VERSION 5.8 ;
BUSBITCHARS "[]" ;
DIVIDERCHAR "/" ;
UNITS
    DATABASE MICRONS 1000 ;
END UNITS

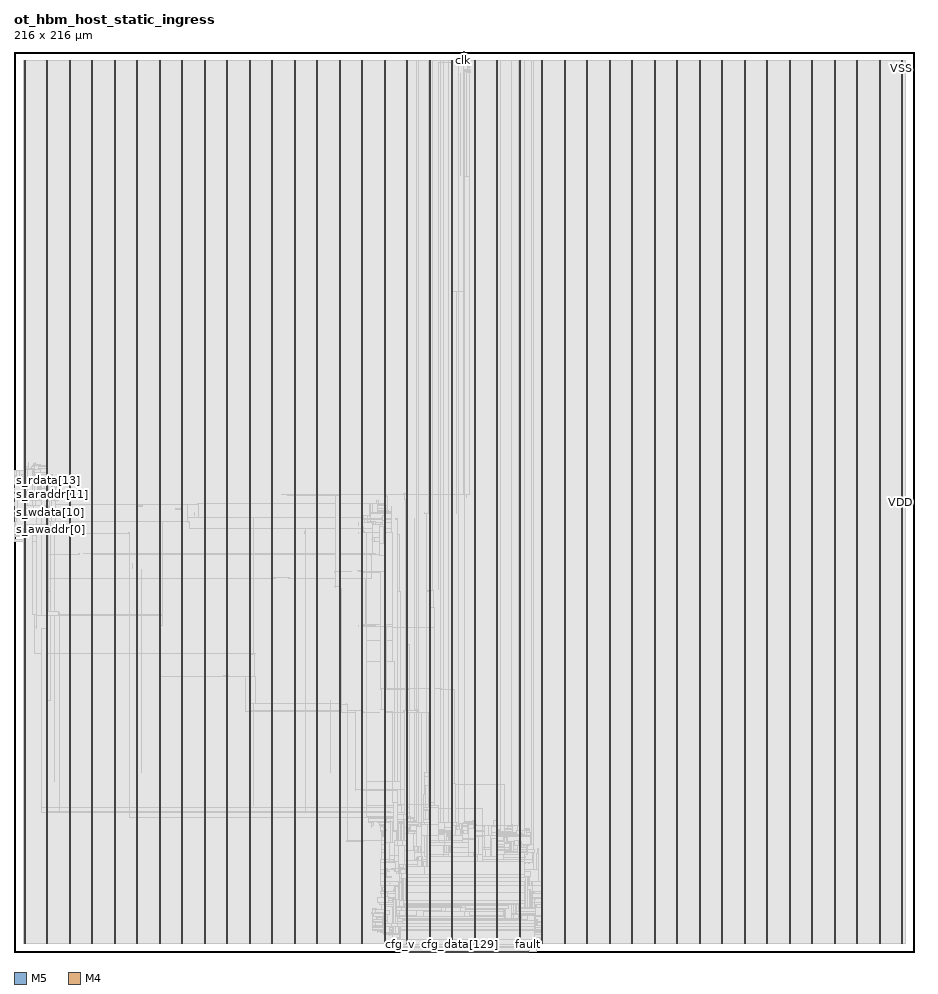
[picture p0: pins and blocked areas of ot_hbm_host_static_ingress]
MACRO ot_hbm_host_static_ingress
  FOREIGN ot_hbm_host_static_ingress 0 0 ;
  CLASS BLOCK ;
  SIZE 216 BY 216 ;
  PIN block_ready
    DIRECTION INPUT ;
    USE SIGNAL ;
    PORT
      LAYER M5 ;
        RECT  108 215.916 108.024 216 ;
    END
  END block_ready
  PIN cfg_addr[0]
    DIRECTION OUTPUT ;
    USE SIGNAL ;
    PORT
      LAYER M5 ;
        RECT  93.504 0 93.528 0.084 ;
    END
  END cfg_addr[0]
  PIN cfg_addr[10]
    DIRECTION OUTPUT ;
    USE SIGNAL ;
    PORT
      LAYER M5 ;
        RECT  94.464 0 94.488 0.084 ;
    END
  END cfg_addr[10]
  PIN cfg_addr[11]
    DIRECTION OUTPUT ;
    USE SIGNAL ;
    PORT
      LAYER M5 ;
        RECT  94.56 0 94.584 0.084 ;
    END
  END cfg_addr[11]
  PIN cfg_addr[1]
    DIRECTION OUTPUT ;
    USE SIGNAL ;
    PORT
      LAYER M5 ;
        RECT  93.6 0 93.624 0.084 ;
    END
  END cfg_addr[1]
  PIN cfg_addr[2]
    DIRECTION OUTPUT ;
    USE SIGNAL ;
    PORT
      LAYER M5 ;
        RECT  93.696 0 93.72 0.084 ;
    END
  END cfg_addr[2]
  PIN cfg_addr[3]
    DIRECTION OUTPUT ;
    USE SIGNAL ;
    PORT
      LAYER M5 ;
        RECT  93.792 0 93.816 0.084 ;
    END
  END cfg_addr[3]
  PIN cfg_addr[4]
    DIRECTION OUTPUT ;
    USE SIGNAL ;
    PORT
      LAYER M5 ;
        RECT  93.888 0 93.912 0.084 ;
    END
  END cfg_addr[4]
  PIN cfg_addr[5]
    DIRECTION OUTPUT ;
    USE SIGNAL ;
    PORT
      LAYER M5 ;
        RECT  93.984 0 94.008 0.084 ;
    END
  END cfg_addr[5]
  PIN cfg_addr[6]
    DIRECTION OUTPUT ;
    USE SIGNAL ;
    PORT
      LAYER M5 ;
        RECT  94.08 0 94.104 0.084 ;
    END
  END cfg_addr[6]
  PIN cfg_addr[7]
    DIRECTION OUTPUT ;
    USE SIGNAL ;
    PORT
      LAYER M5 ;
        RECT  94.176 0 94.2 0.084 ;
    END
  END cfg_addr[7]
  PIN cfg_addr[8]
    DIRECTION OUTPUT ;
    USE SIGNAL ;
    PORT
      LAYER M5 ;
        RECT  94.272 0 94.296 0.084 ;
    END
  END cfg_addr[8]
  PIN cfg_addr[9]
    DIRECTION OUTPUT ;
    USE SIGNAL ;
    PORT
      LAYER M5 ;
        RECT  94.368 0 94.392 0.084 ;
    END
  END cfg_addr[9]
  PIN cfg_data[0]
    DIRECTION OUTPUT ;
    USE SIGNAL ;
    PORT
      LAYER M5 ;
        RECT  94.656 0 94.68 0.084 ;
    END
  END cfg_data[0]
  PIN cfg_data[100]
    DIRECTION OUTPUT ;
    USE SIGNAL ;
    PORT
      LAYER M5 ;
        RECT  104.256 0 104.28 0.084 ;
    END
  END cfg_data[100]
  PIN cfg_data[101]
    DIRECTION OUTPUT ;
    USE SIGNAL ;
    PORT
      LAYER M5 ;
        RECT  104.352 0 104.376 0.084 ;
    END
  END cfg_data[101]
  PIN cfg_data[102]
    DIRECTION OUTPUT ;
    USE SIGNAL ;
    PORT
      LAYER M5 ;
        RECT  104.448 0 104.472 0.084 ;
    END
  END cfg_data[102]
  PIN cfg_data[103]
    DIRECTION OUTPUT ;
    USE SIGNAL ;
    PORT
      LAYER M5 ;
        RECT  104.544 0 104.568 0.084 ;
    END
  END cfg_data[103]
  PIN cfg_data[104]
    DIRECTION OUTPUT ;
    USE SIGNAL ;
    PORT
      LAYER M5 ;
        RECT  104.64 0 104.664 0.084 ;
    END
  END cfg_data[104]
  PIN cfg_data[105]
    DIRECTION OUTPUT ;
    USE SIGNAL ;
    PORT
      LAYER M5 ;
        RECT  104.736 0 104.76 0.084 ;
    END
  END cfg_data[105]
  PIN cfg_data[106]
    DIRECTION OUTPUT ;
    USE SIGNAL ;
    PORT
      LAYER M5 ;
        RECT  104.832 0 104.856 0.084 ;
    END
  END cfg_data[106]
  PIN cfg_data[107]
    DIRECTION OUTPUT ;
    USE SIGNAL ;
    PORT
      LAYER M5 ;
        RECT  104.928 0 104.952 0.084 ;
    END
  END cfg_data[107]
  PIN cfg_data[108]
    DIRECTION OUTPUT ;
    USE SIGNAL ;
    PORT
      LAYER M5 ;
        RECT  105.024 0 105.048 0.084 ;
    END
  END cfg_data[108]
  PIN cfg_data[109]
    DIRECTION OUTPUT ;
    USE SIGNAL ;
    PORT
      LAYER M5 ;
        RECT  105.12 0 105.144 0.084 ;
    END
  END cfg_data[109]
  PIN cfg_data[10]
    DIRECTION OUTPUT ;
    USE SIGNAL ;
    PORT
      LAYER M5 ;
        RECT  95.616 0 95.64 0.084 ;
    END
  END cfg_data[10]
  PIN cfg_data[110]
    DIRECTION OUTPUT ;
    USE SIGNAL ;
    PORT
      LAYER M5 ;
        RECT  105.216 0 105.24 0.084 ;
    END
  END cfg_data[110]
  PIN cfg_data[111]
    DIRECTION OUTPUT ;
    USE SIGNAL ;
    PORT
      LAYER M5 ;
        RECT  105.312 0 105.336 0.084 ;
    END
  END cfg_data[111]
  PIN cfg_data[112]
    DIRECTION OUTPUT ;
    USE SIGNAL ;
    PORT
      LAYER M5 ;
        RECT  105.408 0 105.432 0.084 ;
    END
  END cfg_data[112]
  PIN cfg_data[113]
    DIRECTION OUTPUT ;
    USE SIGNAL ;
    PORT
      LAYER M5 ;
        RECT  105.504 0 105.528 0.084 ;
    END
  END cfg_data[113]
  PIN cfg_data[114]
    DIRECTION OUTPUT ;
    USE SIGNAL ;
    PORT
      LAYER M5 ;
        RECT  105.6 0 105.624 0.084 ;
    END
  END cfg_data[114]
  PIN cfg_data[115]
    DIRECTION OUTPUT ;
    USE SIGNAL ;
    PORT
      LAYER M5 ;
        RECT  105.696 0 105.72 0.084 ;
    END
  END cfg_data[115]
  PIN cfg_data[116]
    DIRECTION OUTPUT ;
    USE SIGNAL ;
    PORT
      LAYER M5 ;
        RECT  105.792 0 105.816 0.084 ;
    END
  END cfg_data[116]
  PIN cfg_data[117]
    DIRECTION OUTPUT ;
    USE SIGNAL ;
    PORT
      LAYER M5 ;
        RECT  105.888 0 105.912 0.084 ;
    END
  END cfg_data[117]
  PIN cfg_data[118]
    DIRECTION OUTPUT ;
    USE SIGNAL ;
    PORT
      LAYER M5 ;
        RECT  105.984 0 106.008 0.084 ;
    END
  END cfg_data[118]
  PIN cfg_data[119]
    DIRECTION OUTPUT ;
    USE SIGNAL ;
    PORT
      LAYER M5 ;
        RECT  106.08 0 106.104 0.084 ;
    END
  END cfg_data[119]
  PIN cfg_data[11]
    DIRECTION OUTPUT ;
    USE SIGNAL ;
    PORT
      LAYER M5 ;
        RECT  95.712 0 95.736 0.084 ;
    END
  END cfg_data[11]
  PIN cfg_data[120]
    DIRECTION OUTPUT ;
    USE SIGNAL ;
    PORT
      LAYER M5 ;
        RECT  106.176 0 106.2 0.084 ;
    END
  END cfg_data[120]
  PIN cfg_data[121]
    DIRECTION OUTPUT ;
    USE SIGNAL ;
    PORT
      LAYER M5 ;
        RECT  106.272 0 106.296 0.084 ;
    END
  END cfg_data[121]
  PIN cfg_data[122]
    DIRECTION OUTPUT ;
    USE SIGNAL ;
    PORT
      LAYER M5 ;
        RECT  106.368 0 106.392 0.084 ;
    END
  END cfg_data[122]
  PIN cfg_data[123]
    DIRECTION OUTPUT ;
    USE SIGNAL ;
    PORT
      LAYER M5 ;
        RECT  106.464 0 106.488 0.084 ;
    END
  END cfg_data[123]
  PIN cfg_data[124]
    DIRECTION OUTPUT ;
    USE SIGNAL ;
    PORT
      LAYER M5 ;
        RECT  106.56 0 106.584 0.084 ;
    END
  END cfg_data[124]
  PIN cfg_data[125]
    DIRECTION OUTPUT ;
    USE SIGNAL ;
    PORT
      LAYER M5 ;
        RECT  106.656 0 106.68 0.084 ;
    END
  END cfg_data[125]
  PIN cfg_data[126]
    DIRECTION OUTPUT ;
    USE SIGNAL ;
    PORT
      LAYER M5 ;
        RECT  106.752 0 106.776 0.084 ;
    END
  END cfg_data[126]
  PIN cfg_data[127]
    DIRECTION OUTPUT ;
    USE SIGNAL ;
    PORT
      LAYER M5 ;
        RECT  106.848 0 106.872 0.084 ;
    END
  END cfg_data[127]
  PIN cfg_data[128]
    DIRECTION OUTPUT ;
    USE SIGNAL ;
    PORT
      LAYER M5 ;
        RECT  106.944 0 106.968 0.084 ;
    END
  END cfg_data[128]
  PIN cfg_data[129]
    DIRECTION OUTPUT ;
    USE SIGNAL ;
    PORT
      LAYER M5 ;
        RECT  107.04 0 107.064 0.084 ;
    END
  END cfg_data[129]
  PIN cfg_data[12]
    DIRECTION OUTPUT ;
    USE SIGNAL ;
    PORT
      LAYER M5 ;
        RECT  95.808 0 95.832 0.084 ;
    END
  END cfg_data[12]
  PIN cfg_data[130]
    DIRECTION OUTPUT ;
    USE SIGNAL ;
    PORT
      LAYER M5 ;
        RECT  107.136 0 107.16 0.084 ;
    END
  END cfg_data[130]
  PIN cfg_data[131]
    DIRECTION OUTPUT ;
    USE SIGNAL ;
    PORT
      LAYER M5 ;
        RECT  107.232 0 107.256 0.084 ;
    END
  END cfg_data[131]
  PIN cfg_data[132]
    DIRECTION OUTPUT ;
    USE SIGNAL ;
    PORT
      LAYER M5 ;
        RECT  107.328 0 107.352 0.084 ;
    END
  END cfg_data[132]
  PIN cfg_data[133]
    DIRECTION OUTPUT ;
    USE SIGNAL ;
    PORT
      LAYER M5 ;
        RECT  107.424 0 107.448 0.084 ;
    END
  END cfg_data[133]
  PIN cfg_data[134]
    DIRECTION OUTPUT ;
    USE SIGNAL ;
    PORT
      LAYER M5 ;
        RECT  107.52 0 107.544 0.084 ;
    END
  END cfg_data[134]
  PIN cfg_data[135]
    DIRECTION OUTPUT ;
    USE SIGNAL ;
    PORT
      LAYER M5 ;
        RECT  107.616 0 107.64 0.084 ;
    END
  END cfg_data[135]
  PIN cfg_data[136]
    DIRECTION OUTPUT ;
    USE SIGNAL ;
    PORT
      LAYER M5 ;
        RECT  107.712 0 107.736 0.084 ;
    END
  END cfg_data[136]
  PIN cfg_data[137]
    DIRECTION OUTPUT ;
    USE SIGNAL ;
    PORT
      LAYER M5 ;
        RECT  107.808 0 107.832 0.084 ;
    END
  END cfg_data[137]
  PIN cfg_data[138]
    DIRECTION OUTPUT ;
    USE SIGNAL ;
    PORT
      LAYER M5 ;
        RECT  107.904 0 107.928 0.084 ;
    END
  END cfg_data[138]
  PIN cfg_data[139]
    DIRECTION OUTPUT ;
    USE SIGNAL ;
    PORT
      LAYER M5 ;
        RECT  108 0 108.024 0.084 ;
    END
  END cfg_data[139]
  PIN cfg_data[13]
    DIRECTION OUTPUT ;
    USE SIGNAL ;
    PORT
      LAYER M5 ;
        RECT  95.904 0 95.928 0.084 ;
    END
  END cfg_data[13]
  PIN cfg_data[140]
    DIRECTION OUTPUT ;
    USE SIGNAL ;
    PORT
      LAYER M5 ;
        RECT  108.096 0 108.12 0.084 ;
    END
  END cfg_data[140]
  PIN cfg_data[141]
    DIRECTION OUTPUT ;
    USE SIGNAL ;
    PORT
      LAYER M5 ;
        RECT  108.192 0 108.216 0.084 ;
    END
  END cfg_data[141]
  PIN cfg_data[142]
    DIRECTION OUTPUT ;
    USE SIGNAL ;
    PORT
      LAYER M5 ;
        RECT  108.288 0 108.312 0.084 ;
    END
  END cfg_data[142]
  PIN cfg_data[143]
    DIRECTION OUTPUT ;
    USE SIGNAL ;
    PORT
      LAYER M5 ;
        RECT  108.384 0 108.408 0.084 ;
    END
  END cfg_data[143]
  PIN cfg_data[144]
    DIRECTION OUTPUT ;
    USE SIGNAL ;
    PORT
      LAYER M5 ;
        RECT  108.48 0 108.504 0.084 ;
    END
  END cfg_data[144]
  PIN cfg_data[145]
    DIRECTION OUTPUT ;
    USE SIGNAL ;
    PORT
      LAYER M5 ;
        RECT  108.576 0 108.6 0.084 ;
    END
  END cfg_data[145]
  PIN cfg_data[146]
    DIRECTION OUTPUT ;
    USE SIGNAL ;
    PORT
      LAYER M5 ;
        RECT  108.672 0 108.696 0.084 ;
    END
  END cfg_data[146]
  PIN cfg_data[147]
    DIRECTION OUTPUT ;
    USE SIGNAL ;
    PORT
      LAYER M5 ;
        RECT  108.768 0 108.792 0.084 ;
    END
  END cfg_data[147]
  PIN cfg_data[148]
    DIRECTION OUTPUT ;
    USE SIGNAL ;
    PORT
      LAYER M5 ;
        RECT  108.864 0 108.888 0.084 ;
    END
  END cfg_data[148]
  PIN cfg_data[149]
    DIRECTION OUTPUT ;
    USE SIGNAL ;
    PORT
      LAYER M5 ;
        RECT  108.96 0 108.984 0.084 ;
    END
  END cfg_data[149]
  PIN cfg_data[14]
    DIRECTION OUTPUT ;
    USE SIGNAL ;
    PORT
      LAYER M5 ;
        RECT  96 0 96.024 0.084 ;
    END
  END cfg_data[14]
  PIN cfg_data[150]
    DIRECTION OUTPUT ;
    USE SIGNAL ;
    PORT
      LAYER M5 ;
        RECT  109.056 0 109.08 0.084 ;
    END
  END cfg_data[150]
  PIN cfg_data[151]
    DIRECTION OUTPUT ;
    USE SIGNAL ;
    PORT
      LAYER M5 ;
        RECT  109.152 0 109.176 0.084 ;
    END
  END cfg_data[151]
  PIN cfg_data[152]
    DIRECTION OUTPUT ;
    USE SIGNAL ;
    PORT
      LAYER M5 ;
        RECT  109.248 0 109.272 0.084 ;
    END
  END cfg_data[152]
  PIN cfg_data[153]
    DIRECTION OUTPUT ;
    USE SIGNAL ;
    PORT
      LAYER M5 ;
        RECT  109.344 0 109.368 0.084 ;
    END
  END cfg_data[153]
  PIN cfg_data[154]
    DIRECTION OUTPUT ;
    USE SIGNAL ;
    PORT
      LAYER M5 ;
        RECT  109.44 0 109.464 0.084 ;
    END
  END cfg_data[154]
  PIN cfg_data[155]
    DIRECTION OUTPUT ;
    USE SIGNAL ;
    PORT
      LAYER M5 ;
        RECT  109.536 0 109.56 0.084 ;
    END
  END cfg_data[155]
  PIN cfg_data[156]
    DIRECTION OUTPUT ;
    USE SIGNAL ;
    PORT
      LAYER M5 ;
        RECT  109.632 0 109.656 0.084 ;
    END
  END cfg_data[156]
  PIN cfg_data[157]
    DIRECTION OUTPUT ;
    USE SIGNAL ;
    PORT
      LAYER M5 ;
        RECT  109.728 0 109.752 0.084 ;
    END
  END cfg_data[157]
  PIN cfg_data[158]
    DIRECTION OUTPUT ;
    USE SIGNAL ;
    PORT
      LAYER M5 ;
        RECT  109.824 0 109.848 0.084 ;
    END
  END cfg_data[158]
  PIN cfg_data[159]
    DIRECTION OUTPUT ;
    USE SIGNAL ;
    PORT
      LAYER M5 ;
        RECT  109.92 0 109.944 0.084 ;
    END
  END cfg_data[159]
  PIN cfg_data[15]
    DIRECTION OUTPUT ;
    USE SIGNAL ;
    PORT
      LAYER M5 ;
        RECT  96.096 0 96.12 0.084 ;
    END
  END cfg_data[15]
  PIN cfg_data[160]
    DIRECTION OUTPUT ;
    USE SIGNAL ;
    PORT
      LAYER M5 ;
        RECT  110.016 0 110.04 0.084 ;
    END
  END cfg_data[160]
  PIN cfg_data[161]
    DIRECTION OUTPUT ;
    USE SIGNAL ;
    PORT
      LAYER M5 ;
        RECT  110.112 0 110.136 0.084 ;
    END
  END cfg_data[161]
  PIN cfg_data[162]
    DIRECTION OUTPUT ;
    USE SIGNAL ;
    PORT
      LAYER M5 ;
        RECT  110.208 0 110.232 0.084 ;
    END
  END cfg_data[162]
  PIN cfg_data[163]
    DIRECTION OUTPUT ;
    USE SIGNAL ;
    PORT
      LAYER M5 ;
        RECT  110.304 0 110.328 0.084 ;
    END
  END cfg_data[163]
  PIN cfg_data[164]
    DIRECTION OUTPUT ;
    USE SIGNAL ;
    PORT
      LAYER M5 ;
        RECT  110.4 0 110.424 0.084 ;
    END
  END cfg_data[164]
  PIN cfg_data[165]
    DIRECTION OUTPUT ;
    USE SIGNAL ;
    PORT
      LAYER M5 ;
        RECT  110.496 0 110.52 0.084 ;
    END
  END cfg_data[165]
  PIN cfg_data[166]
    DIRECTION OUTPUT ;
    USE SIGNAL ;
    PORT
      LAYER M5 ;
        RECT  110.592 0 110.616 0.084 ;
    END
  END cfg_data[166]
  PIN cfg_data[167]
    DIRECTION OUTPUT ;
    USE SIGNAL ;
    PORT
      LAYER M5 ;
        RECT  110.688 0 110.712 0.084 ;
    END
  END cfg_data[167]
  PIN cfg_data[168]
    DIRECTION OUTPUT ;
    USE SIGNAL ;
    PORT
      LAYER M5 ;
        RECT  110.784 0 110.808 0.084 ;
    END
  END cfg_data[168]
  PIN cfg_data[169]
    DIRECTION OUTPUT ;
    USE SIGNAL ;
    PORT
      LAYER M5 ;
        RECT  110.88 0 110.904 0.084 ;
    END
  END cfg_data[169]
  PIN cfg_data[16]
    DIRECTION OUTPUT ;
    USE SIGNAL ;
    PORT
      LAYER M5 ;
        RECT  96.192 0 96.216 0.084 ;
    END
  END cfg_data[16]
  PIN cfg_data[170]
    DIRECTION OUTPUT ;
    USE SIGNAL ;
    PORT
      LAYER M5 ;
        RECT  110.976 0 111 0.084 ;
    END
  END cfg_data[170]
  PIN cfg_data[171]
    DIRECTION OUTPUT ;
    USE SIGNAL ;
    PORT
      LAYER M5 ;
        RECT  111.072 0 111.096 0.084 ;
    END
  END cfg_data[171]
  PIN cfg_data[172]
    DIRECTION OUTPUT ;
    USE SIGNAL ;
    PORT
      LAYER M5 ;
        RECT  111.168 0 111.192 0.084 ;
    END
  END cfg_data[172]
  PIN cfg_data[173]
    DIRECTION OUTPUT ;
    USE SIGNAL ;
    PORT
      LAYER M5 ;
        RECT  111.264 0 111.288 0.084 ;
    END
  END cfg_data[173]
  PIN cfg_data[174]
    DIRECTION OUTPUT ;
    USE SIGNAL ;
    PORT
      LAYER M5 ;
        RECT  111.36 0 111.384 0.084 ;
    END
  END cfg_data[174]
  PIN cfg_data[175]
    DIRECTION OUTPUT ;
    USE SIGNAL ;
    PORT
      LAYER M5 ;
        RECT  111.456 0 111.48 0.084 ;
    END
  END cfg_data[175]
  PIN cfg_data[176]
    DIRECTION OUTPUT ;
    USE SIGNAL ;
    PORT
      LAYER M5 ;
        RECT  111.552 0 111.576 0.084 ;
    END
  END cfg_data[176]
  PIN cfg_data[177]
    DIRECTION OUTPUT ;
    USE SIGNAL ;
    PORT
      LAYER M5 ;
        RECT  111.648 0 111.672 0.084 ;
    END
  END cfg_data[177]
  PIN cfg_data[178]
    DIRECTION OUTPUT ;
    USE SIGNAL ;
    PORT
      LAYER M5 ;
        RECT  111.744 0 111.768 0.084 ;
    END
  END cfg_data[178]
  PIN cfg_data[179]
    DIRECTION OUTPUT ;
    USE SIGNAL ;
    PORT
      LAYER M5 ;
        RECT  111.84 0 111.864 0.084 ;
    END
  END cfg_data[179]
  PIN cfg_data[17]
    DIRECTION OUTPUT ;
    USE SIGNAL ;
    PORT
      LAYER M5 ;
        RECT  96.288 0 96.312 0.084 ;
    END
  END cfg_data[17]
  PIN cfg_data[180]
    DIRECTION OUTPUT ;
    USE SIGNAL ;
    PORT
      LAYER M5 ;
        RECT  111.936 0 111.96 0.084 ;
    END
  END cfg_data[180]
  PIN cfg_data[181]
    DIRECTION OUTPUT ;
    USE SIGNAL ;
    PORT
      LAYER M5 ;
        RECT  112.032 0 112.056 0.084 ;
    END
  END cfg_data[181]
  PIN cfg_data[182]
    DIRECTION OUTPUT ;
    USE SIGNAL ;
    PORT
      LAYER M5 ;
        RECT  112.128 0 112.152 0.084 ;
    END
  END cfg_data[182]
  PIN cfg_data[183]
    DIRECTION OUTPUT ;
    USE SIGNAL ;
    PORT
      LAYER M5 ;
        RECT  112.224 0 112.248 0.084 ;
    END
  END cfg_data[183]
  PIN cfg_data[184]
    DIRECTION OUTPUT ;
    USE SIGNAL ;
    PORT
      LAYER M5 ;
        RECT  112.32 0 112.344 0.084 ;
    END
  END cfg_data[184]
  PIN cfg_data[185]
    DIRECTION OUTPUT ;
    USE SIGNAL ;
    PORT
      LAYER M5 ;
        RECT  112.416 0 112.44 0.084 ;
    END
  END cfg_data[185]
  PIN cfg_data[186]
    DIRECTION OUTPUT ;
    USE SIGNAL ;
    PORT
      LAYER M5 ;
        RECT  112.512 0 112.536 0.084 ;
    END
  END cfg_data[186]
  PIN cfg_data[187]
    DIRECTION OUTPUT ;
    USE SIGNAL ;
    PORT
      LAYER M5 ;
        RECT  112.608 0 112.632 0.084 ;
    END
  END cfg_data[187]
  PIN cfg_data[188]
    DIRECTION OUTPUT ;
    USE SIGNAL ;
    PORT
      LAYER M5 ;
        RECT  112.704 0 112.728 0.084 ;
    END
  END cfg_data[188]
  PIN cfg_data[189]
    DIRECTION OUTPUT ;
    USE SIGNAL ;
    PORT
      LAYER M5 ;
        RECT  112.8 0 112.824 0.084 ;
    END
  END cfg_data[189]
  PIN cfg_data[18]
    DIRECTION OUTPUT ;
    USE SIGNAL ;
    PORT
      LAYER M5 ;
        RECT  96.384 0 96.408 0.084 ;
    END
  END cfg_data[18]
  PIN cfg_data[190]
    DIRECTION OUTPUT ;
    USE SIGNAL ;
    PORT
      LAYER M5 ;
        RECT  112.896 0 112.92 0.084 ;
    END
  END cfg_data[190]
  PIN cfg_data[191]
    DIRECTION OUTPUT ;
    USE SIGNAL ;
    PORT
      LAYER M5 ;
        RECT  112.992 0 113.016 0.084 ;
    END
  END cfg_data[191]
  PIN cfg_data[192]
    DIRECTION OUTPUT ;
    USE SIGNAL ;
    PORT
      LAYER M5 ;
        RECT  113.088 0 113.112 0.084 ;
    END
  END cfg_data[192]
  PIN cfg_data[193]
    DIRECTION OUTPUT ;
    USE SIGNAL ;
    PORT
      LAYER M5 ;
        RECT  113.184 0 113.208 0.084 ;
    END
  END cfg_data[193]
  PIN cfg_data[194]
    DIRECTION OUTPUT ;
    USE SIGNAL ;
    PORT
      LAYER M5 ;
        RECT  113.28 0 113.304 0.084 ;
    END
  END cfg_data[194]
  PIN cfg_data[195]
    DIRECTION OUTPUT ;
    USE SIGNAL ;
    PORT
      LAYER M5 ;
        RECT  113.376 0 113.4 0.084 ;
    END
  END cfg_data[195]
  PIN cfg_data[196]
    DIRECTION OUTPUT ;
    USE SIGNAL ;
    PORT
      LAYER M5 ;
        RECT  113.472 0 113.496 0.084 ;
    END
  END cfg_data[196]
  PIN cfg_data[197]
    DIRECTION OUTPUT ;
    USE SIGNAL ;
    PORT
      LAYER M5 ;
        RECT  113.568 0 113.592 0.084 ;
    END
  END cfg_data[197]
  PIN cfg_data[198]
    DIRECTION OUTPUT ;
    USE SIGNAL ;
    PORT
      LAYER M5 ;
        RECT  113.664 0 113.688 0.084 ;
    END
  END cfg_data[198]
  PIN cfg_data[199]
    DIRECTION OUTPUT ;
    USE SIGNAL ;
    PORT
      LAYER M5 ;
        RECT  113.76 0 113.784 0.084 ;
    END
  END cfg_data[199]
  PIN cfg_data[19]
    DIRECTION OUTPUT ;
    USE SIGNAL ;
    PORT
      LAYER M5 ;
        RECT  96.48 0 96.504 0.084 ;
    END
  END cfg_data[19]
  PIN cfg_data[1]
    DIRECTION OUTPUT ;
    USE SIGNAL ;
    PORT
      LAYER M5 ;
        RECT  94.752 0 94.776 0.084 ;
    END
  END cfg_data[1]
  PIN cfg_data[200]
    DIRECTION OUTPUT ;
    USE SIGNAL ;
    PORT
      LAYER M5 ;
        RECT  113.856 0 113.88 0.084 ;
    END
  END cfg_data[200]
  PIN cfg_data[201]
    DIRECTION OUTPUT ;
    USE SIGNAL ;
    PORT
      LAYER M5 ;
        RECT  113.952 0 113.976 0.084 ;
    END
  END cfg_data[201]
  PIN cfg_data[202]
    DIRECTION OUTPUT ;
    USE SIGNAL ;
    PORT
      LAYER M5 ;
        RECT  114.048 0 114.072 0.084 ;
    END
  END cfg_data[202]
  PIN cfg_data[203]
    DIRECTION OUTPUT ;
    USE SIGNAL ;
    PORT
      LAYER M5 ;
        RECT  114.144 0 114.168 0.084 ;
    END
  END cfg_data[203]
  PIN cfg_data[204]
    DIRECTION OUTPUT ;
    USE SIGNAL ;
    PORT
      LAYER M5 ;
        RECT  114.24 0 114.264 0.084 ;
    END
  END cfg_data[204]
  PIN cfg_data[205]
    DIRECTION OUTPUT ;
    USE SIGNAL ;
    PORT
      LAYER M5 ;
        RECT  114.336 0 114.36 0.084 ;
    END
  END cfg_data[205]
  PIN cfg_data[206]
    DIRECTION OUTPUT ;
    USE SIGNAL ;
    PORT
      LAYER M5 ;
        RECT  114.432 0 114.456 0.084 ;
    END
  END cfg_data[206]
  PIN cfg_data[207]
    DIRECTION OUTPUT ;
    USE SIGNAL ;
    PORT
      LAYER M5 ;
        RECT  114.528 0 114.552 0.084 ;
    END
  END cfg_data[207]
  PIN cfg_data[208]
    DIRECTION OUTPUT ;
    USE SIGNAL ;
    PORT
      LAYER M5 ;
        RECT  114.624 0 114.648 0.084 ;
    END
  END cfg_data[208]
  PIN cfg_data[209]
    DIRECTION OUTPUT ;
    USE SIGNAL ;
    PORT
      LAYER M5 ;
        RECT  114.72 0 114.744 0.084 ;
    END
  END cfg_data[209]
  PIN cfg_data[20]
    DIRECTION OUTPUT ;
    USE SIGNAL ;
    PORT
      LAYER M5 ;
        RECT  96.576 0 96.6 0.084 ;
    END
  END cfg_data[20]
  PIN cfg_data[210]
    DIRECTION OUTPUT ;
    USE SIGNAL ;
    PORT
      LAYER M5 ;
        RECT  114.816 0 114.84 0.084 ;
    END
  END cfg_data[210]
  PIN cfg_data[211]
    DIRECTION OUTPUT ;
    USE SIGNAL ;
    PORT
      LAYER M5 ;
        RECT  114.912 0 114.936 0.084 ;
    END
  END cfg_data[211]
  PIN cfg_data[212]
    DIRECTION OUTPUT ;
    USE SIGNAL ;
    PORT
      LAYER M5 ;
        RECT  115.008 0 115.032 0.084 ;
    END
  END cfg_data[212]
  PIN cfg_data[213]
    DIRECTION OUTPUT ;
    USE SIGNAL ;
    PORT
      LAYER M5 ;
        RECT  115.104 0 115.128 0.084 ;
    END
  END cfg_data[213]
  PIN cfg_data[214]
    DIRECTION OUTPUT ;
    USE SIGNAL ;
    PORT
      LAYER M5 ;
        RECT  115.2 0 115.224 0.084 ;
    END
  END cfg_data[214]
  PIN cfg_data[215]
    DIRECTION OUTPUT ;
    USE SIGNAL ;
    PORT
      LAYER M5 ;
        RECT  115.296 0 115.32 0.084 ;
    END
  END cfg_data[215]
  PIN cfg_data[216]
    DIRECTION OUTPUT ;
    USE SIGNAL ;
    PORT
      LAYER M5 ;
        RECT  115.392 0 115.416 0.084 ;
    END
  END cfg_data[216]
  PIN cfg_data[217]
    DIRECTION OUTPUT ;
    USE SIGNAL ;
    PORT
      LAYER M5 ;
        RECT  115.488 0 115.512 0.084 ;
    END
  END cfg_data[217]
  PIN cfg_data[218]
    DIRECTION OUTPUT ;
    USE SIGNAL ;
    PORT
      LAYER M5 ;
        RECT  115.584 0 115.608 0.084 ;
    END
  END cfg_data[218]
  PIN cfg_data[219]
    DIRECTION OUTPUT ;
    USE SIGNAL ;
    PORT
      LAYER M5 ;
        RECT  115.68 0 115.704 0.084 ;
    END
  END cfg_data[219]
  PIN cfg_data[21]
    DIRECTION OUTPUT ;
    USE SIGNAL ;
    PORT
      LAYER M5 ;
        RECT  96.672 0 96.696 0.084 ;
    END
  END cfg_data[21]
  PIN cfg_data[220]
    DIRECTION OUTPUT ;
    USE SIGNAL ;
    PORT
      LAYER M5 ;
        RECT  115.776 0 115.8 0.084 ;
    END
  END cfg_data[220]
  PIN cfg_data[221]
    DIRECTION OUTPUT ;
    USE SIGNAL ;
    PORT
      LAYER M5 ;
        RECT  115.872 0 115.896 0.084 ;
    END
  END cfg_data[221]
  PIN cfg_data[222]
    DIRECTION OUTPUT ;
    USE SIGNAL ;
    PORT
      LAYER M5 ;
        RECT  115.968 0 115.992 0.084 ;
    END
  END cfg_data[222]
  PIN cfg_data[223]
    DIRECTION OUTPUT ;
    USE SIGNAL ;
    PORT
      LAYER M5 ;
        RECT  116.064 0 116.088 0.084 ;
    END
  END cfg_data[223]
  PIN cfg_data[224]
    DIRECTION OUTPUT ;
    USE SIGNAL ;
    PORT
      LAYER M5 ;
        RECT  116.16 0 116.184 0.084 ;
    END
  END cfg_data[224]
  PIN cfg_data[225]
    DIRECTION OUTPUT ;
    USE SIGNAL ;
    PORT
      LAYER M5 ;
        RECT  116.256 0 116.28 0.084 ;
    END
  END cfg_data[225]
  PIN cfg_data[226]
    DIRECTION OUTPUT ;
    USE SIGNAL ;
    PORT
      LAYER M5 ;
        RECT  116.352 0 116.376 0.084 ;
    END
  END cfg_data[226]
  PIN cfg_data[227]
    DIRECTION OUTPUT ;
    USE SIGNAL ;
    PORT
      LAYER M5 ;
        RECT  116.448 0 116.472 0.084 ;
    END
  END cfg_data[227]
  PIN cfg_data[228]
    DIRECTION OUTPUT ;
    USE SIGNAL ;
    PORT
      LAYER M5 ;
        RECT  116.544 0 116.568 0.084 ;
    END
  END cfg_data[228]
  PIN cfg_data[229]
    DIRECTION OUTPUT ;
    USE SIGNAL ;
    PORT
      LAYER M5 ;
        RECT  116.64 0 116.664 0.084 ;
    END
  END cfg_data[229]
  PIN cfg_data[22]
    DIRECTION OUTPUT ;
    USE SIGNAL ;
    PORT
      LAYER M5 ;
        RECT  96.768 0 96.792 0.084 ;
    END
  END cfg_data[22]
  PIN cfg_data[230]
    DIRECTION OUTPUT ;
    USE SIGNAL ;
    PORT
      LAYER M5 ;
        RECT  116.736 0 116.76 0.084 ;
    END
  END cfg_data[230]
  PIN cfg_data[231]
    DIRECTION OUTPUT ;
    USE SIGNAL ;
    PORT
      LAYER M5 ;
        RECT  116.832 0 116.856 0.084 ;
    END
  END cfg_data[231]
  PIN cfg_data[232]
    DIRECTION OUTPUT ;
    USE SIGNAL ;
    PORT
      LAYER M5 ;
        RECT  116.928 0 116.952 0.084 ;
    END
  END cfg_data[232]
  PIN cfg_data[233]
    DIRECTION OUTPUT ;
    USE SIGNAL ;
    PORT
      LAYER M5 ;
        RECT  117.024 0 117.048 0.084 ;
    END
  END cfg_data[233]
  PIN cfg_data[234]
    DIRECTION OUTPUT ;
    USE SIGNAL ;
    PORT
      LAYER M5 ;
        RECT  117.12 0 117.144 0.084 ;
    END
  END cfg_data[234]
  PIN cfg_data[235]
    DIRECTION OUTPUT ;
    USE SIGNAL ;
    PORT
      LAYER M5 ;
        RECT  117.216 0 117.24 0.084 ;
    END
  END cfg_data[235]
  PIN cfg_data[236]
    DIRECTION OUTPUT ;
    USE SIGNAL ;
    PORT
      LAYER M5 ;
        RECT  117.312 0 117.336 0.084 ;
    END
  END cfg_data[236]
  PIN cfg_data[237]
    DIRECTION OUTPUT ;
    USE SIGNAL ;
    PORT
      LAYER M5 ;
        RECT  117.408 0 117.432 0.084 ;
    END
  END cfg_data[237]
  PIN cfg_data[238]
    DIRECTION OUTPUT ;
    USE SIGNAL ;
    PORT
      LAYER M5 ;
        RECT  117.504 0 117.528 0.084 ;
    END
  END cfg_data[238]
  PIN cfg_data[239]
    DIRECTION OUTPUT ;
    USE SIGNAL ;
    PORT
      LAYER M5 ;
        RECT  117.6 0 117.624 0.084 ;
    END
  END cfg_data[239]
  PIN cfg_data[23]
    DIRECTION OUTPUT ;
    USE SIGNAL ;
    PORT
      LAYER M5 ;
        RECT  96.864 0 96.888 0.084 ;
    END
  END cfg_data[23]
  PIN cfg_data[240]
    DIRECTION OUTPUT ;
    USE SIGNAL ;
    PORT
      LAYER M5 ;
        RECT  117.696 0 117.72 0.084 ;
    END
  END cfg_data[240]
  PIN cfg_data[241]
    DIRECTION OUTPUT ;
    USE SIGNAL ;
    PORT
      LAYER M5 ;
        RECT  117.792 0 117.816 0.084 ;
    END
  END cfg_data[241]
  PIN cfg_data[242]
    DIRECTION OUTPUT ;
    USE SIGNAL ;
    PORT
      LAYER M5 ;
        RECT  117.888 0 117.912 0.084 ;
    END
  END cfg_data[242]
  PIN cfg_data[243]
    DIRECTION OUTPUT ;
    USE SIGNAL ;
    PORT
      LAYER M5 ;
        RECT  117.984 0 118.008 0.084 ;
    END
  END cfg_data[243]
  PIN cfg_data[244]
    DIRECTION OUTPUT ;
    USE SIGNAL ;
    PORT
      LAYER M5 ;
        RECT  118.08 0 118.104 0.084 ;
    END
  END cfg_data[244]
  PIN cfg_data[245]
    DIRECTION OUTPUT ;
    USE SIGNAL ;
    PORT
      LAYER M5 ;
        RECT  118.176 0 118.2 0.084 ;
    END
  END cfg_data[245]
  PIN cfg_data[246]
    DIRECTION OUTPUT ;
    USE SIGNAL ;
    PORT
      LAYER M5 ;
        RECT  118.272 0 118.296 0.084 ;
    END
  END cfg_data[246]
  PIN cfg_data[247]
    DIRECTION OUTPUT ;
    USE SIGNAL ;
    PORT
      LAYER M5 ;
        RECT  118.368 0 118.392 0.084 ;
    END
  END cfg_data[247]
  PIN cfg_data[248]
    DIRECTION OUTPUT ;
    USE SIGNAL ;
    PORT
      LAYER M5 ;
        RECT  118.464 0 118.488 0.084 ;
    END
  END cfg_data[248]
  PIN cfg_data[249]
    DIRECTION OUTPUT ;
    USE SIGNAL ;
    PORT
      LAYER M5 ;
        RECT  118.56 0 118.584 0.084 ;
    END
  END cfg_data[249]
  PIN cfg_data[24]
    DIRECTION OUTPUT ;
    USE SIGNAL ;
    PORT
      LAYER M5 ;
        RECT  96.96 0 96.984 0.084 ;
    END
  END cfg_data[24]
  PIN cfg_data[250]
    DIRECTION OUTPUT ;
    USE SIGNAL ;
    PORT
      LAYER M5 ;
        RECT  118.656 0 118.68 0.084 ;
    END
  END cfg_data[250]
  PIN cfg_data[251]
    DIRECTION OUTPUT ;
    USE SIGNAL ;
    PORT
      LAYER M5 ;
        RECT  118.752 0 118.776 0.084 ;
    END
  END cfg_data[251]
  PIN cfg_data[252]
    DIRECTION OUTPUT ;
    USE SIGNAL ;
    PORT
      LAYER M5 ;
        RECT  118.848 0 118.872 0.084 ;
    END
  END cfg_data[252]
  PIN cfg_data[253]
    DIRECTION OUTPUT ;
    USE SIGNAL ;
    PORT
      LAYER M5 ;
        RECT  118.944 0 118.968 0.084 ;
    END
  END cfg_data[253]
  PIN cfg_data[254]
    DIRECTION OUTPUT ;
    USE SIGNAL ;
    PORT
      LAYER M5 ;
        RECT  119.04 0 119.064 0.084 ;
    END
  END cfg_data[254]
  PIN cfg_data[255]
    DIRECTION OUTPUT ;
    USE SIGNAL ;
    PORT
      LAYER M5 ;
        RECT  119.136 0 119.16 0.084 ;
    END
  END cfg_data[255]
  PIN cfg_data[25]
    DIRECTION OUTPUT ;
    USE SIGNAL ;
    PORT
      LAYER M5 ;
        RECT  97.056 0 97.08 0.084 ;
    END
  END cfg_data[25]
  PIN cfg_data[26]
    DIRECTION OUTPUT ;
    USE SIGNAL ;
    PORT
      LAYER M5 ;
        RECT  97.152 0 97.176 0.084 ;
    END
  END cfg_data[26]
  PIN cfg_data[27]
    DIRECTION OUTPUT ;
    USE SIGNAL ;
    PORT
      LAYER M5 ;
        RECT  97.248 0 97.272 0.084 ;
    END
  END cfg_data[27]
  PIN cfg_data[28]
    DIRECTION OUTPUT ;
    USE SIGNAL ;
    PORT
      LAYER M5 ;
        RECT  97.344 0 97.368 0.084 ;
    END
  END cfg_data[28]
  PIN cfg_data[29]
    DIRECTION OUTPUT ;
    USE SIGNAL ;
    PORT
      LAYER M5 ;
        RECT  97.44 0 97.464 0.084 ;
    END
  END cfg_data[29]
  PIN cfg_data[2]
    DIRECTION OUTPUT ;
    USE SIGNAL ;
    PORT
      LAYER M5 ;
        RECT  94.848 0 94.872 0.084 ;
    END
  END cfg_data[2]
  PIN cfg_data[30]
    DIRECTION OUTPUT ;
    USE SIGNAL ;
    PORT
      LAYER M5 ;
        RECT  97.536 0 97.56 0.084 ;
    END
  END cfg_data[30]
  PIN cfg_data[31]
    DIRECTION OUTPUT ;
    USE SIGNAL ;
    PORT
      LAYER M5 ;
        RECT  97.632 0 97.656 0.084 ;
    END
  END cfg_data[31]
  PIN cfg_data[32]
    DIRECTION OUTPUT ;
    USE SIGNAL ;
    PORT
      LAYER M5 ;
        RECT  97.728 0 97.752 0.084 ;
    END
  END cfg_data[32]
  PIN cfg_data[33]
    DIRECTION OUTPUT ;
    USE SIGNAL ;
    PORT
      LAYER M5 ;
        RECT  97.824 0 97.848 0.084 ;
    END
  END cfg_data[33]
  PIN cfg_data[34]
    DIRECTION OUTPUT ;
    USE SIGNAL ;
    PORT
      LAYER M5 ;
        RECT  97.92 0 97.944 0.084 ;
    END
  END cfg_data[34]
  PIN cfg_data[35]
    DIRECTION OUTPUT ;
    USE SIGNAL ;
    PORT
      LAYER M5 ;
        RECT  98.016 0 98.04 0.084 ;
    END
  END cfg_data[35]
  PIN cfg_data[36]
    DIRECTION OUTPUT ;
    USE SIGNAL ;
    PORT
      LAYER M5 ;
        RECT  98.112 0 98.136 0.084 ;
    END
  END cfg_data[36]
  PIN cfg_data[37]
    DIRECTION OUTPUT ;
    USE SIGNAL ;
    PORT
      LAYER M5 ;
        RECT  98.208 0 98.232 0.084 ;
    END
  END cfg_data[37]
  PIN cfg_data[38]
    DIRECTION OUTPUT ;
    USE SIGNAL ;
    PORT
      LAYER M5 ;
        RECT  98.304 0 98.328 0.084 ;
    END
  END cfg_data[38]
  PIN cfg_data[39]
    DIRECTION OUTPUT ;
    USE SIGNAL ;
    PORT
      LAYER M5 ;
        RECT  98.4 0 98.424 0.084 ;
    END
  END cfg_data[39]
  PIN cfg_data[3]
    DIRECTION OUTPUT ;
    USE SIGNAL ;
    PORT
      LAYER M5 ;
        RECT  94.944 0 94.968 0.084 ;
    END
  END cfg_data[3]
  PIN cfg_data[40]
    DIRECTION OUTPUT ;
    USE SIGNAL ;
    PORT
      LAYER M5 ;
        RECT  98.496 0 98.52 0.084 ;
    END
  END cfg_data[40]
  PIN cfg_data[41]
    DIRECTION OUTPUT ;
    USE SIGNAL ;
    PORT
      LAYER M5 ;
        RECT  98.592 0 98.616 0.084 ;
    END
  END cfg_data[41]
  PIN cfg_data[42]
    DIRECTION OUTPUT ;
    USE SIGNAL ;
    PORT
      LAYER M5 ;
        RECT  98.688 0 98.712 0.084 ;
    END
  END cfg_data[42]
  PIN cfg_data[43]
    DIRECTION OUTPUT ;
    USE SIGNAL ;
    PORT
      LAYER M5 ;
        RECT  98.784 0 98.808 0.084 ;
    END
  END cfg_data[43]
  PIN cfg_data[44]
    DIRECTION OUTPUT ;
    USE SIGNAL ;
    PORT
      LAYER M5 ;
        RECT  98.88 0 98.904 0.084 ;
    END
  END cfg_data[44]
  PIN cfg_data[45]
    DIRECTION OUTPUT ;
    USE SIGNAL ;
    PORT
      LAYER M5 ;
        RECT  98.976 0 99 0.084 ;
    END
  END cfg_data[45]
  PIN cfg_data[46]
    DIRECTION OUTPUT ;
    USE SIGNAL ;
    PORT
      LAYER M5 ;
        RECT  99.072 0 99.096 0.084 ;
    END
  END cfg_data[46]
  PIN cfg_data[47]
    DIRECTION OUTPUT ;
    USE SIGNAL ;
    PORT
      LAYER M5 ;
        RECT  99.168 0 99.192 0.084 ;
    END
  END cfg_data[47]
  PIN cfg_data[48]
    DIRECTION OUTPUT ;
    USE SIGNAL ;
    PORT
      LAYER M5 ;
        RECT  99.264 0 99.288 0.084 ;
    END
  END cfg_data[48]
  PIN cfg_data[49]
    DIRECTION OUTPUT ;
    USE SIGNAL ;
    PORT
      LAYER M5 ;
        RECT  99.36 0 99.384 0.084 ;
    END
  END cfg_data[49]
  PIN cfg_data[4]
    DIRECTION OUTPUT ;
    USE SIGNAL ;
    PORT
      LAYER M5 ;
        RECT  95.04 0 95.064 0.084 ;
    END
  END cfg_data[4]
  PIN cfg_data[50]
    DIRECTION OUTPUT ;
    USE SIGNAL ;
    PORT
      LAYER M5 ;
        RECT  99.456 0 99.48 0.084 ;
    END
  END cfg_data[50]
  PIN cfg_data[51]
    DIRECTION OUTPUT ;
    USE SIGNAL ;
    PORT
      LAYER M5 ;
        RECT  99.552 0 99.576 0.084 ;
    END
  END cfg_data[51]
  PIN cfg_data[52]
    DIRECTION OUTPUT ;
    USE SIGNAL ;
    PORT
      LAYER M5 ;
        RECT  99.648 0 99.672 0.084 ;
    END
  END cfg_data[52]
  PIN cfg_data[53]
    DIRECTION OUTPUT ;
    USE SIGNAL ;
    PORT
      LAYER M5 ;
        RECT  99.744 0 99.768 0.084 ;
    END
  END cfg_data[53]
  PIN cfg_data[54]
    DIRECTION OUTPUT ;
    USE SIGNAL ;
    PORT
      LAYER M5 ;
        RECT  99.84 0 99.864 0.084 ;
    END
  END cfg_data[54]
  PIN cfg_data[55]
    DIRECTION OUTPUT ;
    USE SIGNAL ;
    PORT
      LAYER M5 ;
        RECT  99.936 0 99.96 0.084 ;
    END
  END cfg_data[55]
  PIN cfg_data[56]
    DIRECTION OUTPUT ;
    USE SIGNAL ;
    PORT
      LAYER M5 ;
        RECT  100.032 0 100.056 0.084 ;
    END
  END cfg_data[56]
  PIN cfg_data[57]
    DIRECTION OUTPUT ;
    USE SIGNAL ;
    PORT
      LAYER M5 ;
        RECT  100.128 0 100.152 0.084 ;
    END
  END cfg_data[57]
  PIN cfg_data[58]
    DIRECTION OUTPUT ;
    USE SIGNAL ;
    PORT
      LAYER M5 ;
        RECT  100.224 0 100.248 0.084 ;
    END
  END cfg_data[58]
  PIN cfg_data[59]
    DIRECTION OUTPUT ;
    USE SIGNAL ;
    PORT
      LAYER M5 ;
        RECT  100.32 0 100.344 0.084 ;
    END
  END cfg_data[59]
  PIN cfg_data[5]
    DIRECTION OUTPUT ;
    USE SIGNAL ;
    PORT
      LAYER M5 ;
        RECT  95.136 0 95.16 0.084 ;
    END
  END cfg_data[5]
  PIN cfg_data[60]
    DIRECTION OUTPUT ;
    USE SIGNAL ;
    PORT
      LAYER M5 ;
        RECT  100.416 0 100.44 0.084 ;
    END
  END cfg_data[60]
  PIN cfg_data[61]
    DIRECTION OUTPUT ;
    USE SIGNAL ;
    PORT
      LAYER M5 ;
        RECT  100.512 0 100.536 0.084 ;
    END
  END cfg_data[61]
  PIN cfg_data[62]
    DIRECTION OUTPUT ;
    USE SIGNAL ;
    PORT
      LAYER M5 ;
        RECT  100.608 0 100.632 0.084 ;
    END
  END cfg_data[62]
  PIN cfg_data[63]
    DIRECTION OUTPUT ;
    USE SIGNAL ;
    PORT
      LAYER M5 ;
        RECT  100.704 0 100.728 0.084 ;
    END
  END cfg_data[63]
  PIN cfg_data[64]
    DIRECTION OUTPUT ;
    USE SIGNAL ;
    PORT
      LAYER M5 ;
        RECT  100.8 0 100.824 0.084 ;
    END
  END cfg_data[64]
  PIN cfg_data[65]
    DIRECTION OUTPUT ;
    USE SIGNAL ;
    PORT
      LAYER M5 ;
        RECT  100.896 0 100.92 0.084 ;
    END
  END cfg_data[65]
  PIN cfg_data[66]
    DIRECTION OUTPUT ;
    USE SIGNAL ;
    PORT
      LAYER M5 ;
        RECT  100.992 0 101.016 0.084 ;
    END
  END cfg_data[66]
  PIN cfg_data[67]
    DIRECTION OUTPUT ;
    USE SIGNAL ;
    PORT
      LAYER M5 ;
        RECT  101.088 0 101.112 0.084 ;
    END
  END cfg_data[67]
  PIN cfg_data[68]
    DIRECTION OUTPUT ;
    USE SIGNAL ;
    PORT
      LAYER M5 ;
        RECT  101.184 0 101.208 0.084 ;
    END
  END cfg_data[68]
  PIN cfg_data[69]
    DIRECTION OUTPUT ;
    USE SIGNAL ;
    PORT
      LAYER M5 ;
        RECT  101.28 0 101.304 0.084 ;
    END
  END cfg_data[69]
  PIN cfg_data[6]
    DIRECTION OUTPUT ;
    USE SIGNAL ;
    PORT
      LAYER M5 ;
        RECT  95.232 0 95.256 0.084 ;
    END
  END cfg_data[6]
  PIN cfg_data[70]
    DIRECTION OUTPUT ;
    USE SIGNAL ;
    PORT
      LAYER M5 ;
        RECT  101.376 0 101.4 0.084 ;
    END
  END cfg_data[70]
  PIN cfg_data[71]
    DIRECTION OUTPUT ;
    USE SIGNAL ;
    PORT
      LAYER M5 ;
        RECT  101.472 0 101.496 0.084 ;
    END
  END cfg_data[71]
  PIN cfg_data[72]
    DIRECTION OUTPUT ;
    USE SIGNAL ;
    PORT
      LAYER M5 ;
        RECT  101.568 0 101.592 0.084 ;
    END
  END cfg_data[72]
  PIN cfg_data[73]
    DIRECTION OUTPUT ;
    USE SIGNAL ;
    PORT
      LAYER M5 ;
        RECT  101.664 0 101.688 0.084 ;
    END
  END cfg_data[73]
  PIN cfg_data[74]
    DIRECTION OUTPUT ;
    USE SIGNAL ;
    PORT
      LAYER M5 ;
        RECT  101.76 0 101.784 0.084 ;
    END
  END cfg_data[74]
  PIN cfg_data[75]
    DIRECTION OUTPUT ;
    USE SIGNAL ;
    PORT
      LAYER M5 ;
        RECT  101.856 0 101.88 0.084 ;
    END
  END cfg_data[75]
  PIN cfg_data[76]
    DIRECTION OUTPUT ;
    USE SIGNAL ;
    PORT
      LAYER M5 ;
        RECT  101.952 0 101.976 0.084 ;
    END
  END cfg_data[76]
  PIN cfg_data[77]
    DIRECTION OUTPUT ;
    USE SIGNAL ;
    PORT
      LAYER M5 ;
        RECT  102.048 0 102.072 0.084 ;
    END
  END cfg_data[77]
  PIN cfg_data[78]
    DIRECTION OUTPUT ;
    USE SIGNAL ;
    PORT
      LAYER M5 ;
        RECT  102.144 0 102.168 0.084 ;
    END
  END cfg_data[78]
  PIN cfg_data[79]
    DIRECTION OUTPUT ;
    USE SIGNAL ;
    PORT
      LAYER M5 ;
        RECT  102.24 0 102.264 0.084 ;
    END
  END cfg_data[79]
  PIN cfg_data[7]
    DIRECTION OUTPUT ;
    USE SIGNAL ;
    PORT
      LAYER M5 ;
        RECT  95.328 0 95.352 0.084 ;
    END
  END cfg_data[7]
  PIN cfg_data[80]
    DIRECTION OUTPUT ;
    USE SIGNAL ;
    PORT
      LAYER M5 ;
        RECT  102.336 0 102.36 0.084 ;
    END
  END cfg_data[80]
  PIN cfg_data[81]
    DIRECTION OUTPUT ;
    USE SIGNAL ;
    PORT
      LAYER M5 ;
        RECT  102.432 0 102.456 0.084 ;
    END
  END cfg_data[81]
  PIN cfg_data[82]
    DIRECTION OUTPUT ;
    USE SIGNAL ;
    PORT
      LAYER M5 ;
        RECT  102.528 0 102.552 0.084 ;
    END
  END cfg_data[82]
  PIN cfg_data[83]
    DIRECTION OUTPUT ;
    USE SIGNAL ;
    PORT
      LAYER M5 ;
        RECT  102.624 0 102.648 0.084 ;
    END
  END cfg_data[83]
  PIN cfg_data[84]
    DIRECTION OUTPUT ;
    USE SIGNAL ;
    PORT
      LAYER M5 ;
        RECT  102.72 0 102.744 0.084 ;
    END
  END cfg_data[84]
  PIN cfg_data[85]
    DIRECTION OUTPUT ;
    USE SIGNAL ;
    PORT
      LAYER M5 ;
        RECT  102.816 0 102.84 0.084 ;
    END
  END cfg_data[85]
  PIN cfg_data[86]
    DIRECTION OUTPUT ;
    USE SIGNAL ;
    PORT
      LAYER M5 ;
        RECT  102.912 0 102.936 0.084 ;
    END
  END cfg_data[86]
  PIN cfg_data[87]
    DIRECTION OUTPUT ;
    USE SIGNAL ;
    PORT
      LAYER M5 ;
        RECT  103.008 0 103.032 0.084 ;
    END
  END cfg_data[87]
  PIN cfg_data[88]
    DIRECTION OUTPUT ;
    USE SIGNAL ;
    PORT
      LAYER M5 ;
        RECT  103.104 0 103.128 0.084 ;
    END
  END cfg_data[88]
  PIN cfg_data[89]
    DIRECTION OUTPUT ;
    USE SIGNAL ;
    PORT
      LAYER M5 ;
        RECT  103.2 0 103.224 0.084 ;
    END
  END cfg_data[89]
  PIN cfg_data[8]
    DIRECTION OUTPUT ;
    USE SIGNAL ;
    PORT
      LAYER M5 ;
        RECT  95.424 0 95.448 0.084 ;
    END
  END cfg_data[8]
  PIN cfg_data[90]
    DIRECTION OUTPUT ;
    USE SIGNAL ;
    PORT
      LAYER M5 ;
        RECT  103.296 0 103.32 0.084 ;
    END
  END cfg_data[90]
  PIN cfg_data[91]
    DIRECTION OUTPUT ;
    USE SIGNAL ;
    PORT
      LAYER M5 ;
        RECT  103.392 0 103.416 0.084 ;
    END
  END cfg_data[91]
  PIN cfg_data[92]
    DIRECTION OUTPUT ;
    USE SIGNAL ;
    PORT
      LAYER M5 ;
        RECT  103.488 0 103.512 0.084 ;
    END
  END cfg_data[92]
  PIN cfg_data[93]
    DIRECTION OUTPUT ;
    USE SIGNAL ;
    PORT
      LAYER M5 ;
        RECT  103.584 0 103.608 0.084 ;
    END
  END cfg_data[93]
  PIN cfg_data[94]
    DIRECTION OUTPUT ;
    USE SIGNAL ;
    PORT
      LAYER M5 ;
        RECT  103.68 0 103.704 0.084 ;
    END
  END cfg_data[94]
  PIN cfg_data[95]
    DIRECTION OUTPUT ;
    USE SIGNAL ;
    PORT
      LAYER M5 ;
        RECT  103.776 0 103.8 0.084 ;
    END
  END cfg_data[95]
  PIN cfg_data[96]
    DIRECTION OUTPUT ;
    USE SIGNAL ;
    PORT
      LAYER M5 ;
        RECT  103.872 0 103.896 0.084 ;
    END
  END cfg_data[96]
  PIN cfg_data[97]
    DIRECTION OUTPUT ;
    USE SIGNAL ;
    PORT
      LAYER M5 ;
        RECT  103.968 0 103.992 0.084 ;
    END
  END cfg_data[97]
  PIN cfg_data[98]
    DIRECTION OUTPUT ;
    USE SIGNAL ;
    PORT
      LAYER M5 ;
        RECT  104.064 0 104.088 0.084 ;
    END
  END cfg_data[98]
  PIN cfg_data[99]
    DIRECTION OUTPUT ;
    USE SIGNAL ;
    PORT
      LAYER M5 ;
        RECT  104.16 0 104.184 0.084 ;
    END
  END cfg_data[99]
  PIN cfg_data[9]
    DIRECTION OUTPUT ;
    USE SIGNAL ;
    PORT
      LAYER M5 ;
        RECT  95.52 0 95.544 0.084 ;
    END
  END cfg_data[9]
  PIN cfg_target[0]
    DIRECTION OUTPUT ;
    USE SIGNAL ;
    PORT
      LAYER M5 ;
        RECT  92.736 0 92.76 0.084 ;
    END
  END cfg_target[0]
  PIN cfg_target[1]
    DIRECTION OUTPUT ;
    USE SIGNAL ;
    PORT
      LAYER M5 ;
        RECT  92.832 0 92.856 0.084 ;
    END
  END cfg_target[1]
  PIN cfg_target[2]
    DIRECTION OUTPUT ;
    USE SIGNAL ;
    PORT
      LAYER M5 ;
        RECT  92.928 0 92.952 0.084 ;
    END
  END cfg_target[2]
  PIN cfg_target[3]
    DIRECTION OUTPUT ;
    USE SIGNAL ;
    PORT
      LAYER M5 ;
        RECT  93.024 0 93.048 0.084 ;
    END
  END cfg_target[3]
  PIN cfg_target[4]
    DIRECTION OUTPUT ;
    USE SIGNAL ;
    PORT
      LAYER M5 ;
        RECT  93.12 0 93.144 0.084 ;
    END
  END cfg_target[4]
  PIN cfg_target[5]
    DIRECTION OUTPUT ;
    USE SIGNAL ;
    PORT
      LAYER M5 ;
        RECT  93.216 0 93.24 0.084 ;
    END
  END cfg_target[5]
  PIN cfg_target[6]
    DIRECTION OUTPUT ;
    USE SIGNAL ;
    PORT
      LAYER M5 ;
        RECT  93.312 0 93.336 0.084 ;
    END
  END cfg_target[6]
  PIN cfg_target[7]
    DIRECTION OUTPUT ;
    USE SIGNAL ;
    PORT
      LAYER M5 ;
        RECT  93.408 0 93.432 0.084 ;
    END
  END cfg_target[7]
  PIN cfg_v
    DIRECTION OUTPUT ;
    USE SIGNAL ;
    PORT
      LAYER M5 ;
        RECT  92.64 0 92.664 0.084 ;
    END
  END cfg_v
  PIN clk
    DIRECTION INPUT ;
    USE SIGNAL ;
    PORT
      LAYER M5 ;
        RECT  107.808 215.916 107.832 216 ;
    END
  END clk
  PIN desc_base[0]
    DIRECTION OUTPUT ;
    USE SIGNAL ;
    PORT
      LAYER M5 ;
        RECT  119.328 0 119.352 0.084 ;
    END
  END desc_base[0]
  PIN desc_base[10]
    DIRECTION OUTPUT ;
    USE SIGNAL ;
    PORT
      LAYER M5 ;
        RECT  120.288 0 120.312 0.084 ;
    END
  END desc_base[10]
  PIN desc_base[11]
    DIRECTION OUTPUT ;
    USE SIGNAL ;
    PORT
      LAYER M5 ;
        RECT  120.384 0 120.408 0.084 ;
    END
  END desc_base[11]
  PIN desc_base[1]
    DIRECTION OUTPUT ;
    USE SIGNAL ;
    PORT
      LAYER M5 ;
        RECT  119.424 0 119.448 0.084 ;
    END
  END desc_base[1]
  PIN desc_base[2]
    DIRECTION OUTPUT ;
    USE SIGNAL ;
    PORT
      LAYER M5 ;
        RECT  119.52 0 119.544 0.084 ;
    END
  END desc_base[2]
  PIN desc_base[3]
    DIRECTION OUTPUT ;
    USE SIGNAL ;
    PORT
      LAYER M5 ;
        RECT  119.616 0 119.64 0.084 ;
    END
  END desc_base[3]
  PIN desc_base[4]
    DIRECTION OUTPUT ;
    USE SIGNAL ;
    PORT
      LAYER M5 ;
        RECT  119.712 0 119.736 0.084 ;
    END
  END desc_base[4]
  PIN desc_base[5]
    DIRECTION OUTPUT ;
    USE SIGNAL ;
    PORT
      LAYER M5 ;
        RECT  119.808 0 119.832 0.084 ;
    END
  END desc_base[5]
  PIN desc_base[6]
    DIRECTION OUTPUT ;
    USE SIGNAL ;
    PORT
      LAYER M5 ;
        RECT  119.904 0 119.928 0.084 ;
    END
  END desc_base[6]
  PIN desc_base[7]
    DIRECTION OUTPUT ;
    USE SIGNAL ;
    PORT
      LAYER M5 ;
        RECT  120 0 120.024 0.084 ;
    END
  END desc_base[7]
  PIN desc_base[8]
    DIRECTION OUTPUT ;
    USE SIGNAL ;
    PORT
      LAYER M5 ;
        RECT  120.096 0 120.12 0.084 ;
    END
  END desc_base[8]
  PIN desc_base[9]
    DIRECTION OUTPUT ;
    USE SIGNAL ;
    PORT
      LAYER M5 ;
        RECT  120.192 0 120.216 0.084 ;
    END
  END desc_base[9]
  PIN desc_limit[0]
    DIRECTION OUTPUT ;
    USE SIGNAL ;
    PORT
      LAYER M5 ;
        RECT  120.48 0 120.504 0.084 ;
    END
  END desc_limit[0]
  PIN desc_limit[10]
    DIRECTION OUTPUT ;
    USE SIGNAL ;
    PORT
      LAYER M5 ;
        RECT  121.44 0 121.464 0.084 ;
    END
  END desc_limit[10]
  PIN desc_limit[11]
    DIRECTION OUTPUT ;
    USE SIGNAL ;
    PORT
      LAYER M5 ;
        RECT  121.536 0 121.56 0.084 ;
    END
  END desc_limit[11]
  PIN desc_limit[12]
    DIRECTION OUTPUT ;
    USE SIGNAL ;
    PORT
      LAYER M5 ;
        RECT  121.632 0 121.656 0.084 ;
    END
  END desc_limit[12]
  PIN desc_limit[1]
    DIRECTION OUTPUT ;
    USE SIGNAL ;
    PORT
      LAYER M5 ;
        RECT  120.576 0 120.6 0.084 ;
    END
  END desc_limit[1]
  PIN desc_limit[2]
    DIRECTION OUTPUT ;
    USE SIGNAL ;
    PORT
      LAYER M5 ;
        RECT  120.672 0 120.696 0.084 ;
    END
  END desc_limit[2]
  PIN desc_limit[3]
    DIRECTION OUTPUT ;
    USE SIGNAL ;
    PORT
      LAYER M5 ;
        RECT  120.768 0 120.792 0.084 ;
    END
  END desc_limit[3]
  PIN desc_limit[4]
    DIRECTION OUTPUT ;
    USE SIGNAL ;
    PORT
      LAYER M5 ;
        RECT  120.864 0 120.888 0.084 ;
    END
  END desc_limit[4]
  PIN desc_limit[5]
    DIRECTION OUTPUT ;
    USE SIGNAL ;
    PORT
      LAYER M5 ;
        RECT  120.96 0 120.984 0.084 ;
    END
  END desc_limit[5]
  PIN desc_limit[6]
    DIRECTION OUTPUT ;
    USE SIGNAL ;
    PORT
      LAYER M5 ;
        RECT  121.056 0 121.08 0.084 ;
    END
  END desc_limit[6]
  PIN desc_limit[7]
    DIRECTION OUTPUT ;
    USE SIGNAL ;
    PORT
      LAYER M5 ;
        RECT  121.152 0 121.176 0.084 ;
    END
  END desc_limit[7]
  PIN desc_limit[8]
    DIRECTION OUTPUT ;
    USE SIGNAL ;
    PORT
      LAYER M5 ;
        RECT  121.248 0 121.272 0.084 ;
    END
  END desc_limit[8]
  PIN desc_limit[9]
    DIRECTION OUTPUT ;
    USE SIGNAL ;
    PORT
      LAYER M5 ;
        RECT  121.344 0 121.368 0.084 ;
    END
  END desc_limit[9]
  PIN desc_loops[0]
    DIRECTION OUTPUT ;
    USE SIGNAL ;
    PORT
      LAYER M5 ;
        RECT  121.728 0 121.752 0.084 ;
    END
  END desc_loops[0]
  PIN desc_loops[10]
    DIRECTION OUTPUT ;
    USE SIGNAL ;
    PORT
      LAYER M5 ;
        RECT  122.688 0 122.712 0.084 ;
    END
  END desc_loops[10]
  PIN desc_loops[11]
    DIRECTION OUTPUT ;
    USE SIGNAL ;
    PORT
      LAYER M5 ;
        RECT  122.784 0 122.808 0.084 ;
    END
  END desc_loops[11]
  PIN desc_loops[12]
    DIRECTION OUTPUT ;
    USE SIGNAL ;
    PORT
      LAYER M5 ;
        RECT  122.88 0 122.904 0.084 ;
    END
  END desc_loops[12]
  PIN desc_loops[13]
    DIRECTION OUTPUT ;
    USE SIGNAL ;
    PORT
      LAYER M5 ;
        RECT  122.976 0 123 0.084 ;
    END
  END desc_loops[13]
  PIN desc_loops[14]
    DIRECTION OUTPUT ;
    USE SIGNAL ;
    PORT
      LAYER M5 ;
        RECT  123.072 0 123.096 0.084 ;
    END
  END desc_loops[14]
  PIN desc_loops[15]
    DIRECTION OUTPUT ;
    USE SIGNAL ;
    PORT
      LAYER M5 ;
        RECT  123.168 0 123.192 0.084 ;
    END
  END desc_loops[15]
  PIN desc_loops[1]
    DIRECTION OUTPUT ;
    USE SIGNAL ;
    PORT
      LAYER M5 ;
        RECT  121.824 0 121.848 0.084 ;
    END
  END desc_loops[1]
  PIN desc_loops[2]
    DIRECTION OUTPUT ;
    USE SIGNAL ;
    PORT
      LAYER M5 ;
        RECT  121.92 0 121.944 0.084 ;
    END
  END desc_loops[2]
  PIN desc_loops[3]
    DIRECTION OUTPUT ;
    USE SIGNAL ;
    PORT
      LAYER M5 ;
        RECT  122.016 0 122.04 0.084 ;
    END
  END desc_loops[3]
  PIN desc_loops[4]
    DIRECTION OUTPUT ;
    USE SIGNAL ;
    PORT
      LAYER M5 ;
        RECT  122.112 0 122.136 0.084 ;
    END
  END desc_loops[4]
  PIN desc_loops[5]
    DIRECTION OUTPUT ;
    USE SIGNAL ;
    PORT
      LAYER M5 ;
        RECT  122.208 0 122.232 0.084 ;
    END
  END desc_loops[5]
  PIN desc_loops[6]
    DIRECTION OUTPUT ;
    USE SIGNAL ;
    PORT
      LAYER M5 ;
        RECT  122.304 0 122.328 0.084 ;
    END
  END desc_loops[6]
  PIN desc_loops[7]
    DIRECTION OUTPUT ;
    USE SIGNAL ;
    PORT
      LAYER M5 ;
        RECT  122.4 0 122.424 0.084 ;
    END
  END desc_loops[7]
  PIN desc_loops[8]
    DIRECTION OUTPUT ;
    USE SIGNAL ;
    PORT
      LAYER M5 ;
        RECT  122.496 0 122.52 0.084 ;
    END
  END desc_loops[8]
  PIN desc_loops[9]
    DIRECTION OUTPUT ;
    USE SIGNAL ;
    PORT
      LAYER M5 ;
        RECT  122.592 0 122.616 0.084 ;
    END
  END desc_loops[9]
  PIN desc_v
    DIRECTION OUTPUT ;
    USE SIGNAL ;
    PORT
      LAYER M5 ;
        RECT  119.232 0 119.256 0.084 ;
    END
  END desc_v
  PIN fault
    DIRECTION OUTPUT ;
    USE SIGNAL ;
    PORT
      LAYER M5 ;
        RECT  123.36 0 123.384 0.084 ;
    END
  END fault
  PIN launch_v
    DIRECTION OUTPUT ;
    USE SIGNAL ;
    PORT
      LAYER M5 ;
        RECT  123.264 0 123.288 0.084 ;
    END
  END launch_v
  PIN program_active
    DIRECTION INPUT ;
    USE SIGNAL ;
    PORT
      LAYER M5 ;
        RECT  108.096 215.916 108.12 216 ;
    END
  END program_active
  PIN program_fault
    DIRECTION INPUT ;
    USE SIGNAL ;
    PORT
      LAYER M5 ;
        RECT  108.192 215.916 108.216 216 ;
    END
  END program_fault
  PIN rst_n
    DIRECTION INPUT ;
    USE SIGNAL ;
    PORT
      LAYER M5 ;
        RECT  107.904 215.916 107.928 216 ;
    END
  END rst_n
  PIN s_araddr[0]
    DIRECTION INPUT ;
    USE SIGNAL ;
    PORT
      LAYER M4 ;
        RECT  0 108.624 0.084 108.648 ;
    END
  END s_araddr[0]
  PIN s_araddr[10]
    DIRECTION INPUT ;
    USE SIGNAL ;
    PORT
      LAYER M4 ;
        RECT  0 109.584 0.084 109.608 ;
    END
  END s_araddr[10]
  PIN s_araddr[11]
    DIRECTION INPUT ;
    USE SIGNAL ;
    PORT
      LAYER M4 ;
        RECT  0 109.68 0.084 109.704 ;
    END
  END s_araddr[11]
  PIN s_araddr[1]
    DIRECTION INPUT ;
    USE SIGNAL ;
    PORT
      LAYER M4 ;
        RECT  0 108.72 0.084 108.744 ;
    END
  END s_araddr[1]
  PIN s_araddr[2]
    DIRECTION INPUT ;
    USE SIGNAL ;
    PORT
      LAYER M4 ;
        RECT  0 108.816 0.084 108.84 ;
    END
  END s_araddr[2]
  PIN s_araddr[3]
    DIRECTION INPUT ;
    USE SIGNAL ;
    PORT
      LAYER M4 ;
        RECT  0 108.912 0.084 108.936 ;
    END
  END s_araddr[3]
  PIN s_araddr[4]
    DIRECTION INPUT ;
    USE SIGNAL ;
    PORT
      LAYER M4 ;
        RECT  0 109.008 0.084 109.032 ;
    END
  END s_araddr[4]
  PIN s_araddr[5]
    DIRECTION INPUT ;
    USE SIGNAL ;
    PORT
      LAYER M4 ;
        RECT  0 109.104 0.084 109.128 ;
    END
  END s_araddr[5]
  PIN s_araddr[6]
    DIRECTION INPUT ;
    USE SIGNAL ;
    PORT
      LAYER M4 ;
        RECT  0 109.2 0.084 109.224 ;
    END
  END s_araddr[6]
  PIN s_araddr[7]
    DIRECTION INPUT ;
    USE SIGNAL ;
    PORT
      LAYER M4 ;
        RECT  0 109.296 0.084 109.32 ;
    END
  END s_araddr[7]
  PIN s_araddr[8]
    DIRECTION INPUT ;
    USE SIGNAL ;
    PORT
      LAYER M4 ;
        RECT  0 109.392 0.084 109.416 ;
    END
  END s_araddr[8]
  PIN s_araddr[9]
    DIRECTION INPUT ;
    USE SIGNAL ;
    PORT
      LAYER M4 ;
        RECT  0 109.488 0.084 109.512 ;
    END
  END s_araddr[9]
  PIN s_arready
    DIRECTION OUTPUT ;
    USE SIGNAL ;
    PORT
      LAYER M4 ;
        RECT  0 108.528 0.084 108.552 ;
    END
  END s_arready
  PIN s_arvalid
    DIRECTION INPUT ;
    USE SIGNAL ;
    PORT
      LAYER M4 ;
        RECT  0 108.432 0.084 108.456 ;
    END
  END s_arvalid
  PIN s_awaddr[0]
    DIRECTION INPUT ;
    USE SIGNAL ;
    PORT
      LAYER M4 ;
        RECT  0 103.248 0.084 103.272 ;
    END
  END s_awaddr[0]
  PIN s_awaddr[10]
    DIRECTION INPUT ;
    USE SIGNAL ;
    PORT
      LAYER M4 ;
        RECT  0 104.208 0.084 104.232 ;
    END
  END s_awaddr[10]
  PIN s_awaddr[11]
    DIRECTION INPUT ;
    USE SIGNAL ;
    PORT
      LAYER M4 ;
        RECT  0 104.304 0.084 104.328 ;
    END
  END s_awaddr[11]
  PIN s_awaddr[1]
    DIRECTION INPUT ;
    USE SIGNAL ;
    PORT
      LAYER M4 ;
        RECT  0 103.344 0.084 103.368 ;
    END
  END s_awaddr[1]
  PIN s_awaddr[2]
    DIRECTION INPUT ;
    USE SIGNAL ;
    PORT
      LAYER M4 ;
        RECT  0 103.44 0.084 103.464 ;
    END
  END s_awaddr[2]
  PIN s_awaddr[3]
    DIRECTION INPUT ;
    USE SIGNAL ;
    PORT
      LAYER M4 ;
        RECT  0 103.536 0.084 103.56 ;
    END
  END s_awaddr[3]
  PIN s_awaddr[4]
    DIRECTION INPUT ;
    USE SIGNAL ;
    PORT
      LAYER M4 ;
        RECT  0 103.632 0.084 103.656 ;
    END
  END s_awaddr[4]
  PIN s_awaddr[5]
    DIRECTION INPUT ;
    USE SIGNAL ;
    PORT
      LAYER M4 ;
        RECT  0 103.728 0.084 103.752 ;
    END
  END s_awaddr[5]
  PIN s_awaddr[6]
    DIRECTION INPUT ;
    USE SIGNAL ;
    PORT
      LAYER M4 ;
        RECT  0 103.824 0.084 103.848 ;
    END
  END s_awaddr[6]
  PIN s_awaddr[7]
    DIRECTION INPUT ;
    USE SIGNAL ;
    PORT
      LAYER M4 ;
        RECT  0 103.92 0.084 103.944 ;
    END
  END s_awaddr[7]
  PIN s_awaddr[8]
    DIRECTION INPUT ;
    USE SIGNAL ;
    PORT
      LAYER M4 ;
        RECT  0 104.016 0.084 104.04 ;
    END
  END s_awaddr[8]
  PIN s_awaddr[9]
    DIRECTION INPUT ;
    USE SIGNAL ;
    PORT
      LAYER M4 ;
        RECT  0 104.112 0.084 104.136 ;
    END
  END s_awaddr[9]
  PIN s_awready
    DIRECTION OUTPUT ;
    USE SIGNAL ;
    PORT
      LAYER M4 ;
        RECT  0 103.152 0.084 103.176 ;
    END
  END s_awready
  PIN s_awvalid
    DIRECTION INPUT ;
    USE SIGNAL ;
    PORT
      LAYER M4 ;
        RECT  0 103.056 0.084 103.08 ;
    END
  END s_awvalid
  PIN s_bready
    DIRECTION INPUT ;
    USE SIGNAL ;
    PORT
      LAYER M4 ;
        RECT  0 108.144 0.084 108.168 ;
    END
  END s_bready
  PIN s_bresp[0]
    DIRECTION OUTPUT ;
    USE SIGNAL ;
    PORT
      LAYER M4 ;
        RECT  0 108.24 0.084 108.264 ;
    END
  END s_bresp[0]
  PIN s_bresp[1]
    DIRECTION OUTPUT ;
    USE SIGNAL ;
    PORT
      LAYER M4 ;
        RECT  0 108.336 0.084 108.36 ;
    END
  END s_bresp[1]
  PIN s_bvalid
    DIRECTION OUTPUT ;
    USE SIGNAL ;
    PORT
      LAYER M4 ;
        RECT  0 108.048 0.084 108.072 ;
    END
  END s_bvalid
  PIN s_rdata[0]
    DIRECTION OUTPUT ;
    USE SIGNAL ;
    PORT
      LAYER M4 ;
        RECT  0 109.968 0.084 109.992 ;
    END
  END s_rdata[0]
  PIN s_rdata[10]
    DIRECTION OUTPUT ;
    USE SIGNAL ;
    PORT
      LAYER M4 ;
        RECT  0 110.928 0.084 110.952 ;
    END
  END s_rdata[10]
  PIN s_rdata[11]
    DIRECTION OUTPUT ;
    USE SIGNAL ;
    PORT
      LAYER M4 ;
        RECT  0 111.024 0.084 111.048 ;
    END
  END s_rdata[11]
  PIN s_rdata[12]
    DIRECTION OUTPUT ;
    USE SIGNAL ;
    PORT
      LAYER M4 ;
        RECT  0 111.12 0.084 111.144 ;
    END
  END s_rdata[12]
  PIN s_rdata[13]
    DIRECTION OUTPUT ;
    USE SIGNAL ;
    PORT
      LAYER M4 ;
        RECT  0 111.216 0.084 111.24 ;
    END
  END s_rdata[13]
  PIN s_rdata[14]
    DIRECTION OUTPUT ;
    USE SIGNAL ;
    PORT
      LAYER M4 ;
        RECT  0 111.312 0.084 111.336 ;
    END
  END s_rdata[14]
  PIN s_rdata[15]
    DIRECTION OUTPUT ;
    USE SIGNAL ;
    PORT
      LAYER M4 ;
        RECT  0 111.408 0.084 111.432 ;
    END
  END s_rdata[15]
  PIN s_rdata[16]
    DIRECTION OUTPUT ;
    USE SIGNAL ;
    PORT
      LAYER M4 ;
        RECT  0 111.504 0.084 111.528 ;
    END
  END s_rdata[16]
  PIN s_rdata[17]
    DIRECTION OUTPUT ;
    USE SIGNAL ;
    PORT
      LAYER M4 ;
        RECT  0 111.6 0.084 111.624 ;
    END
  END s_rdata[17]
  PIN s_rdata[18]
    DIRECTION OUTPUT ;
    USE SIGNAL ;
    PORT
      LAYER M4 ;
        RECT  0 111.696 0.084 111.72 ;
    END
  END s_rdata[18]
  PIN s_rdata[19]
    DIRECTION OUTPUT ;
    USE SIGNAL ;
    PORT
      LAYER M4 ;
        RECT  0 111.792 0.084 111.816 ;
    END
  END s_rdata[19]
  PIN s_rdata[1]
    DIRECTION OUTPUT ;
    USE SIGNAL ;
    PORT
      LAYER M4 ;
        RECT  0 110.064 0.084 110.088 ;
    END
  END s_rdata[1]
  PIN s_rdata[20]
    DIRECTION OUTPUT ;
    USE SIGNAL ;
    PORT
      LAYER M4 ;
        RECT  0 111.888 0.084 111.912 ;
    END
  END s_rdata[20]
  PIN s_rdata[21]
    DIRECTION OUTPUT ;
    USE SIGNAL ;
    PORT
      LAYER M4 ;
        RECT  0 111.984 0.084 112.008 ;
    END
  END s_rdata[21]
  PIN s_rdata[22]
    DIRECTION OUTPUT ;
    USE SIGNAL ;
    PORT
      LAYER M4 ;
        RECT  0 112.08 0.084 112.104 ;
    END
  END s_rdata[22]
  PIN s_rdata[23]
    DIRECTION OUTPUT ;
    USE SIGNAL ;
    PORT
      LAYER M4 ;
        RECT  0 112.176 0.084 112.2 ;
    END
  END s_rdata[23]
  PIN s_rdata[24]
    DIRECTION OUTPUT ;
    USE SIGNAL ;
    PORT
      LAYER M4 ;
        RECT  0 112.272 0.084 112.296 ;
    END
  END s_rdata[24]
  PIN s_rdata[25]
    DIRECTION OUTPUT ;
    USE SIGNAL ;
    PORT
      LAYER M4 ;
        RECT  0 112.368 0.084 112.392 ;
    END
  END s_rdata[25]
  PIN s_rdata[26]
    DIRECTION OUTPUT ;
    USE SIGNAL ;
    PORT
      LAYER M4 ;
        RECT  0 112.464 0.084 112.488 ;
    END
  END s_rdata[26]
  PIN s_rdata[27]
    DIRECTION OUTPUT ;
    USE SIGNAL ;
    PORT
      LAYER M4 ;
        RECT  0 112.56 0.084 112.584 ;
    END
  END s_rdata[27]
  PIN s_rdata[28]
    DIRECTION OUTPUT ;
    USE SIGNAL ;
    PORT
      LAYER M4 ;
        RECT  0 112.656 0.084 112.68 ;
    END
  END s_rdata[28]
  PIN s_rdata[29]
    DIRECTION OUTPUT ;
    USE SIGNAL ;
    PORT
      LAYER M4 ;
        RECT  0 112.752 0.084 112.776 ;
    END
  END s_rdata[29]
  PIN s_rdata[2]
    DIRECTION OUTPUT ;
    USE SIGNAL ;
    PORT
      LAYER M4 ;
        RECT  0 110.16 0.084 110.184 ;
    END
  END s_rdata[2]
  PIN s_rdata[30]
    DIRECTION OUTPUT ;
    USE SIGNAL ;
    PORT
      LAYER M4 ;
        RECT  0 112.848 0.084 112.872 ;
    END
  END s_rdata[30]
  PIN s_rdata[31]
    DIRECTION OUTPUT ;
    USE SIGNAL ;
    PORT
      LAYER M4 ;
        RECT  0 112.944 0.084 112.968 ;
    END
  END s_rdata[31]
  PIN s_rdata[3]
    DIRECTION OUTPUT ;
    USE SIGNAL ;
    PORT
      LAYER M4 ;
        RECT  0 110.256 0.084 110.28 ;
    END
  END s_rdata[3]
  PIN s_rdata[4]
    DIRECTION OUTPUT ;
    USE SIGNAL ;
    PORT
      LAYER M4 ;
        RECT  0 110.352 0.084 110.376 ;
    END
  END s_rdata[4]
  PIN s_rdata[5]
    DIRECTION OUTPUT ;
    USE SIGNAL ;
    PORT
      LAYER M4 ;
        RECT  0 110.448 0.084 110.472 ;
    END
  END s_rdata[5]
  PIN s_rdata[6]
    DIRECTION OUTPUT ;
    USE SIGNAL ;
    PORT
      LAYER M4 ;
        RECT  0 110.544 0.084 110.568 ;
    END
  END s_rdata[6]
  PIN s_rdata[7]
    DIRECTION OUTPUT ;
    USE SIGNAL ;
    PORT
      LAYER M4 ;
        RECT  0 110.64 0.084 110.664 ;
    END
  END s_rdata[7]
  PIN s_rdata[8]
    DIRECTION OUTPUT ;
    USE SIGNAL ;
    PORT
      LAYER M4 ;
        RECT  0 110.736 0.084 110.76 ;
    END
  END s_rdata[8]
  PIN s_rdata[9]
    DIRECTION OUTPUT ;
    USE SIGNAL ;
    PORT
      LAYER M4 ;
        RECT  0 110.832 0.084 110.856 ;
    END
  END s_rdata[9]
  PIN s_rready
    DIRECTION INPUT ;
    USE SIGNAL ;
    PORT
      LAYER M4 ;
        RECT  0 109.872 0.084 109.896 ;
    END
  END s_rready
  PIN s_rvalid
    DIRECTION OUTPUT ;
    USE SIGNAL ;
    PORT
      LAYER M4 ;
        RECT  0 109.776 0.084 109.8 ;
    END
  END s_rvalid
  PIN s_wdata[0]
    DIRECTION INPUT ;
    USE SIGNAL ;
    PORT
      LAYER M4 ;
        RECT  0 104.592 0.084 104.616 ;
    END
  END s_wdata[0]
  PIN s_wdata[10]
    DIRECTION INPUT ;
    USE SIGNAL ;
    PORT
      LAYER M4 ;
        RECT  0 105.552 0.084 105.576 ;
    END
  END s_wdata[10]
  PIN s_wdata[11]
    DIRECTION INPUT ;
    USE SIGNAL ;
    PORT
      LAYER M4 ;
        RECT  0 105.648 0.084 105.672 ;
    END
  END s_wdata[11]
  PIN s_wdata[12]
    DIRECTION INPUT ;
    USE SIGNAL ;
    PORT
      LAYER M4 ;
        RECT  0 105.744 0.084 105.768 ;
    END
  END s_wdata[12]
  PIN s_wdata[13]
    DIRECTION INPUT ;
    USE SIGNAL ;
    PORT
      LAYER M4 ;
        RECT  0 105.84 0.084 105.864 ;
    END
  END s_wdata[13]
  PIN s_wdata[14]
    DIRECTION INPUT ;
    USE SIGNAL ;
    PORT
      LAYER M4 ;
        RECT  0 105.936 0.084 105.96 ;
    END
  END s_wdata[14]
  PIN s_wdata[15]
    DIRECTION INPUT ;
    USE SIGNAL ;
    PORT
      LAYER M4 ;
        RECT  0 106.032 0.084 106.056 ;
    END
  END s_wdata[15]
  PIN s_wdata[16]
    DIRECTION INPUT ;
    USE SIGNAL ;
    PORT
      LAYER M4 ;
        RECT  0 106.128 0.084 106.152 ;
    END
  END s_wdata[16]
  PIN s_wdata[17]
    DIRECTION INPUT ;
    USE SIGNAL ;
    PORT
      LAYER M4 ;
        RECT  0 106.224 0.084 106.248 ;
    END
  END s_wdata[17]
  PIN s_wdata[18]
    DIRECTION INPUT ;
    USE SIGNAL ;
    PORT
      LAYER M4 ;
        RECT  0 106.32 0.084 106.344 ;
    END
  END s_wdata[18]
  PIN s_wdata[19]
    DIRECTION INPUT ;
    USE SIGNAL ;
    PORT
      LAYER M4 ;
        RECT  0 106.416 0.084 106.44 ;
    END
  END s_wdata[19]
  PIN s_wdata[1]
    DIRECTION INPUT ;
    USE SIGNAL ;
    PORT
      LAYER M4 ;
        RECT  0 104.688 0.084 104.712 ;
    END
  END s_wdata[1]
  PIN s_wdata[20]
    DIRECTION INPUT ;
    USE SIGNAL ;
    PORT
      LAYER M4 ;
        RECT  0 106.512 0.084 106.536 ;
    END
  END s_wdata[20]
  PIN s_wdata[21]
    DIRECTION INPUT ;
    USE SIGNAL ;
    PORT
      LAYER M4 ;
        RECT  0 106.608 0.084 106.632 ;
    END
  END s_wdata[21]
  PIN s_wdata[22]
    DIRECTION INPUT ;
    USE SIGNAL ;
    PORT
      LAYER M4 ;
        RECT  0 106.704 0.084 106.728 ;
    END
  END s_wdata[22]
  PIN s_wdata[23]
    DIRECTION INPUT ;
    USE SIGNAL ;
    PORT
      LAYER M4 ;
        RECT  0 106.8 0.084 106.824 ;
    END
  END s_wdata[23]
  PIN s_wdata[24]
    DIRECTION INPUT ;
    USE SIGNAL ;
    PORT
      LAYER M4 ;
        RECT  0 106.896 0.084 106.92 ;
    END
  END s_wdata[24]
  PIN s_wdata[25]
    DIRECTION INPUT ;
    USE SIGNAL ;
    PORT
      LAYER M4 ;
        RECT  0 106.992 0.084 107.016 ;
    END
  END s_wdata[25]
  PIN s_wdata[26]
    DIRECTION INPUT ;
    USE SIGNAL ;
    PORT
      LAYER M4 ;
        RECT  0 107.088 0.084 107.112 ;
    END
  END s_wdata[26]
  PIN s_wdata[27]
    DIRECTION INPUT ;
    USE SIGNAL ;
    PORT
      LAYER M4 ;
        RECT  0 107.184 0.084 107.208 ;
    END
  END s_wdata[27]
  PIN s_wdata[28]
    DIRECTION INPUT ;
    USE SIGNAL ;
    PORT
      LAYER M4 ;
        RECT  0 107.28 0.084 107.304 ;
    END
  END s_wdata[28]
  PIN s_wdata[29]
    DIRECTION INPUT ;
    USE SIGNAL ;
    PORT
      LAYER M4 ;
        RECT  0 107.376 0.084 107.4 ;
    END
  END s_wdata[29]
  PIN s_wdata[2]
    DIRECTION INPUT ;
    USE SIGNAL ;
    PORT
      LAYER M4 ;
        RECT  0 104.784 0.084 104.808 ;
    END
  END s_wdata[2]
  PIN s_wdata[30]
    DIRECTION INPUT ;
    USE SIGNAL ;
    PORT
      LAYER M4 ;
        RECT  0 107.472 0.084 107.496 ;
    END
  END s_wdata[30]
  PIN s_wdata[31]
    DIRECTION INPUT ;
    USE SIGNAL ;
    PORT
      LAYER M4 ;
        RECT  0 107.568 0.084 107.592 ;
    END
  END s_wdata[31]
  PIN s_wdata[3]
    DIRECTION INPUT ;
    USE SIGNAL ;
    PORT
      LAYER M4 ;
        RECT  0 104.88 0.084 104.904 ;
    END
  END s_wdata[3]
  PIN s_wdata[4]
    DIRECTION INPUT ;
    USE SIGNAL ;
    PORT
      LAYER M4 ;
        RECT  0 104.976 0.084 105 ;
    END
  END s_wdata[4]
  PIN s_wdata[5]
    DIRECTION INPUT ;
    USE SIGNAL ;
    PORT
      LAYER M4 ;
        RECT  0 105.072 0.084 105.096 ;
    END
  END s_wdata[5]
  PIN s_wdata[6]
    DIRECTION INPUT ;
    USE SIGNAL ;
    PORT
      LAYER M4 ;
        RECT  0 105.168 0.084 105.192 ;
    END
  END s_wdata[6]
  PIN s_wdata[7]
    DIRECTION INPUT ;
    USE SIGNAL ;
    PORT
      LAYER M4 ;
        RECT  0 105.264 0.084 105.288 ;
    END
  END s_wdata[7]
  PIN s_wdata[8]
    DIRECTION INPUT ;
    USE SIGNAL ;
    PORT
      LAYER M4 ;
        RECT  0 105.36 0.084 105.384 ;
    END
  END s_wdata[8]
  PIN s_wdata[9]
    DIRECTION INPUT ;
    USE SIGNAL ;
    PORT
      LAYER M4 ;
        RECT  0 105.456 0.084 105.48 ;
    END
  END s_wdata[9]
  PIN s_wready
    DIRECTION OUTPUT ;
    USE SIGNAL ;
    PORT
      LAYER M4 ;
        RECT  0 104.496 0.084 104.52 ;
    END
  END s_wready
  PIN s_wstrb[0]
    DIRECTION INPUT ;
    USE SIGNAL ;
    PORT
      LAYER M4 ;
        RECT  0 107.664 0.084 107.688 ;
    END
  END s_wstrb[0]
  PIN s_wstrb[1]
    DIRECTION INPUT ;
    USE SIGNAL ;
    PORT
      LAYER M4 ;
        RECT  0 107.76 0.084 107.784 ;
    END
  END s_wstrb[1]
  PIN s_wstrb[2]
    DIRECTION INPUT ;
    USE SIGNAL ;
    PORT
      LAYER M4 ;
        RECT  0 107.856 0.084 107.88 ;
    END
  END s_wstrb[2]
  PIN s_wstrb[3]
    DIRECTION INPUT ;
    USE SIGNAL ;
    PORT
      LAYER M4 ;
        RECT  0 107.952 0.084 107.976 ;
    END
  END s_wstrb[3]
  PIN s_wvalid
    DIRECTION INPUT ;
    USE SIGNAL ;
    PORT
      LAYER M4 ;
        RECT  0 104.4 0.084 104.424 ;
    END
  END s_wvalid
  PIN VDD
    DIRECTION INOUT ;
    USE POWER ;
    PORT
      LAYER M5 ;
        RECT  213.192 2.151 213.312 213.849 ;
        RECT  207.792 2.151 207.912 213.849 ;
        RECT  202.392 2.151 202.512 213.849 ;
        RECT  196.992 2.151 197.112 213.849 ;
        RECT  191.592 2.151 191.712 213.849 ;
        RECT  186.192 2.151 186.312 213.849 ;
        RECT  180.792 2.151 180.912 213.849 ;
        RECT  175.392 2.151 175.512 213.849 ;
        RECT  169.992 2.151 170.112 213.849 ;
        RECT  164.592 2.151 164.712 213.849 ;
        RECT  159.192 2.151 159.312 213.849 ;
        RECT  153.792 2.151 153.912 213.849 ;
        RECT  148.392 2.151 148.512 213.849 ;
        RECT  142.992 2.151 143.112 213.849 ;
        RECT  137.592 2.151 137.712 213.849 ;
        RECT  132.192 2.151 132.312 213.849 ;
        RECT  126.792 2.151 126.912 213.849 ;
        RECT  121.392 2.151 121.512 213.849 ;
        RECT  115.992 2.151 116.112 213.849 ;
        RECT  110.592 2.151 110.712 213.849 ;
        RECT  105.192 2.151 105.312 213.849 ;
        RECT  99.792 2.151 99.912 213.849 ;
        RECT  94.392 2.151 94.512 213.849 ;
        RECT  88.992 2.151 89.112 213.849 ;
        RECT  83.592 2.151 83.712 213.849 ;
        RECT  78.192 2.151 78.312 213.849 ;
        RECT  72.792 2.151 72.912 213.849 ;
        RECT  67.392 2.151 67.512 213.849 ;
        RECT  61.992 2.151 62.112 213.849 ;
        RECT  56.592 2.151 56.712 213.849 ;
        RECT  51.192 2.151 51.312 213.849 ;
        RECT  45.792 2.151 45.912 213.849 ;
        RECT  40.392 2.151 40.512 213.849 ;
        RECT  34.992 2.151 35.112 213.849 ;
        RECT  29.592 2.151 29.712 213.849 ;
        RECT  24.192 2.151 24.312 213.849 ;
        RECT  18.792 2.151 18.912 213.849 ;
        RECT  13.392 2.151 13.512 213.849 ;
        RECT  7.992 2.151 8.112 213.849 ;
        RECT  2.592 2.151 2.712 213.849 ;
    END
  END VDD
  PIN VSS
    DIRECTION INOUT ;
    USE GROUND ;
    PORT
      LAYER M5 ;
        RECT  213 2.137 213.12 213.863 ;
        RECT  207.6 2.137 207.72 213.863 ;
        RECT  202.2 2.137 202.32 213.863 ;
        RECT  196.8 2.137 196.92 213.863 ;
        RECT  191.4 2.137 191.52 213.863 ;
        RECT  186 2.137 186.12 213.863 ;
        RECT  180.6 2.137 180.72 213.863 ;
        RECT  175.2 2.137 175.32 213.863 ;
        RECT  169.8 2.137 169.92 213.863 ;
        RECT  164.4 2.137 164.52 213.863 ;
        RECT  159 2.137 159.12 213.863 ;
        RECT  153.6 2.137 153.72 213.863 ;
        RECT  148.2 2.137 148.32 213.863 ;
        RECT  142.8 2.137 142.92 213.863 ;
        RECT  137.4 2.137 137.52 213.863 ;
        RECT  132 2.137 132.12 213.863 ;
        RECT  126.6 2.137 126.72 213.863 ;
        RECT  121.2 2.137 121.32 213.863 ;
        RECT  115.8 2.137 115.92 213.863 ;
        RECT  110.4 2.137 110.52 213.863 ;
        RECT  105 2.137 105.12 213.863 ;
        RECT  99.6 2.137 99.72 213.863 ;
        RECT  94.2 2.137 94.32 213.863 ;
        RECT  88.8 2.137 88.92 213.863 ;
        RECT  83.4 2.137 83.52 213.863 ;
        RECT  78 2.137 78.12 213.863 ;
        RECT  72.6 2.137 72.72 213.863 ;
        RECT  67.2 2.137 67.32 213.863 ;
        RECT  61.8 2.137 61.92 213.863 ;
        RECT  56.4 2.137 56.52 213.863 ;
        RECT  51 2.137 51.12 213.863 ;
        RECT  45.6 2.137 45.72 213.863 ;
        RECT  40.2 2.137 40.32 213.863 ;
        RECT  34.8 2.137 34.92 213.863 ;
        RECT  29.4 2.137 29.52 213.863 ;
        RECT  24 2.137 24.12 213.863 ;
        RECT  18.6 2.137 18.72 213.863 ;
        RECT  13.2 2.137 13.32 213.863 ;
        RECT  7.8 2.137 7.92 213.863 ;
        RECT  2.4 2.137 2.52 213.863 ;
    END
  END VSS
  # OT_OBS_CLOSED layer=M5 d_um=1.536 added=116
  OBS
    LAYER RVTN ;
     RECT  2.16 2.16 213.84 2.295 ;
     RECT  2.16 2.565 213.84 2.835 ;
     RECT  2.16 3.105 213.84 3.375 ;
     RECT  2.16 3.645 213.84 3.915 ;
     RECT  2.16 4.185 213.84 4.455 ;
     RECT  2.16 4.725 213.84 4.995 ;
     RECT  2.16 5.265 213.84 5.535 ;
     RECT  2.16 5.805 213.84 6.075 ;
     RECT  2.16 6.345 213.84 6.615 ;
     RECT  2.16 6.885 213.84 7.155 ;
     RECT  2.16 7.425 213.84 7.695 ;
     RECT  2.16 7.965 213.84 8.235 ;
     RECT  2.16 8.505 213.84 8.775 ;
     RECT  2.16 9.045 213.84 9.315 ;
     RECT  2.16 9.585 213.84 9.855 ;
     RECT  2.16 10.125 213.84 10.395 ;
     RECT  2.16 10.665 213.84 10.935 ;
     RECT  2.16 11.205 213.84 11.475 ;
     RECT  2.16 11.745 213.84 12.015 ;
     RECT  2.16 12.285 213.84 12.555 ;
     RECT  2.16 12.825 213.84 13.095 ;
     RECT  2.16 13.365 213.84 13.635 ;
     RECT  2.16 13.905 213.84 14.175 ;
     RECT  2.16 14.445 213.84 14.715 ;
     RECT  2.16 14.985 213.84 15.255 ;
     RECT  2.16 15.525 213.84 15.795 ;
     RECT  2.16 16.065 213.84 16.335 ;
     RECT  2.16 16.605 213.84 16.875 ;
     RECT  2.16 17.145 213.84 17.415 ;
     RECT  2.16 17.685 213.84 17.955 ;
     RECT  2.16 18.225 213.84 18.495 ;
     RECT  2.16 18.765 213.84 19.035 ;
     RECT  2.16 19.305 213.84 19.575 ;
     RECT  2.16 19.845 213.84 20.115 ;
     RECT  2.16 20.385 213.84 20.655 ;
     RECT  2.16 20.925 213.84 21.195 ;
     RECT  2.16 21.465 213.84 21.735 ;
     RECT  2.16 22.005 213.84 22.275 ;
     RECT  2.16 22.545 213.84 22.815 ;
     RECT  2.16 23.085 213.84 23.355 ;
     RECT  2.16 23.625 213.84 23.895 ;
     RECT  2.16 24.165 213.84 24.435 ;
     RECT  2.16 24.705 213.84 24.975 ;
     RECT  2.16 25.245 213.84 25.515 ;
     RECT  2.16 25.785 213.84 26.055 ;
     RECT  2.16 26.325 213.84 26.595 ;
     RECT  2.16 26.865 213.84 27.135 ;
     RECT  2.16 27.405 213.84 27.675 ;
     RECT  2.16 27.945 213.84 28.215 ;
     RECT  2.16 28.485 213.84 28.755 ;
     RECT  2.16 29.025 213.84 29.295 ;
     RECT  2.16 29.565 213.84 29.835 ;
     RECT  2.16 30.105 213.84 30.375 ;
     RECT  2.16 30.645 213.84 30.915 ;
     RECT  2.16 31.185 213.84 31.455 ;
     RECT  2.16 31.725 213.84 31.995 ;
     RECT  2.16 32.265 213.84 32.535 ;
     RECT  2.16 32.805 213.84 33.075 ;
     RECT  2.16 33.345 213.84 33.615 ;
     RECT  2.16 33.885 213.84 34.155 ;
     RECT  2.16 34.425 213.84 34.695 ;
     RECT  2.16 34.965 213.84 35.235 ;
     RECT  2.16 35.505 213.84 35.775 ;
     RECT  2.16 36.045 213.84 36.315 ;
     RECT  2.16 36.585 213.84 36.855 ;
     RECT  2.16 37.125 213.84 37.395 ;
     RECT  2.16 37.665 213.84 37.935 ;
     RECT  2.16 38.205 213.84 38.475 ;
     RECT  2.16 38.745 213.84 39.015 ;
     RECT  2.16 39.285 213.84 39.555 ;
     RECT  2.16 39.825 213.84 40.095 ;
     RECT  2.16 40.365 213.84 40.635 ;
     RECT  2.16 40.905 213.84 41.175 ;
     RECT  2.16 41.445 213.84 41.715 ;
     RECT  2.16 41.985 213.84 42.255 ;
     RECT  2.16 42.525 213.84 42.795 ;
     RECT  2.16 43.065 213.84 43.335 ;
     RECT  2.16 43.605 213.84 43.875 ;
     RECT  2.16 44.145 213.84 44.415 ;
     RECT  2.16 44.685 213.84 44.955 ;
     RECT  2.16 45.225 213.84 45.495 ;
     RECT  2.16 45.765 213.84 46.035 ;
     RECT  2.16 46.305 213.84 46.575 ;
     RECT  2.16 46.845 213.84 47.115 ;
     RECT  2.16 47.385 213.84 47.655 ;
     RECT  2.16 47.925 213.84 48.195 ;
     RECT  2.16 48.465 213.84 48.735 ;
     RECT  2.16 49.005 213.84 49.275 ;
     RECT  2.16 49.545 213.84 49.815 ;
     RECT  2.16 50.085 213.84 50.355 ;
     RECT  2.16 50.625 213.84 50.895 ;
     RECT  2.16 51.165 213.84 51.435 ;
     RECT  2.16 51.705 213.84 51.975 ;
     RECT  2.16 52.245 213.84 52.515 ;
     RECT  2.16 52.785 213.84 53.055 ;
     RECT  2.16 53.325 213.84 53.595 ;
     RECT  2.16 53.865 213.84 54.135 ;
     RECT  2.16 54.405 213.84 54.675 ;
     RECT  2.16 54.945 213.84 55.215 ;
     RECT  2.16 55.485 213.84 55.755 ;
     RECT  2.16 56.025 213.84 56.295 ;
     RECT  2.16 56.565 213.84 56.835 ;
     RECT  2.16 57.105 213.84 57.375 ;
     RECT  2.16 57.645 213.84 57.915 ;
     RECT  2.16 58.185 213.84 58.455 ;
     RECT  2.16 58.725 213.84 58.995 ;
     RECT  2.16 59.265 213.84 59.535 ;
     RECT  2.16 59.805 213.84 60.075 ;
     RECT  2.16 60.345 213.84 60.615 ;
     RECT  2.16 60.885 213.84 61.155 ;
     RECT  2.16 61.425 213.84 61.695 ;
     RECT  2.16 61.965 213.84 62.235 ;
     RECT  2.16 62.505 213.84 62.775 ;
     RECT  2.16 63.045 213.84 63.315 ;
     RECT  2.16 63.585 213.84 63.855 ;
     RECT  2.16 64.125 213.84 64.395 ;
     RECT  2.16 64.665 213.84 64.935 ;
     RECT  2.16 65.205 213.84 65.475 ;
     RECT  2.16 65.745 213.84 66.015 ;
     RECT  2.16 66.285 213.84 66.555 ;
     RECT  2.16 66.825 213.84 67.095 ;
     RECT  2.16 67.365 213.84 67.635 ;
     RECT  2.16 67.905 213.84 68.175 ;
     RECT  2.16 68.445 213.84 68.715 ;
     RECT  2.16 68.985 213.84 69.255 ;
     RECT  2.16 69.525 213.84 69.795 ;
     RECT  2.16 70.065 213.84 70.335 ;
     RECT  2.16 70.605 213.84 70.875 ;
     RECT  2.16 71.145 213.84 71.415 ;
     RECT  2.16 71.685 213.84 71.955 ;
     RECT  2.16 72.225 213.84 72.495 ;
     RECT  2.16 72.765 213.84 73.035 ;
     RECT  2.16 73.305 213.84 73.575 ;
     RECT  2.16 73.845 213.84 74.115 ;
     RECT  2.16 74.385 213.84 74.655 ;
     RECT  2.16 74.925 213.84 75.195 ;
     RECT  2.16 75.465 213.84 75.735 ;
     RECT  2.16 76.005 213.84 76.275 ;
     RECT  2.16 76.545 213.84 76.815 ;
     RECT  2.16 77.085 213.84 77.355 ;
     RECT  2.16 77.625 213.84 77.895 ;
     RECT  2.16 78.165 213.84 78.435 ;
     RECT  2.16 78.705 213.84 78.975 ;
     RECT  2.16 79.245 213.84 79.515 ;
     RECT  2.16 79.785 213.84 80.055 ;
     RECT  2.16 80.325 213.84 80.595 ;
     RECT  2.16 80.865 213.84 81.135 ;
     RECT  2.16 81.405 213.84 81.675 ;
     RECT  2.16 81.945 213.84 82.215 ;
     RECT  2.16 82.485 213.84 82.755 ;
     RECT  2.16 83.025 213.84 83.295 ;
     RECT  2.16 83.565 213.84 83.835 ;
     RECT  2.16 84.105 213.84 84.375 ;
     RECT  2.16 84.645 213.84 84.915 ;
     RECT  2.16 85.185 213.84 85.455 ;
     RECT  2.16 85.725 213.84 85.995 ;
     RECT  2.16 86.265 213.84 86.535 ;
     RECT  2.16 86.805 213.84 87.075 ;
     RECT  2.16 87.345 213.84 87.615 ;
     RECT  2.16 87.885 213.84 88.155 ;
     RECT  2.16 88.425 213.84 88.695 ;
     RECT  2.16 88.965 213.84 89.235 ;
     RECT  2.16 89.505 213.84 89.775 ;
     RECT  2.16 90.045 213.84 90.315 ;
     RECT  2.16 90.585 213.84 90.855 ;
     RECT  2.16 91.125 213.84 91.395 ;
     RECT  2.16 91.665 213.84 91.935 ;
     RECT  2.16 92.205 213.84 92.475 ;
     RECT  2.16 92.745 213.84 93.015 ;
     RECT  2.16 93.285 213.84 93.555 ;
     RECT  2.16 93.825 213.84 94.095 ;
     RECT  2.16 94.365 213.84 94.635 ;
     RECT  2.16 94.905 213.84 95.175 ;
     RECT  2.16 95.445 213.84 95.715 ;
     RECT  2.16 95.985 213.84 96.255 ;
     RECT  2.16 96.525 213.84 96.795 ;
     RECT  2.16 97.065 213.84 97.335 ;
     RECT  2.16 97.605 213.84 97.875 ;
     RECT  2.16 98.145 213.84 98.415 ;
     RECT  2.16 98.685 213.84 98.955 ;
     RECT  2.16 99.225 213.84 99.495 ;
     RECT  2.16 99.765 213.84 100.035 ;
     RECT  2.16 100.305 213.84 100.575 ;
     RECT  2.16 100.845 213.84 101.115 ;
     RECT  2.16 101.385 213.84 101.655 ;
     RECT  2.16 101.925 213.84 102.195 ;
     RECT  2.16 102.465 213.84 102.735 ;
     RECT  2.16 103.005 213.84 103.275 ;
     RECT  2.16 103.545 213.84 103.815 ;
     RECT  2.16 104.085 213.84 104.355 ;
     RECT  2.16 104.625 213.84 104.895 ;
     RECT  2.16 105.165 213.84 105.435 ;
     RECT  2.16 105.705 213.84 105.975 ;
     RECT  2.16 106.245 213.84 106.515 ;
     RECT  2.16 106.785 213.84 107.055 ;
     RECT  2.16 107.325 213.84 107.595 ;
     RECT  2.16 107.865 213.84 108.135 ;
     RECT  2.16 108.405 213.84 108.675 ;
     RECT  2.16 108.945 213.84 109.215 ;
     RECT  2.16 109.485 213.84 109.755 ;
     RECT  2.16 110.025 213.84 110.295 ;
     RECT  2.16 110.565 213.84 110.835 ;
     RECT  2.16 111.105 213.84 111.375 ;
     RECT  2.16 111.645 213.84 111.915 ;
     RECT  2.16 112.185 213.84 112.455 ;
     RECT  2.16 112.725 213.84 112.995 ;
     RECT  2.16 113.265 213.84 113.535 ;
     RECT  2.16 113.805 213.84 114.075 ;
     RECT  2.16 114.345 213.84 114.615 ;
     RECT  2.16 114.885 213.84 115.155 ;
     RECT  2.16 115.425 213.84 115.695 ;
     RECT  2.16 115.965 213.84 116.235 ;
     RECT  2.16 116.505 213.84 116.775 ;
     RECT  2.16 117.045 213.84 117.315 ;
     RECT  2.16 117.585 213.84 117.855 ;
     RECT  2.16 118.125 213.84 118.395 ;
     RECT  2.16 118.665 213.84 118.935 ;
     RECT  2.16 119.205 213.84 119.475 ;
     RECT  2.16 119.745 213.84 120.015 ;
     RECT  2.16 120.285 213.84 120.555 ;
     RECT  2.16 120.825 213.84 121.095 ;
     RECT  2.16 121.365 213.84 121.635 ;
     RECT  2.16 121.905 213.84 122.175 ;
     RECT  2.16 122.445 213.84 122.715 ;
     RECT  2.16 122.985 213.84 123.255 ;
     RECT  2.16 123.525 213.84 123.795 ;
     RECT  2.16 124.065 213.84 124.335 ;
     RECT  2.16 124.605 213.84 124.875 ;
     RECT  2.16 125.145 213.84 125.415 ;
     RECT  2.16 125.685 213.84 125.955 ;
     RECT  2.16 126.225 213.84 126.495 ;
     RECT  2.16 126.765 213.84 127.035 ;
     RECT  2.16 127.305 213.84 127.575 ;
     RECT  2.16 127.845 213.84 128.115 ;
     RECT  2.16 128.385 213.84 128.655 ;
     RECT  2.16 128.925 213.84 129.195 ;
     RECT  2.16 129.465 213.84 129.735 ;
     RECT  2.16 130.005 213.84 130.275 ;
     RECT  2.16 130.545 213.84 130.815 ;
     RECT  2.16 131.085 213.84 131.355 ;
     RECT  2.16 131.625 213.84 131.895 ;
     RECT  2.16 132.165 213.84 132.435 ;
     RECT  2.16 132.705 213.84 132.975 ;
     RECT  2.16 133.245 213.84 133.515 ;
     RECT  2.16 133.785 213.84 134.055 ;
     RECT  2.16 134.325 213.84 134.595 ;
     RECT  2.16 134.865 213.84 135.135 ;
     RECT  2.16 135.405 213.84 135.675 ;
     RECT  2.16 135.945 213.84 136.215 ;
     RECT  2.16 136.485 213.84 136.755 ;
     RECT  2.16 137.025 213.84 137.295 ;
     RECT  2.16 137.565 213.84 137.835 ;
     RECT  2.16 138.105 213.84 138.375 ;
     RECT  2.16 138.645 213.84 138.915 ;
     RECT  2.16 139.185 213.84 139.455 ;
     RECT  2.16 139.725 213.84 139.995 ;
     RECT  2.16 140.265 213.84 140.535 ;
     RECT  2.16 140.805 213.84 141.075 ;
     RECT  2.16 141.345 213.84 141.615 ;
     RECT  2.16 141.885 213.84 142.155 ;
     RECT  2.16 142.425 213.84 142.695 ;
     RECT  2.16 142.965 213.84 143.235 ;
     RECT  2.16 143.505 213.84 143.775 ;
     RECT  2.16 144.045 213.84 144.315 ;
     RECT  2.16 144.585 213.84 144.855 ;
     RECT  2.16 145.125 213.84 145.395 ;
     RECT  2.16 145.665 213.84 145.935 ;
     RECT  2.16 146.205 213.84 146.475 ;
     RECT  2.16 146.745 213.84 147.015 ;
     RECT  2.16 147.285 213.84 147.555 ;
     RECT  2.16 147.825 213.84 148.095 ;
     RECT  2.16 148.365 213.84 148.635 ;
     RECT  2.16 148.905 213.84 149.175 ;
     RECT  2.16 149.445 213.84 149.715 ;
     RECT  2.16 149.985 213.84 150.255 ;
     RECT  2.16 150.525 213.84 150.795 ;
     RECT  2.16 151.065 213.84 151.335 ;
     RECT  2.16 151.605 213.84 151.875 ;
     RECT  2.16 152.145 213.84 152.415 ;
     RECT  2.16 152.685 213.84 152.955 ;
     RECT  2.16 153.225 213.84 153.495 ;
     RECT  2.16 153.765 213.84 154.035 ;
     RECT  2.16 154.305 213.84 154.575 ;
     RECT  2.16 154.845 213.84 155.115 ;
     RECT  2.16 155.385 213.84 155.655 ;
     RECT  2.16 155.925 213.84 156.195 ;
     RECT  2.16 156.465 213.84 156.735 ;
     RECT  2.16 157.005 213.84 157.275 ;
     RECT  2.16 157.545 213.84 157.815 ;
     RECT  2.16 158.085 213.84 158.355 ;
     RECT  2.16 158.625 213.84 158.895 ;
     RECT  2.16 159.165 213.84 159.435 ;
     RECT  2.16 159.705 213.84 159.975 ;
     RECT  2.16 160.245 213.84 160.515 ;
     RECT  2.16 160.785 213.84 161.055 ;
     RECT  2.16 161.325 213.84 161.595 ;
     RECT  2.16 161.865 213.84 162.135 ;
     RECT  2.16 162.405 213.84 162.675 ;
     RECT  2.16 162.945 213.84 163.215 ;
     RECT  2.16 163.485 213.84 163.755 ;
     RECT  2.16 164.025 213.84 164.295 ;
     RECT  2.16 164.565 213.84 164.835 ;
     RECT  2.16 165.105 213.84 165.375 ;
     RECT  2.16 165.645 213.84 165.915 ;
     RECT  2.16 166.185 213.84 166.455 ;
     RECT  2.16 166.725 213.84 166.995 ;
     RECT  2.16 167.265 213.84 167.535 ;
     RECT  2.16 167.805 213.84 168.075 ;
     RECT  2.16 168.345 213.84 168.615 ;
     RECT  2.16 168.885 213.84 169.155 ;
     RECT  2.16 169.425 213.84 169.695 ;
     RECT  2.16 169.965 213.84 170.235 ;
     RECT  2.16 170.505 213.84 170.775 ;
     RECT  2.16 171.045 213.84 171.315 ;
     RECT  2.16 171.585 213.84 171.855 ;
     RECT  2.16 172.125 213.84 172.395 ;
     RECT  2.16 172.665 213.84 172.935 ;
     RECT  2.16 173.205 213.84 173.475 ;
     RECT  2.16 173.745 213.84 174.015 ;
     RECT  2.16 174.285 213.84 174.555 ;
     RECT  2.16 174.825 213.84 175.095 ;
     RECT  2.16 175.365 213.84 175.635 ;
     RECT  2.16 175.905 213.84 176.175 ;
     RECT  2.16 176.445 213.84 176.715 ;
     RECT  2.16 176.985 213.84 177.255 ;
     RECT  2.16 177.525 213.84 177.795 ;
     RECT  2.16 178.065 213.84 178.335 ;
     RECT  2.16 178.605 213.84 178.875 ;
     RECT  2.16 179.145 213.84 179.415 ;
     RECT  2.16 179.685 213.84 179.955 ;
     RECT  2.16 180.225 213.84 180.495 ;
     RECT  2.16 180.765 213.84 181.035 ;
     RECT  2.16 181.305 213.84 181.575 ;
     RECT  2.16 181.845 213.84 182.115 ;
     RECT  2.16 182.385 213.84 182.655 ;
     RECT  2.16 182.925 213.84 183.195 ;
     RECT  2.16 183.465 213.84 183.735 ;
     RECT  2.16 184.005 213.84 184.275 ;
     RECT  2.16 184.545 213.84 184.815 ;
     RECT  2.16 185.085 213.84 185.355 ;
     RECT  2.16 185.625 213.84 185.895 ;
     RECT  2.16 186.165 213.84 186.435 ;
     RECT  2.16 186.705 213.84 186.975 ;
     RECT  2.16 187.245 213.84 187.515 ;
     RECT  2.16 187.785 213.84 188.055 ;
     RECT  2.16 188.325 213.84 188.595 ;
     RECT  2.16 188.865 213.84 189.135 ;
     RECT  2.16 189.405 213.84 189.675 ;
     RECT  2.16 189.945 213.84 190.215 ;
     RECT  2.16 190.485 213.84 190.755 ;
     RECT  2.16 191.025 213.84 191.295 ;
     RECT  2.16 191.565 213.84 191.835 ;
     RECT  2.16 192.105 213.84 192.375 ;
     RECT  2.16 192.645 213.84 192.915 ;
     RECT  2.16 193.185 213.84 193.455 ;
     RECT  2.16 193.725 213.84 193.995 ;
     RECT  2.16 194.265 213.84 194.535 ;
     RECT  2.16 194.805 213.84 195.075 ;
     RECT  2.16 195.345 213.84 195.615 ;
     RECT  2.16 195.885 213.84 196.155 ;
     RECT  2.16 196.425 213.84 196.695 ;
     RECT  2.16 196.965 213.84 197.235 ;
     RECT  2.16 197.505 213.84 197.775 ;
     RECT  2.16 198.045 213.84 198.315 ;
     RECT  2.16 198.585 213.84 198.855 ;
     RECT  2.16 199.125 213.84 199.395 ;
     RECT  2.16 199.665 213.84 199.935 ;
     RECT  2.16 200.205 213.84 200.475 ;
     RECT  2.16 200.745 213.84 201.015 ;
     RECT  2.16 201.285 213.84 201.555 ;
     RECT  2.16 201.825 213.84 202.095 ;
     RECT  2.16 202.365 213.84 202.635 ;
     RECT  2.16 202.905 213.84 203.175 ;
     RECT  2.16 203.445 213.84 203.715 ;
     RECT  2.16 203.985 213.84 204.255 ;
     RECT  2.16 204.525 213.84 204.795 ;
     RECT  2.16 205.065 213.84 205.335 ;
     RECT  2.16 205.605 213.84 205.875 ;
     RECT  2.16 206.145 213.84 206.415 ;
     RECT  2.16 206.685 213.84 206.955 ;
     RECT  2.16 207.225 213.84 207.495 ;
     RECT  2.16 207.765 213.84 208.035 ;
     RECT  2.16 208.305 213.84 208.575 ;
     RECT  2.16 208.845 213.84 209.115 ;
     RECT  2.16 209.385 213.84 209.655 ;
     RECT  2.16 209.925 213.84 210.195 ;
     RECT  2.16 210.465 213.84 210.735 ;
     RECT  2.16 211.005 213.84 211.275 ;
     RECT  2.16 211.545 213.84 211.815 ;
     RECT  2.16 212.085 213.84 212.355 ;
     RECT  2.16 212.625 213.84 212.895 ;
     RECT  2.16 213.165 213.84 213.435 ;
     RECT  2.16 213.705 213.84 213.84 ;
    LAYER RVTP ;
     RECT  2.16 2.295 213.84 2.565 ;
     RECT  2.16 2.835 213.84 3.105 ;
     RECT  2.16 3.375 213.84 3.645 ;
     RECT  2.16 3.915 213.84 4.185 ;
     RECT  2.16 4.455 213.84 4.725 ;
     RECT  2.16 4.995 213.84 5.265 ;
     RECT  2.16 5.535 213.84 5.805 ;
     RECT  2.16 6.075 213.84 6.345 ;
     RECT  2.16 6.615 213.84 6.885 ;
     RECT  2.16 7.155 213.84 7.425 ;
     RECT  2.16 7.695 213.84 7.965 ;
     RECT  2.16 8.235 213.84 8.505 ;
     RECT  2.16 8.775 213.84 9.045 ;
     RECT  2.16 9.315 213.84 9.585 ;
     RECT  2.16 9.855 213.84 10.125 ;
     RECT  2.16 10.395 213.84 10.665 ;
     RECT  2.16 10.935 213.84 11.205 ;
     RECT  2.16 11.475 213.84 11.745 ;
     RECT  2.16 12.015 213.84 12.285 ;
     RECT  2.16 12.555 213.84 12.825 ;
     RECT  2.16 13.095 213.84 13.365 ;
     RECT  2.16 13.635 213.84 13.905 ;
     RECT  2.16 14.175 213.84 14.445 ;
     RECT  2.16 14.715 213.84 14.985 ;
     RECT  2.16 15.255 213.84 15.525 ;
     RECT  2.16 15.795 213.84 16.065 ;
     RECT  2.16 16.335 213.84 16.605 ;
     RECT  2.16 16.875 213.84 17.145 ;
     RECT  2.16 17.415 213.84 17.685 ;
     RECT  2.16 17.955 213.84 18.225 ;
     RECT  2.16 18.495 213.84 18.765 ;
     RECT  2.16 19.035 213.84 19.305 ;
     RECT  2.16 19.575 213.84 19.845 ;
     RECT  2.16 20.115 213.84 20.385 ;
     RECT  2.16 20.655 213.84 20.925 ;
     RECT  2.16 21.195 213.84 21.465 ;
     RECT  2.16 21.735 213.84 22.005 ;
     RECT  2.16 22.275 213.84 22.545 ;
     RECT  2.16 22.815 213.84 23.085 ;
     RECT  2.16 23.355 213.84 23.625 ;
     RECT  2.16 23.895 213.84 24.165 ;
     RECT  2.16 24.435 213.84 24.705 ;
     RECT  2.16 24.975 213.84 25.245 ;
     RECT  2.16 25.515 213.84 25.785 ;
     RECT  2.16 26.055 213.84 26.325 ;
     RECT  2.16 26.595 213.84 26.865 ;
     RECT  2.16 27.135 213.84 27.405 ;
     RECT  2.16 27.675 213.84 27.945 ;
     RECT  2.16 28.215 213.84 28.485 ;
     RECT  2.16 28.755 213.84 29.025 ;
     RECT  2.16 29.295 213.84 29.565 ;
     RECT  2.16 29.835 213.84 30.105 ;
     RECT  2.16 30.375 213.84 30.645 ;
     RECT  2.16 30.915 213.84 31.185 ;
     RECT  2.16 31.455 213.84 31.725 ;
     RECT  2.16 31.995 213.84 32.265 ;
     RECT  2.16 32.535 213.84 32.805 ;
     RECT  2.16 33.075 213.84 33.345 ;
     RECT  2.16 33.615 213.84 33.885 ;
     RECT  2.16 34.155 213.84 34.425 ;
     RECT  2.16 34.695 213.84 34.965 ;
     RECT  2.16 35.235 213.84 35.505 ;
     RECT  2.16 35.775 213.84 36.045 ;
     RECT  2.16 36.315 213.84 36.585 ;
     RECT  2.16 36.855 213.84 37.125 ;
     RECT  2.16 37.395 213.84 37.665 ;
     RECT  2.16 37.935 213.84 38.205 ;
     RECT  2.16 38.475 213.84 38.745 ;
     RECT  2.16 39.015 213.84 39.285 ;
     RECT  2.16 39.555 213.84 39.825 ;
     RECT  2.16 40.095 213.84 40.365 ;
     RECT  2.16 40.635 213.84 40.905 ;
     RECT  2.16 41.175 213.84 41.445 ;
     RECT  2.16 41.715 213.84 41.985 ;
     RECT  2.16 42.255 213.84 42.525 ;
     RECT  2.16 42.795 213.84 43.065 ;
     RECT  2.16 43.335 213.84 43.605 ;
     RECT  2.16 43.875 213.84 44.145 ;
     RECT  2.16 44.415 213.84 44.685 ;
     RECT  2.16 44.955 213.84 45.225 ;
     RECT  2.16 45.495 213.84 45.765 ;
     RECT  2.16 46.035 213.84 46.305 ;
     RECT  2.16 46.575 213.84 46.845 ;
     RECT  2.16 47.115 213.84 47.385 ;
     RECT  2.16 47.655 213.84 47.925 ;
     RECT  2.16 48.195 213.84 48.465 ;
     RECT  2.16 48.735 213.84 49.005 ;
     RECT  2.16 49.275 213.84 49.545 ;
     RECT  2.16 49.815 213.84 50.085 ;
     RECT  2.16 50.355 213.84 50.625 ;
     RECT  2.16 50.895 213.84 51.165 ;
     RECT  2.16 51.435 213.84 51.705 ;
     RECT  2.16 51.975 213.84 52.245 ;
     RECT  2.16 52.515 213.84 52.785 ;
     RECT  2.16 53.055 213.84 53.325 ;
     RECT  2.16 53.595 213.84 53.865 ;
     RECT  2.16 54.135 213.84 54.405 ;
     RECT  2.16 54.675 213.84 54.945 ;
     RECT  2.16 55.215 213.84 55.485 ;
     RECT  2.16 55.755 213.84 56.025 ;
     RECT  2.16 56.295 213.84 56.565 ;
     RECT  2.16 56.835 213.84 57.105 ;
     RECT  2.16 57.375 213.84 57.645 ;
     RECT  2.16 57.915 213.84 58.185 ;
     RECT  2.16 58.455 213.84 58.725 ;
     RECT  2.16 58.995 213.84 59.265 ;
     RECT  2.16 59.535 213.84 59.805 ;
     RECT  2.16 60.075 213.84 60.345 ;
     RECT  2.16 60.615 213.84 60.885 ;
     RECT  2.16 61.155 213.84 61.425 ;
     RECT  2.16 61.695 213.84 61.965 ;
     RECT  2.16 62.235 213.84 62.505 ;
     RECT  2.16 62.775 213.84 63.045 ;
     RECT  2.16 63.315 213.84 63.585 ;
     RECT  2.16 63.855 213.84 64.125 ;
     RECT  2.16 64.395 213.84 64.665 ;
     RECT  2.16 64.935 213.84 65.205 ;
     RECT  2.16 65.475 213.84 65.745 ;
     RECT  2.16 66.015 213.84 66.285 ;
     RECT  2.16 66.555 213.84 66.825 ;
     RECT  2.16 67.095 213.84 67.365 ;
     RECT  2.16 67.635 213.84 67.905 ;
     RECT  2.16 68.175 213.84 68.445 ;
     RECT  2.16 68.715 213.84 68.985 ;
     RECT  2.16 69.255 213.84 69.525 ;
     RECT  2.16 69.795 213.84 70.065 ;
     RECT  2.16 70.335 213.84 70.605 ;
     RECT  2.16 70.875 213.84 71.145 ;
     RECT  2.16 71.415 213.84 71.685 ;
     RECT  2.16 71.955 213.84 72.225 ;
     RECT  2.16 72.495 213.84 72.765 ;
     RECT  2.16 73.035 213.84 73.305 ;
     RECT  2.16 73.575 213.84 73.845 ;
     RECT  2.16 74.115 213.84 74.385 ;
     RECT  2.16 74.655 213.84 74.925 ;
     RECT  2.16 75.195 213.84 75.465 ;
     RECT  2.16 75.735 213.84 76.005 ;
     RECT  2.16 76.275 213.84 76.545 ;
     RECT  2.16 76.815 213.84 77.085 ;
     RECT  2.16 77.355 213.84 77.625 ;
     RECT  2.16 77.895 213.84 78.165 ;
     RECT  2.16 78.435 213.84 78.705 ;
     RECT  2.16 78.975 213.84 79.245 ;
     RECT  2.16 79.515 213.84 79.785 ;
     RECT  2.16 80.055 213.84 80.325 ;
     RECT  2.16 80.595 213.84 80.865 ;
     RECT  2.16 81.135 213.84 81.405 ;
     RECT  2.16 81.675 213.84 81.945 ;
     RECT  2.16 82.215 213.84 82.485 ;
     RECT  2.16 82.755 213.84 83.025 ;
     RECT  2.16 83.295 213.84 83.565 ;
     RECT  2.16 83.835 213.84 84.105 ;
     RECT  2.16 84.375 213.84 84.645 ;
     RECT  2.16 84.915 213.84 85.185 ;
     RECT  2.16 85.455 213.84 85.725 ;
     RECT  2.16 85.995 213.84 86.265 ;
     RECT  2.16 86.535 213.84 86.805 ;
     RECT  2.16 87.075 213.84 87.345 ;
     RECT  2.16 87.615 213.84 87.885 ;
     RECT  2.16 88.155 213.84 88.425 ;
     RECT  2.16 88.695 213.84 88.965 ;
     RECT  2.16 89.235 213.84 89.505 ;
     RECT  2.16 89.775 213.84 90.045 ;
     RECT  2.16 90.315 213.84 90.585 ;
     RECT  2.16 90.855 213.84 91.125 ;
     RECT  2.16 91.395 213.84 91.665 ;
     RECT  2.16 91.935 213.84 92.205 ;
     RECT  2.16 92.475 213.84 92.745 ;
     RECT  2.16 93.015 213.84 93.285 ;
     RECT  2.16 93.555 213.84 93.825 ;
     RECT  2.16 94.095 213.84 94.365 ;
     RECT  2.16 94.635 213.84 94.905 ;
     RECT  2.16 95.175 213.84 95.445 ;
     RECT  2.16 95.715 213.84 95.985 ;
     RECT  2.16 96.255 213.84 96.525 ;
     RECT  2.16 96.795 213.84 97.065 ;
     RECT  2.16 97.335 213.84 97.605 ;
     RECT  2.16 97.875 213.84 98.145 ;
     RECT  2.16 98.415 213.84 98.685 ;
     RECT  2.16 98.955 213.84 99.225 ;
     RECT  2.16 99.495 213.84 99.765 ;
     RECT  2.16 100.035 213.84 100.305 ;
     RECT  2.16 100.575 213.84 100.845 ;
     RECT  2.16 101.115 213.84 101.385 ;
     RECT  2.16 101.655 213.84 101.925 ;
     RECT  2.16 102.195 213.84 102.465 ;
     RECT  2.16 102.735 213.84 103.005 ;
     RECT  2.16 103.275 213.84 103.545 ;
     RECT  2.16 103.815 213.84 104.085 ;
     RECT  2.16 104.355 213.84 104.625 ;
     RECT  2.16 104.895 213.84 105.165 ;
     RECT  2.16 105.435 213.84 105.705 ;
     RECT  2.16 105.975 213.84 106.245 ;
     RECT  2.16 106.515 213.84 106.785 ;
     RECT  2.16 107.055 213.84 107.325 ;
     RECT  2.16 107.595 213.84 107.865 ;
     RECT  2.16 108.135 213.84 108.405 ;
     RECT  2.16 108.675 213.84 108.945 ;
     RECT  2.16 109.215 213.84 109.485 ;
     RECT  2.16 109.755 213.84 110.025 ;
     RECT  2.16 110.295 213.84 110.565 ;
     RECT  2.16 110.835 213.84 111.105 ;
     RECT  2.16 111.375 213.84 111.645 ;
     RECT  2.16 111.915 213.84 112.185 ;
     RECT  2.16 112.455 213.84 112.725 ;
     RECT  2.16 112.995 213.84 113.265 ;
     RECT  2.16 113.535 213.84 113.805 ;
     RECT  2.16 114.075 213.84 114.345 ;
     RECT  2.16 114.615 213.84 114.885 ;
     RECT  2.16 115.155 213.84 115.425 ;
     RECT  2.16 115.695 213.84 115.965 ;
     RECT  2.16 116.235 213.84 116.505 ;
     RECT  2.16 116.775 213.84 117.045 ;
     RECT  2.16 117.315 213.84 117.585 ;
     RECT  2.16 117.855 213.84 118.125 ;
     RECT  2.16 118.395 213.84 118.665 ;
     RECT  2.16 118.935 213.84 119.205 ;
     RECT  2.16 119.475 213.84 119.745 ;
     RECT  2.16 120.015 213.84 120.285 ;
     RECT  2.16 120.555 213.84 120.825 ;
     RECT  2.16 121.095 213.84 121.365 ;
     RECT  2.16 121.635 213.84 121.905 ;
     RECT  2.16 122.175 213.84 122.445 ;
     RECT  2.16 122.715 213.84 122.985 ;
     RECT  2.16 123.255 213.84 123.525 ;
     RECT  2.16 123.795 213.84 124.065 ;
     RECT  2.16 124.335 213.84 124.605 ;
     RECT  2.16 124.875 213.84 125.145 ;
     RECT  2.16 125.415 213.84 125.685 ;
     RECT  2.16 125.955 213.84 126.225 ;
     RECT  2.16 126.495 213.84 126.765 ;
     RECT  2.16 127.035 213.84 127.305 ;
     RECT  2.16 127.575 213.84 127.845 ;
     RECT  2.16 128.115 213.84 128.385 ;
     RECT  2.16 128.655 213.84 128.925 ;
     RECT  2.16 129.195 213.84 129.465 ;
     RECT  2.16 129.735 213.84 130.005 ;
     RECT  2.16 130.275 213.84 130.545 ;
     RECT  2.16 130.815 213.84 131.085 ;
     RECT  2.16 131.355 213.84 131.625 ;
     RECT  2.16 131.895 213.84 132.165 ;
     RECT  2.16 132.435 213.84 132.705 ;
     RECT  2.16 132.975 213.84 133.245 ;
     RECT  2.16 133.515 213.84 133.785 ;
     RECT  2.16 134.055 213.84 134.325 ;
     RECT  2.16 134.595 213.84 134.865 ;
     RECT  2.16 135.135 213.84 135.405 ;
     RECT  2.16 135.675 213.84 135.945 ;
     RECT  2.16 136.215 213.84 136.485 ;
     RECT  2.16 136.755 213.84 137.025 ;
     RECT  2.16 137.295 213.84 137.565 ;
     RECT  2.16 137.835 213.84 138.105 ;
     RECT  2.16 138.375 213.84 138.645 ;
     RECT  2.16 138.915 213.84 139.185 ;
     RECT  2.16 139.455 213.84 139.725 ;
     RECT  2.16 139.995 213.84 140.265 ;
     RECT  2.16 140.535 213.84 140.805 ;
     RECT  2.16 141.075 213.84 141.345 ;
     RECT  2.16 141.615 213.84 141.885 ;
     RECT  2.16 142.155 213.84 142.425 ;
     RECT  2.16 142.695 213.84 142.965 ;
     RECT  2.16 143.235 213.84 143.505 ;
     RECT  2.16 143.775 213.84 144.045 ;
     RECT  2.16 144.315 213.84 144.585 ;
     RECT  2.16 144.855 213.84 145.125 ;
     RECT  2.16 145.395 213.84 145.665 ;
     RECT  2.16 145.935 213.84 146.205 ;
     RECT  2.16 146.475 213.84 146.745 ;
     RECT  2.16 147.015 213.84 147.285 ;
     RECT  2.16 147.555 213.84 147.825 ;
     RECT  2.16 148.095 213.84 148.365 ;
     RECT  2.16 148.635 213.84 148.905 ;
     RECT  2.16 149.175 213.84 149.445 ;
     RECT  2.16 149.715 213.84 149.985 ;
     RECT  2.16 150.255 213.84 150.525 ;
     RECT  2.16 150.795 213.84 151.065 ;
     RECT  2.16 151.335 213.84 151.605 ;
     RECT  2.16 151.875 213.84 152.145 ;
     RECT  2.16 152.415 213.84 152.685 ;
     RECT  2.16 152.955 213.84 153.225 ;
     RECT  2.16 153.495 213.84 153.765 ;
     RECT  2.16 154.035 213.84 154.305 ;
     RECT  2.16 154.575 213.84 154.845 ;
     RECT  2.16 155.115 213.84 155.385 ;
     RECT  2.16 155.655 213.84 155.925 ;
     RECT  2.16 156.195 213.84 156.465 ;
     RECT  2.16 156.735 213.84 157.005 ;
     RECT  2.16 157.275 213.84 157.545 ;
     RECT  2.16 157.815 213.84 158.085 ;
     RECT  2.16 158.355 213.84 158.625 ;
     RECT  2.16 158.895 213.84 159.165 ;
     RECT  2.16 159.435 213.84 159.705 ;
     RECT  2.16 159.975 213.84 160.245 ;
     RECT  2.16 160.515 213.84 160.785 ;
     RECT  2.16 161.055 213.84 161.325 ;
     RECT  2.16 161.595 213.84 161.865 ;
     RECT  2.16 162.135 213.84 162.405 ;
     RECT  2.16 162.675 213.84 162.945 ;
     RECT  2.16 163.215 213.84 163.485 ;
     RECT  2.16 163.755 213.84 164.025 ;
     RECT  2.16 164.295 213.84 164.565 ;
     RECT  2.16 164.835 213.84 165.105 ;
     RECT  2.16 165.375 213.84 165.645 ;
     RECT  2.16 165.915 213.84 166.185 ;
     RECT  2.16 166.455 213.84 166.725 ;
     RECT  2.16 166.995 213.84 167.265 ;
     RECT  2.16 167.535 213.84 167.805 ;
     RECT  2.16 168.075 213.84 168.345 ;
     RECT  2.16 168.615 213.84 168.885 ;
     RECT  2.16 169.155 213.84 169.425 ;
     RECT  2.16 169.695 213.84 169.965 ;
     RECT  2.16 170.235 213.84 170.505 ;
     RECT  2.16 170.775 213.84 171.045 ;
     RECT  2.16 171.315 213.84 171.585 ;
     RECT  2.16 171.855 213.84 172.125 ;
     RECT  2.16 172.395 213.84 172.665 ;
     RECT  2.16 172.935 213.84 173.205 ;
     RECT  2.16 173.475 213.84 173.745 ;
     RECT  2.16 174.015 213.84 174.285 ;
     RECT  2.16 174.555 213.84 174.825 ;
     RECT  2.16 175.095 213.84 175.365 ;
     RECT  2.16 175.635 213.84 175.905 ;
     RECT  2.16 176.175 213.84 176.445 ;
     RECT  2.16 176.715 213.84 176.985 ;
     RECT  2.16 177.255 213.84 177.525 ;
     RECT  2.16 177.795 213.84 178.065 ;
     RECT  2.16 178.335 213.84 178.605 ;
     RECT  2.16 178.875 213.84 179.145 ;
     RECT  2.16 179.415 213.84 179.685 ;
     RECT  2.16 179.955 213.84 180.225 ;
     RECT  2.16 180.495 213.84 180.765 ;
     RECT  2.16 181.035 213.84 181.305 ;
     RECT  2.16 181.575 213.84 181.845 ;
     RECT  2.16 182.115 213.84 182.385 ;
     RECT  2.16 182.655 213.84 182.925 ;
     RECT  2.16 183.195 213.84 183.465 ;
     RECT  2.16 183.735 213.84 184.005 ;
     RECT  2.16 184.275 213.84 184.545 ;
     RECT  2.16 184.815 213.84 185.085 ;
     RECT  2.16 185.355 213.84 185.625 ;
     RECT  2.16 185.895 213.84 186.165 ;
     RECT  2.16 186.435 213.84 186.705 ;
     RECT  2.16 186.975 213.84 187.245 ;
     RECT  2.16 187.515 213.84 187.785 ;
     RECT  2.16 188.055 213.84 188.325 ;
     RECT  2.16 188.595 213.84 188.865 ;
     RECT  2.16 189.135 213.84 189.405 ;
     RECT  2.16 189.675 213.84 189.945 ;
     RECT  2.16 190.215 213.84 190.485 ;
     RECT  2.16 190.755 213.84 191.025 ;
     RECT  2.16 191.295 213.84 191.565 ;
     RECT  2.16 191.835 213.84 192.105 ;
     RECT  2.16 192.375 213.84 192.645 ;
     RECT  2.16 192.915 213.84 193.185 ;
     RECT  2.16 193.455 213.84 193.725 ;
     RECT  2.16 193.995 213.84 194.265 ;
     RECT  2.16 194.535 213.84 194.805 ;
     RECT  2.16 195.075 213.84 195.345 ;
     RECT  2.16 195.615 213.84 195.885 ;
     RECT  2.16 196.155 213.84 196.425 ;
     RECT  2.16 196.695 213.84 196.965 ;
     RECT  2.16 197.235 213.84 197.505 ;
     RECT  2.16 197.775 213.84 198.045 ;
     RECT  2.16 198.315 213.84 198.585 ;
     RECT  2.16 198.855 213.84 199.125 ;
     RECT  2.16 199.395 213.84 199.665 ;
     RECT  2.16 199.935 213.84 200.205 ;
     RECT  2.16 200.475 213.84 200.745 ;
     RECT  2.16 201.015 213.84 201.285 ;
     RECT  2.16 201.555 213.84 201.825 ;
     RECT  2.16 202.095 213.84 202.365 ;
     RECT  2.16 202.635 213.84 202.905 ;
     RECT  2.16 203.175 213.84 203.445 ;
     RECT  2.16 203.715 213.84 203.985 ;
     RECT  2.16 204.255 213.84 204.525 ;
     RECT  2.16 204.795 213.84 205.065 ;
     RECT  2.16 205.335 213.84 205.605 ;
     RECT  2.16 205.875 213.84 206.145 ;
     RECT  2.16 206.415 213.84 206.685 ;
     RECT  2.16 206.955 213.84 207.225 ;
     RECT  2.16 207.495 213.84 207.765 ;
     RECT  2.16 208.035 213.84 208.305 ;
     RECT  2.16 208.575 213.84 208.845 ;
     RECT  2.16 209.115 213.84 209.385 ;
     RECT  2.16 209.655 213.84 209.925 ;
     RECT  2.16 210.195 213.84 210.465 ;
     RECT  2.16 210.735 213.84 211.005 ;
     RECT  2.16 211.275 213.84 211.545 ;
     RECT  2.16 211.815 213.84 212.085 ;
     RECT  2.16 212.355 213.84 212.625 ;
     RECT  2.16 212.895 213.84 213.165 ;
     RECT  2.16 213.435 213.84 213.705 ;
    LAYER M1 ;
     RECT  2.16 2.151 213.84 213.849 ;
    LAYER M2 ;
     RECT  0.031 103.248 0.067 103.266 ;
     RECT  0.067 104.868 0.103 104.886 ;
     RECT  0.031 114.471 0.103 114.489 ;
     RECT  0.067 102.636 0.131 103.266 ;
     RECT  0.103 114.471 0.139 114.804 ;
     RECT  0.031 115.596 0.139 115.614 ;
     RECT  0.131 102.636 0.167 102.726 ;
     RECT  0.103 104.868 0.167 105.156 ;
     RECT  0.067 99.702 0.175 99.72 ;
     RECT  0.139 110.538 0.175 110.556 ;
     RECT  0.031 98.622 0.211 98.64 ;
     RECT  0.167 102.636 0.275 102.654 ;
     RECT  0.167 104.94 0.427 105.156 ;
     RECT  0.103 106.146 0.427 106.164 ;
     RECT  0.427 104.94 0.463 106.164 ;
     RECT  0.463 104.94 0.535 106.506 ;
     RECT  0.175 110.502 0.535 110.556 ;
     RECT  0.139 114.471 0.571 115.614 ;
     RECT  0.139 101.124 1.147 101.142 ;
     RECT  0.535 104.94 1.147 106.884 ;
     RECT  1.147 101.124 1.175 101.214 ;
     RECT  0.571 114.048 1.219 115.614 ;
     RECT  1.147 104.94 1.723 107.388 ;
     RECT  0.139 108.216 1.723 108.234 ;
     RECT  0.211 98.622 2.16 98.91 ;
     RECT  0.175 99.702 2.16 100.062 ;
     RECT  1.175 101.196 2.16 101.214 ;
     RECT  1.723 104.94 2.16 108.234 ;
     RECT  0.535 109.026 2.16 109.044 ;
     RECT  0.535 110.106 2.16 110.556 ;
     RECT  0.139 111.618 2.16 111.636 ;
     RECT  1.219 113.886 2.16 115.614 ;
     RECT  2.16 2.151 96.691 213.849 ;
     RECT  96.691 2.106 97.043 213.849 ;
     RECT  97.043 2.151 99.499 213.849 ;
     RECT  99.499 2.106 100.355 213.849 ;
     RECT  100.355 2.151 102.271 213.849 ;
     RECT  102.271 2.106 103.199 213.849 ;
     RECT  103.199 2.151 104.287 213.849 ;
     RECT  104.287 2.106 104.971 213.849 ;
     RECT  104.971 2.034 106.727 213.849 ;
     RECT  106.727 2.106 108.059 213.849 ;
     RECT  108.391 0.108 108.607 0.126 ;
     RECT  108.607 0.108 109.075 0.198 ;
     RECT  108.059 2.151 116.851 213.849 ;
     RECT  109.075 0.036 118.579 0.198 ;
     RECT  116.851 2.106 119.363 213.849 ;
     RECT  120.847 1.152 120.947 1.17 ;
     RECT  119.363 2.151 121.063 213.849 ;
     RECT  121.063 2.106 121.595 213.849 ;
     RECT  121.595 2.151 122.611 213.849 ;
     RECT  118.579 0.036 123.215 0.279 ;
     RECT  123.215 0.18 123.251 0.279 ;
     RECT  122.611 2.106 124.087 213.849 ;
     RECT  124.087 2.07 124.295 213.849 ;
     RECT  124.295 2.106 124.799 213.849 ;
     RECT  123.251 0.18 125.447 0.198 ;
     RECT  124.799 2.151 213.84 213.849 ;
    LAYER M3 ;
     RECT  109.08 0.031 109.098 0.067 ;
     RECT  123.192 0.031 123.21 0.067 ;
     RECT  109.08 0.067 109.566 0.091 ;
     RECT  123.156 0.067 123.21 0.091 ;
     RECT  108.216 0.091 109.854 0.125 ;
     RECT  119.268 0.091 119.286 0.139 ;
     RECT  120.636 0.091 120.654 0.139 ;
     RECT  122.004 0.103 122.022 0.139 ;
     RECT  109.656 0.125 109.854 0.167 ;
     RECT  98.1 0.043 98.118 0.173 ;
     RECT  118.584 0.139 119.286 0.175 ;
     RECT  120.42 0.139 122.058 0.175 ;
     RECT  94.752 0.091 94.77 0.187 ;
     RECT  99.972 0.091 99.99 0.187 ;
     RECT  118.584 0.175 122.058 0.187 ;
     RECT  118.332 0.187 122.058 0.203 ;
     RECT  103.248 0.091 103.806 0.221 ;
     RECT  94.644 0.187 94.77 0.235 ;
     RECT  118.332 0.203 119.79 0.284 ;
     RECT  99.576 0.187 99.99 0.317 ;
     RECT  92.628 0.091 92.646 0.523 ;
     RECT  108.216 0.125 108.702 0.523 ;
     RECT  94.644 0.235 95.058 0.571 ;
     RECT  123.156 0.091 123.75 0.859 ;
     RECT  92.628 0.523 93.114 1.051 ;
     RECT  94.14 0.571 95.058 1.051 ;
     RECT  96.048 0.091 96.066 1.099 ;
     RECT  96.948 0.091 96.966 1.099 ;
     RECT  105.336 0.091 105.354 1.099 ;
     RECT  111.276 0.091 111.69 1.099 ;
     RECT  119.268 0.284 119.79 1.099 ;
     RECT  103.248 0.221 103.266 1.147 ;
     RECT  113.004 1.147 113.022 1.325 ;
     RECT  92.628 1.051 95.058 1.723 ;
     RECT  96.048 1.099 96.966 1.723 ;
     RECT  102.24 1.099 102.258 1.723 ;
     RECT  103.248 1.147 103.626 1.723 ;
     RECT  104.436 1.099 104.454 1.723 ;
     RECT  105.336 1.099 105.606 1.723 ;
     RECT  107.532 0.523 108.702 1.723 ;
     RECT  109.656 0.167 109.674 1.723 ;
     RECT  110.808 1.099 111.69 1.723 ;
     RECT  114.732 0.091 114.75 1.723 ;
     RECT  117.432 0.811 117.45 1.723 ;
     RECT  101.844 1.723 103.626 1.771 ;
     RECT  107.172 1.723 108.702 1.771 ;
     RECT  109.656 1.723 109.89 1.771 ;
     RECT  110.736 1.723 111.69 1.771 ;
     RECT  114.084 1.723 114.75 1.771 ;
     RECT  115.74 1.723 115.866 1.771 ;
     RECT  117.288 1.723 117.45 1.771 ;
     RECT  120.636 0.203 122.058 1.771 ;
     RECT  123.156 0.859 124.254 1.771 ;
     RECT  125.424 0.175 125.442 1.771 ;
     RECT  101.556 1.771 103.626 1.819 ;
     RECT  114.084 1.771 114.858 1.819 ;
     RECT  115.74 1.771 115.974 1.819 ;
     RECT  117.288 1.771 117.486 1.819 ;
     RECT  118.332 0.284 118.35 1.819 ;
     RECT  117.288 1.819 118.35 1.867 ;
     RECT  115.74 1.819 116.046 1.915 ;
     RECT  104.436 1.723 105.606 2.059 ;
     RECT  106.38 1.771 109.89 2.059 ;
     RECT  120.636 1.771 124.254 2.059 ;
     RECT  125.208 1.771 125.442 2.059 ;
     RECT  99.396 1.723 99.414 2.101 ;
     RECT  100.152 1.723 100.17 2.101 ;
     RECT  100.908 1.819 103.626 2.101 ;
     RECT  104.436 2.059 109.89 2.101 ;
     RECT  115.74 1.915 116.19 2.101 ;
     RECT  117.036 1.867 118.35 2.101 ;
     RECT  119.124 1.099 119.79 2.101 ;
     RECT  99.396 2.101 109.89 2.143 ;
     RECT  110.736 1.771 112.374 2.143 ;
     RECT  92.628 1.723 98.586 2.191 ;
     RECT  99.396 2.143 112.374 2.191 ;
     RECT  113.292 1.723 113.31 2.191 ;
     RECT  114.084 1.819 115.002 2.191 ;
     RECT  115.74 2.101 119.79 2.191 ;
     RECT  120.636 2.059 125.442 2.191 ;
     RECT  92.556 2.191 112.374 2.227 ;
     RECT  91.872 2.227 112.374 2.263 ;
     RECT  113.292 2.191 115.002 2.263 ;
     RECT  91.872 2.263 115.002 2.371 ;
     RECT  115.74 2.191 125.766 2.371 ;
     RECT  91.836 2.371 125.802 2.395 ;
     RECT  2.415 2.143 2.505 2.413 ;
     RECT  7.815 2.143 7.905 2.413 ;
     RECT  13.215 2.143 13.305 2.413 ;
     RECT  18.615 2.143 18.705 2.413 ;
     RECT  24.015 2.143 24.105 2.413 ;
     RECT  29.415 2.143 29.505 2.413 ;
     RECT  34.815 2.143 34.905 2.413 ;
     RECT  40.215 2.143 40.305 2.413 ;
     RECT  45.615 2.143 45.705 2.413 ;
     RECT  51.015 2.143 51.105 2.413 ;
     RECT  56.415 2.143 56.505 2.413 ;
     RECT  61.815 2.143 61.905 2.413 ;
     RECT  67.215 2.143 67.305 2.413 ;
     RECT  72.615 2.143 72.705 2.413 ;
     RECT  78.015 2.143 78.105 2.413 ;
     RECT  83.415 2.143 83.505 2.413 ;
     RECT  88.815 2.143 88.905 2.413 ;
     RECT  126.615 2.143 126.705 2.413 ;
     RECT  132.015 2.143 132.105 2.413 ;
     RECT  137.415 2.143 137.505 2.413 ;
     RECT  142.815 2.143 142.905 2.413 ;
     RECT  148.215 2.143 148.305 2.413 ;
     RECT  153.615 2.143 153.705 2.413 ;
     RECT  159.015 2.143 159.105 2.413 ;
     RECT  164.415 2.143 164.505 2.413 ;
     RECT  169.815 2.143 169.905 2.413 ;
     RECT  175.215 2.143 175.305 2.413 ;
     RECT  180.615 2.143 180.705 2.413 ;
     RECT  186.015 2.143 186.105 2.413 ;
     RECT  191.415 2.143 191.505 2.413 ;
     RECT  196.815 2.143 196.905 2.413 ;
     RECT  202.215 2.143 202.305 2.413 ;
     RECT  207.615 2.143 207.705 2.413 ;
     RECT  213.015 2.143 213.105 2.413 ;
     RECT  91.836 2.395 125.874 2.569 ;
     RECT  91.476 2.569 125.874 2.641 ;
     RECT  91.44 2.641 125.874 2.731 ;
     RECT  126.615 2.413 126.897 2.731 ;
     RECT  91.152 2.731 126.897 3.109 ;
     RECT  91.044 3.109 126.897 3.307 ;
     RECT  90.864 3.307 126.897 3.451 ;
     RECT  88.815 2.413 89.097 4.117 ;
     RECT  90 3.955 90.018 4.117 ;
     RECT  88.704 4.117 90.018 4.123 ;
     RECT  90.792 3.451 126.897 4.123 ;
     RECT  88.704 4.123 126.897 4.657 ;
     RECT  87.12 4.729 87.138 4.801 ;
     RECT  87.948 4.657 126.897 4.801 ;
     RECT  87.12 4.801 126.897 5.071 ;
     RECT  86.076 5.083 86.094 5.341 ;
     RECT  86.832 5.071 126.897 5.341 ;
     RECT  86.076 5.341 126.897 5.765 ;
     RECT  86.22 5.765 126.897 6.269 ;
     RECT  86.688 6.269 126.897 7.189 ;
     RECT  86.004 7.189 126.897 7.229 ;
     RECT  86.148 7.229 126.897 7.349 ;
     RECT  86.256 7.349 126.897 8.437 ;
     RECT  86.112 8.437 126.897 8.573 ;
     RECT  86.364 8.573 126.897 9.239 ;
     RECT  85.788 9.307 85.806 9.383 ;
     RECT  86.616 9.239 126.897 9.383 ;
     RECT  86.652 9.383 126.897 10.315 ;
     RECT  86.148 10.315 126.897 10.319 ;
     RECT  86.148 10.319 86.922 10.391 ;
     RECT  86.724 10.391 86.922 10.427 ;
     RECT  86.904 10.427 86.922 10.463 ;
     RECT  88.092 10.319 126.897 11.515 ;
     RECT  87.732 11.515 126.897 11.975 ;
     RECT  87.84 11.975 126.897 11.981 ;
     RECT  88.092 11.981 126.897 12.901 ;
     RECT  87.444 12.901 126.897 13.003 ;
     RECT  87.3 13.003 126.897 13.019 ;
     RECT  87.3 13.019 87.318 13.055 ;
     RECT  88.092 13.019 126.897 14.071 ;
     RECT  87.84 14.071 126.897 14.405 ;
     RECT  88.092 14.405 126.897 15.871 ;
     RECT  87.876 15.871 126.897 16.979 ;
     RECT  87.876 16.979 125.766 19.841 ;
     RECT  87.876 19.841 124.614 21.389 ;
     RECT  87.876 21.389 124.506 22.199 ;
     RECT  125.352 19.841 125.766 23.657 ;
     RECT  88.092 22.199 124.506 23.971 ;
     RECT  88.092 23.971 124.83 24.665 ;
     RECT  125.748 23.657 125.766 24.773 ;
     RECT  88.092 24.665 124.758 25.709 ;
     RECT  88.092 25.709 124.398 25.745 ;
     RECT  88.092 25.745 124.074 25.781 ;
     RECT  83.415 2.413 83.697 26.635 ;
     RECT  83.415 26.635 83.79 26.765 ;
     RECT  88.092 25.781 124.002 27.671 ;
     RECT  88.164 27.671 124.002 27.941 ;
     RECT  88.164 27.941 122.274 28.211 ;
     RECT  88.164 28.211 122.022 28.409 ;
     RECT  88.164 28.409 121.914 28.679 ;
     RECT  123.012 27.941 124.002 28.715 ;
     RECT  88.164 28.679 121.497 28.787 ;
     RECT  88.164 28.787 119.646 28.823 ;
     RECT  88.164 28.823 116.55 28.831 ;
     RECT  117.324 28.823 119.646 29.021 ;
     RECT  88.056 28.831 116.55 29.219 ;
     RECT  123.012 28.715 123.786 29.227 ;
     RECT  120.564 28.787 121.497 29.261 ;
     RECT  122.832 29.227 123.786 29.335 ;
     RECT  113.04 29.219 116.55 29.489 ;
     RECT  117.684 29.021 119.646 29.489 ;
     RECT  122.616 29.335 123.786 29.561 ;
     RECT  122.616 29.561 123.03 29.597 ;
     RECT  117.684 29.489 119.61 29.669 ;
     RECT  123.012 29.597 123.03 29.759 ;
     RECT  124.092 29.641 124.11 29.939 ;
     RECT  88.056 29.219 112.302 30.029 ;
     RECT  113.04 29.489 116.097 30.029 ;
     RECT  113.04 30.029 114.426 30.037 ;
     RECT  88.056 30.029 111.618 30.077 ;
     RECT  112.896 30.037 114.426 30.077 ;
     RECT  113.544 30.077 113.562 30.137 ;
     RECT  118.476 29.669 119.61 30.137 ;
     RECT  117.684 29.669 117.702 30.209 ;
     RECT  119.556 30.137 119.61 30.335 ;
     RECT  88.056 30.077 111.15 30.343 ;
     RECT  118.476 30.137 118.494 30.371 ;
     RECT  85.752 29.875 85.77 30.379 ;
     RECT  120.816 29.261 121.497 30.413 ;
     RECT  87.804 30.343 111.15 30.415 ;
     RECT  87.696 30.415 111.15 30.479 ;
     RECT  87.696 30.479 111.042 30.641 ;
     RECT  97.992 30.641 111.042 30.713 ;
     RECT  119.592 30.335 119.61 30.713 ;
     RECT  97.992 30.713 110.826 30.755 ;
     RECT  97.992 30.755 104.166 30.839 ;
     RECT  104.94 30.755 110.826 30.839 ;
     RECT  97.992 30.839 101.898 30.875 ;
     RECT  103.32 30.839 104.166 30.875 ;
     RECT  103.32 30.875 103.662 30.941 ;
     RECT  98.28 30.875 101.898 30.983 ;
     RECT  104.94 30.839 105.75 30.983 ;
     RECT  87.696 30.641 97.074 30.989 ;
     RECT  87.696 30.989 96.57 30.991 ;
     RECT  103.644 30.941 103.662 31.019 ;
     RECT  106.596 30.839 106.614 31.037 ;
     RECT  87.66 30.991 96.57 31.081 ;
     RECT  100.656 30.983 101.898 31.109 ;
     RECT  107.928 30.839 110.697 31.109 ;
     RECT  85.752 30.379 86.31 31.153 ;
     RECT  101.052 31.109 101.61 31.181 ;
     RECT  87.192 31.081 96.57 31.217 ;
     RECT  108.144 31.109 110.697 31.253 ;
     RECT  85.032 31.153 86.31 31.261 ;
     RECT  87.192 31.217 95.238 31.261 ;
     RECT  101.052 31.181 101.07 31.289 ;
     RECT  104.94 30.983 105.297 31.289 ;
     RECT  108.144 31.253 109.026 31.379 ;
     RECT  108.144 31.379 108.162 31.415 ;
     RECT  109.836 31.253 110.697 31.415 ;
     RECT  95.976 31.217 96.57 31.487 ;
     RECT  109.98 31.415 110.697 31.487 ;
     RECT  115.164 30.029 116.097 31.559 ;
     RECT  95.976 31.487 96.318 31.649 ;
     RECT  98.316 30.983 99.897 31.757 ;
     RECT  85.032 31.261 95.238 32.071 ;
     RECT  95.976 31.649 96.174 32.071 ;
     RECT  85.032 32.071 96.174 32.189 ;
     RECT  85.032 32.189 95.238 32.197 ;
     RECT  84.708 32.197 95.238 32.261 ;
     RECT  84.708 32.261 95.13 32.495 ;
     RECT  84.708 32.495 95.022 33.413 ;
     RECT  101.124 33.781 101.142 33.821 ;
     RECT  98.316 31.757 98.874 33.961 ;
     RECT  99.615 31.757 99.897 33.961 ;
     RECT  98.316 33.961 99.897 34.219 ;
     RECT  101.196 34.027 101.502 34.253 ;
     RECT  101.196 34.253 101.214 34.397 ;
     RECT  13.215 2.413 13.497 34.591 ;
     RECT  24.015 2.413 24.297 34.591 ;
     RECT  34.815 2.413 35.097 34.591 ;
     RECT  45.615 2.413 45.897 34.591 ;
     RECT  56.415 2.413 56.697 34.591 ;
     RECT  70.056 33.889 70.074 34.591 ;
     RECT  67.215 2.413 67.497 34.603 ;
     RECT  13.104 34.591 13.497 34.637 ;
     RECT  23.904 34.591 24.297 34.637 ;
     RECT  34.704 34.591 35.097 34.637 ;
     RECT  45.504 34.591 45.897 34.637 ;
     RECT  56.304 34.591 56.697 34.637 ;
     RECT  69.48 34.591 70.146 34.685 ;
     RECT  98.316 34.219 99.99 34.685 ;
     RECT  93.708 33.413 95.022 34.691 ;
     RECT  66.708 34.603 67.497 34.733 ;
     RECT  70.056 34.685 70.146 34.733 ;
     RECT  93.852 34.691 95.022 34.763 ;
     RECT  99.615 34.685 99.99 34.795 ;
     RECT  99.615 34.795 100.386 35.041 ;
     RECT  84.708 33.413 92.934 35.069 ;
     RECT  99.615 35.041 100.746 35.699 ;
     RECT  99.615 35.699 100.674 35.969 ;
     RECT  99.615 35.969 100.314 36.083 ;
     RECT  98.316 34.685 98.874 37.895 ;
     RECT  99.615 36.083 99.897 38.011 ;
     RECT  83.415 26.765 83.697 38.911 ;
     RECT  83.415 38.911 83.79 38.957 ;
     RECT  81.9 38.821 81.918 39.149 ;
     RECT  98.424 37.895 98.874 39.865 ;
     RECT  99.615 38.011 100.566 39.865 ;
     RECT  105.015 31.289 105.297 40.171 ;
     RECT  105.015 40.171 105.606 40.261 ;
     RECT  105.015 40.261 106.002 40.301 ;
     RECT  107.136 40.171 107.154 40.301 ;
     RECT  114.588 40.123 114.606 40.301 ;
     RECT  105.015 40.301 105.966 40.559 ;
     RECT  105.015 40.559 105.606 40.781 ;
     RECT  84.708 35.069 92.754 40.901 ;
     RECT  98.424 39.865 100.566 42.215 ;
     RECT  98.604 42.215 100.566 43.097 ;
     RECT  98.604 43.097 99.897 43.169 ;
     RECT  96.156 32.189 96.174 57.541 ;
     RECT  83.415 38.957 83.697 57.547 ;
     RECT  97.812 57.019 97.83 57.569 ;
     RECT  83.415 57.547 83.79 57.641 ;
     RECT  66.384 57.811 66.402 57.869 ;
     RECT  66.06 57.919 66.078 57.965 ;
     RECT  96.156 57.541 96.786 57.979 ;
     RECT  96.156 57.979 96.858 58.109 ;
     RECT  96.156 58.109 96.534 58.157 ;
     RECT  79.884 59.275 79.902 59.729 ;
     RECT  75.888 42.961 75.906 60.269 ;
     RECT  7.815 2.413 8.097 60.277 ;
     RECT  75.816 60.277 75.834 60.449 ;
     RECT  93.852 34.763 94.986 63.067 ;
     RECT  93.492 63.067 94.986 63.239 ;
     RECT  93.816 63.239 94.986 63.245 ;
     RECT  102.6 63.067 102.618 63.245 ;
     RECT  57.42 35.131 57.438 63.275 ;
     RECT  51.015 2.413 51.297 66.139 ;
     RECT  56.415 34.637 56.697 66.139 ;
     RECT  57.564 63.391 57.582 66.139 ;
     RECT  51.015 66.139 51.39 66.181 ;
     RECT  55.584 66.139 55.602 66.209 ;
     RECT  56.415 66.139 57.582 66.209 ;
     RECT  50.508 66.181 51.39 66.221 ;
     RECT  51.015 66.221 51.39 66.269 ;
     RECT  50.184 66.235 50.202 66.281 ;
     RECT  84.708 40.901 91.242 69.719 ;
     RECT  57.564 66.209 57.582 71.275 ;
     RECT  57.564 71.275 57.726 71.581 ;
     RECT  57.564 71.581 58.014 71.645 ;
     RECT  93.852 63.245 94.986 73.769 ;
     RECT  84.708 69.719 90.846 74.659 ;
     RECT  6.552 77.512 6.57 77.549 ;
     RECT  99.072 43.169 99.897 77.803 ;
     RECT  98.604 77.803 99.897 77.933 ;
     RECT  5.436 77.701 5.454 78.077 ;
     RECT  84.708 74.659 90.918 78.161 ;
     RECT  83.415 57.641 83.697 78.169 ;
     RECT  84.708 78.161 90.846 78.169 ;
     RECT  82.656 78.169 82.674 78.269 ;
     RECT  35.928 78.241 35.946 78.359 ;
     RECT  34.815 34.637 35.097 78.475 ;
     RECT  83.415 78.169 90.846 78.653 ;
     RECT  10.908 81.499 10.926 81.599 ;
     RECT  10.548 81.751 10.566 81.821 ;
     RECT  100.944 82.651 100.962 82.688 ;
     RECT  100.62 82.789 100.638 82.829 ;
     RECT  7.815 60.277 8.766 86.431 ;
     RECT  92.016 40.901 92.754 86.459 ;
     RECT  99.072 77.933 99.897 86.635 ;
     RECT  99.072 86.635 100.386 86.729 ;
     RECT  101.916 86.881 101.934 87.197 ;
     RECT  78.015 2.413 78.297 87.259 ;
     RECT  78.015 87.259 78.606 87.305 ;
     RECT  77.04 87.421 77.058 87.773 ;
     RECT  78.015 87.305 78.297 89.563 ;
     RECT  77.904 89.563 78.297 89.609 ;
     RECT  61.815 2.413 62.097 89.707 ;
     RECT  82.656 89.563 82.674 89.741 ;
     RECT  65.844 89.707 65.862 89.744 ;
     RECT  61.815 89.707 62.73 89.837 ;
     RECT  66.168 89.803 66.186 89.879 ;
     RECT  80.856 91.387 80.874 91.427 ;
     RECT  82.62 91.339 82.638 91.471 ;
     RECT  82.404 91.471 82.638 91.517 ;
     RECT  30.636 43.069 30.654 91.859 ;
     RECT  28.512 92.011 28.53 93.209 ;
     RECT  7.815 86.431 8.874 95.341 ;
     RECT  9.756 40.801 9.774 95.341 ;
     RECT  7.815 95.341 9.774 95.405 ;
     RECT  24.015 34.637 24.297 95.512 ;
     RECT  34.815 78.475 35.694 95.512 ;
     RECT  45.615 34.637 45.897 95.512 ;
     RECT  56.415 66.209 56.697 95.512 ;
     RECT  67.215 34.733 67.497 95.512 ;
     RECT  78.015 89.609 78.297 95.512 ;
     RECT  23.904 95.512 24.297 95.549 ;
     RECT  34.704 95.512 35.694 95.549 ;
     RECT  45.504 95.512 45.897 95.549 ;
     RECT  56.304 95.512 56.697 95.549 ;
     RECT  67.104 95.512 67.497 95.549 ;
     RECT  77.904 95.512 78.297 95.549 ;
     RECT  15.588 95.371 15.606 95.639 ;
     RECT  16.704 95.647 16.722 95.693 ;
     RECT  0.036 98.617 0.054 98.887 ;
     RECT  2.415 2.413 2.697 99.931 ;
     RECT  5.184 99.931 5.202 100.003 ;
     RECT  5.004 100.003 5.202 100.039 ;
     RECT  2.415 99.931 2.862 100.067 ;
     RECT  4.896 100.039 5.202 100.069 ;
     RECT  92.016 86.459 92.61 100.139 ;
     RECT  27.756 100.315 27.774 100.507 ;
     RECT  6.156 93.181 6.174 100.543 ;
     RECT  70.056 34.733 70.074 100.543 ;
     RECT  7.815 95.405 8.874 100.615 ;
     RECT  4.824 100.069 5.202 100.645 ;
     RECT  3.6 100.615 3.618 100.651 ;
     RECT  4.536 100.645 5.202 100.651 ;
     RECT  6.156 100.543 6.246 100.651 ;
     RECT  82.656 100.507 82.674 100.679 ;
     RECT  15.552 100.651 15.57 100.769 ;
     RECT  27.396 100.507 27.774 100.769 ;
     RECT  84.708 78.653 90.846 100.769 ;
     RECT  3.6 100.651 6.246 100.777 ;
     RECT  83.415 78.653 83.697 100.777 ;
     RECT  84.708 100.769 90.558 100.777 ;
     RECT  92.016 100.139 92.07 100.805 ;
     RECT  3.528 100.777 6.246 100.921 ;
     RECT  3.528 100.921 6.426 101.011 ;
     RECT  69.804 100.543 70.074 101.039 ;
     RECT  1.152 101.119 1.17 101.219 ;
     RECT  69.876 101.039 69.894 101.381 ;
     RECT  2.415 100.067 2.697 101.425 ;
     RECT  3.528 101.011 6.57 101.425 ;
     RECT  83.415 100.777 90.558 101.611 ;
     RECT  83.34 101.611 90.558 101.651 ;
     RECT  2.415 101.425 6.678 101.695 ;
     RECT  2.304 101.695 6.678 101.731 ;
     RECT  7.776 100.615 8.874 101.731 ;
     RECT  2.304 101.731 8.874 102.119 ;
     RECT  0.036 98.887 0.234 102.631 ;
     RECT  9.756 95.405 9.774 102.631 ;
     RECT  9.756 102.631 9.846 102.659 ;
     RECT  83.415 101.651 90.558 103.001 ;
     RECT  82.656 102.433 82.674 103.073 ;
     RECT  41.904 103.171 41.922 103.207 ;
     RECT  41.724 103.207 41.922 103.229 ;
     RECT  0.036 102.631 0.27 103.271 ;
     RECT  41.724 103.229 41.742 103.277 ;
     RECT  83.415 103.001 84.078 103.855 ;
     RECT  83.304 103.855 84.078 103.891 ;
     RECT  84.816 103.001 90.558 103.891 ;
     RECT  92.052 100.805 92.07 103.891 ;
     RECT  91.44 103.891 92.07 104.009 ;
     RECT  96.156 58.157 96.174 104.045 ;
     RECT  13.215 34.637 13.497 104.152 ;
     RECT  24.015 95.549 24.297 104.152 ;
     RECT  34.815 95.549 35.694 104.152 ;
     RECT  83.304 103.891 90.558 104.153 ;
     RECT  83.304 104.153 83.79 104.161 ;
     RECT  13.104 104.152 13.497 104.189 ;
     RECT  23.904 104.152 24.297 104.189 ;
     RECT  34.704 104.152 35.694 104.189 ;
     RECT  38.772 104.059 38.79 104.189 ;
     RECT  0.072 103.271 0.27 104.203 ;
     RECT  41.724 104.059 41.742 104.251 ;
     RECT  45.615 95.549 45.897 104.251 ;
     RECT  56.415 95.549 56.697 104.251 ;
     RECT  67.215 95.549 67.497 104.251 ;
     RECT  78.015 95.549 78.297 104.251 ;
     RECT  41.724 104.251 41.922 104.288 ;
     RECT  34.815 104.189 35.694 104.549 ;
     RECT  83.268 104.161 83.79 104.557 ;
     RECT  41.724 104.288 41.814 104.683 ;
     RECT  83.088 104.557 83.79 104.683 ;
     RECT  2.304 102.119 8.766 104.701 ;
     RECT  9.828 102.659 9.846 104.701 ;
     RECT  82.764 104.683 83.79 104.701 ;
     RECT  45.504 104.251 45.897 104.729 ;
     RECT  56.304 104.251 56.697 104.729 ;
     RECT  67.104 104.251 67.497 104.729 ;
     RECT  77.904 104.251 78.297 104.729 ;
     RECT  2.304 104.701 10.386 104.819 ;
     RECT  0.072 104.203 0.342 104.891 ;
     RECT  82.692 104.701 83.79 104.891 ;
     RECT  41.652 104.683 41.814 104.923 ;
     RECT  0.108 104.891 0.342 104.935 ;
     RECT  0.108 104.935 0.486 104.971 ;
     RECT  2.304 104.819 10.242 105.125 ;
     RECT  99.072 86.729 99.897 105.133 ;
     RECT  98.604 105.133 99.897 105.161 ;
     RECT  0.108 104.971 0.558 105.197 ;
     RECT  41.436 104.923 41.814 105.211 ;
     RECT  83.415 104.891 83.79 105.211 ;
     RECT  41.436 105.211 42.21 105.355 ;
     RECT  2.304 105.125 10.098 105.359 ;
     RECT  84.816 104.153 90.558 105.359 ;
     RECT  97.128 104.971 97.146 105.359 ;
     RECT  85.176 105.359 90.558 105.389 ;
     RECT  41.436 105.355 42.858 105.395 ;
     RECT  83.415 105.211 83.862 105.395 ;
     RECT  41.976 105.395 42.858 105.403 ;
     RECT  98.604 105.161 98.622 105.431 ;
     RECT  41.976 105.403 43.326 105.629 ;
     RECT  82.656 105.511 82.674 105.709 ;
     RECT  83.415 105.395 83.697 105.709 ;
     RECT  38.772 105.475 38.79 105.737 ;
     RECT  42.84 105.629 43.326 105.737 ;
     RECT  42.948 105.737 43.326 105.773 ;
     RECT  85.392 105.389 90.558 105.809 ;
     RECT  56.415 104.729 56.697 105.871 ;
     RECT  67.215 104.729 67.497 105.871 ;
     RECT  78.015 104.729 78.297 105.871 ;
     RECT  85.392 105.809 89.766 105.899 ;
     RECT  82.656 105.709 83.697 105.917 ;
     RECT  2.304 105.359 9.774 105.935 ;
     RECT  41.976 105.629 41.994 105.965 ;
     RECT  0.144 105.197 0.558 106.141 ;
     RECT  46.728 105.883 46.746 106.171 ;
     RECT  43.02 105.773 43.326 106.219 ;
     RECT  44.136 106.171 44.37 106.219 ;
     RECT  46.656 106.171 46.746 106.267 ;
     RECT  82.656 105.917 82.674 106.277 ;
     RECT  13.215 104.189 13.497 106.312 ;
     RECT  24.015 104.189 24.297 106.312 ;
     RECT  34.815 104.549 35.097 106.312 ;
     RECT  45.615 104.729 45.897 106.315 ;
     RECT  46.656 106.267 46.89 106.315 ;
     RECT  1.404 105.979 1.422 106.321 ;
     RECT  13.104 106.312 13.497 106.349 ;
     RECT  23.904 106.312 24.297 106.349 ;
     RECT  34.704 106.312 35.097 106.349 ;
     RECT  43.02 106.219 44.37 106.439 ;
     RECT  85.392 105.899 89.73 106.439 ;
     RECT  56.304 105.871 56.697 106.448 ;
     RECT  67.104 105.871 67.497 106.448 ;
     RECT  77.904 105.871 78.297 106.448 ;
     RECT  85.392 106.439 85.914 106.541 ;
     RECT  45.615 106.315 46.89 106.589 ;
     RECT  85.392 106.541 85.806 106.589 ;
     RECT  85.392 106.589 85.41 106.709 ;
     RECT  2.34 105.935 9.774 106.795 ;
     RECT  10.908 106.747 10.926 106.795 ;
     RECT  14.904 106.747 14.922 106.795 ;
     RECT  22.896 106.747 22.914 106.795 ;
     RECT  29.415 2.413 29.697 106.795 ;
     RECT  34.815 106.349 35.097 106.795 ;
     RECT  38.88 106.315 38.898 106.795 ;
     RECT  43.02 106.439 44.298 106.795 ;
     RECT  2.304 106.795 9.774 106.825 ;
     RECT  84.96 106.789 84.978 106.829 ;
     RECT  38.808 106.795 38.898 106.843 ;
     RECT  10.836 106.795 10.926 106.877 ;
     RECT  22.824 106.795 22.914 106.877 ;
     RECT  30.78 106.747 30.798 106.877 ;
     RECT  38.808 106.843 38.934 106.891 ;
     RECT  10.836 106.877 10.854 106.925 ;
     RECT  14.832 106.795 14.922 106.925 ;
     RECT  22.824 106.877 22.842 106.925 ;
     RECT  26.784 106.795 26.802 106.925 ;
     RECT  1.404 106.321 1.458 106.939 ;
     RECT  2.196 106.825 9.774 106.939 ;
     RECT  42.624 106.795 44.298 106.979 ;
     RECT  90.54 105.809 90.558 106.979 ;
     RECT  42.624 106.979 44.19 106.987 ;
     RECT  1.404 106.939 9.774 107.015 ;
     RECT  14.904 106.925 14.922 107.021 ;
     RECT  30.96 106.891 30.978 107.021 ;
     RECT  38.808 106.891 39.006 107.021 ;
     RECT  2.196 107.015 9.774 107.023 ;
     RECT  38.808 107.021 38.934 107.023 ;
     RECT  42.516 106.987 44.19 107.024 ;
     RECT  38.772 107.023 38.934 107.069 ;
     RECT  42.948 107.024 44.19 107.069 ;
     RECT  0.108 106.141 0.558 107.117 ;
     RECT  29.415 106.795 29.718 107.117 ;
     RECT  34.815 106.795 35.226 107.117 ;
     RECT  43.488 107.069 44.19 107.117 ;
     RECT  38.772 107.069 38.79 107.123 ;
     RECT  86.652 106.439 89.73 107.123 ;
     RECT  87.048 107.123 89.73 107.249 ;
     RECT  0.144 107.117 0.558 107.365 ;
     RECT  1.404 107.015 1.458 107.365 ;
     RECT  43.596 107.117 44.19 107.405 ;
     RECT  57.564 71.645 57.582 107.429 ;
     RECT  2.196 107.023 9.954 107.519 ;
     RECT  43.992 107.405 44.19 107.549 ;
     RECT  87.048 107.249 87.894 107.549 ;
     RECT  43.992 107.549 44.01 107.555 ;
     RECT  0.144 107.365 1.458 108.103 ;
     RECT  2.196 107.519 9.774 108.103 ;
     RECT  0.144 108.103 9.774 108.269 ;
     RECT  87.048 107.549 87.39 108.329 ;
     RECT  1.152 108.269 9.774 108.331 ;
     RECT  1.152 108.331 9.882 108.337 ;
     RECT  87.372 108.329 87.39 108.365 ;
     RECT  1.152 108.337 10.602 108.481 ;
     RECT  1.152 108.481 11.142 108.599 ;
     RECT  93.852 73.769 94.497 108.715 ;
     RECT  0.144 108.269 0.162 109.003 ;
     RECT  0.108 109.003 0.162 109.021 ;
     RECT  1.152 108.599 10.602 109.021 ;
     RECT  88.815 107.249 89.73 109.409 ;
     RECT  92.052 109.291 92.07 109.409 ;
     RECT  0.108 109.021 10.602 109.613 ;
     RECT  65.664 109.483 65.682 109.679 ;
     RECT  1.728 109.613 10.602 109.723 ;
     RECT  108.54 109.147 108.558 109.723 ;
     RECT  88.815 109.409 89.514 109.751 ;
     RECT  93.708 108.715 94.497 109.759 ;
     RECT  108.54 109.723 109.242 109.759 ;
     RECT  64.116 109.723 64.134 109.823 ;
     RECT  86.652 109.723 86.67 109.859 ;
     RECT  1.728 109.723 10.854 109.949 ;
     RECT  93.564 109.759 94.497 109.985 ;
     RECT  1.728 109.949 10.602 110.291 ;
     RECT  1.728 110.291 10.242 110.363 ;
     RECT  1.728 110.363 10.098 110.489 ;
     RECT  1.728 110.489 9.99 110.525 ;
     RECT  0.108 109.613 0.558 110.669 ;
     RECT  0.108 110.669 0.27 111.149 ;
     RECT  1.728 110.525 9.918 111.307 ;
     RECT  1.728 111.307 9.954 111.415 ;
     RECT  1.728 111.415 10.314 111.595 ;
     RECT  1.224 111.595 10.314 111.883 ;
     RECT  1.224 111.883 10.386 111.955 ;
     RECT  0.108 111.149 0.234 112.123 ;
     RECT  1.224 111.955 10.71 112.261 ;
     RECT  0.108 112.123 0.27 112.315 ;
     RECT  1.224 112.261 10.926 112.315 ;
     RECT  0.108 112.315 10.926 112.415 ;
     RECT  0.108 112.415 10.71 112.919 ;
     RECT  0.108 112.919 10.206 113.297 ;
     RECT  0.108 113.297 10.062 113.909 ;
     RECT  1.728 113.909 10.062 113.999 ;
     RECT  1.728 113.999 9.918 114.035 ;
     RECT  0.108 113.909 0.594 114.071 ;
     RECT  0.108 114.071 0.234 114.466 ;
     RECT  1.728 114.035 9.162 114.539 ;
     RECT  9.036 114.539 9.09 114.647 ;
     RECT  2.304 114.539 8.154 114.683 ;
     RECT  9.072 114.647 9.09 114.683 ;
     RECT  2.304 114.683 8.097 115.079 ;
     RECT  0.036 114.466 0.234 115.349 ;
     RECT  0.036 115.349 0.162 115.457 ;
     RECT  0.036 115.457 0.054 115.619 ;
     RECT  2.376 115.079 8.097 115.997 ;
     RECT  2.415 115.997 8.097 116.159 ;
     RECT  4.284 116.159 8.097 116.429 ;
     RECT  2.415 116.159 3.51 116.501 ;
     RECT  4.356 116.429 8.097 116.699 ;
     RECT  4.356 116.699 6.894 116.807 ;
     RECT  4.608 116.807 6.642 116.843 ;
     RECT  4.608 116.843 6.246 116.969 ;
     RECT  4.608 116.969 5.67 117.005 ;
     RECT  4.644 117.005 5.454 117.041 ;
     RECT  4.644 117.041 5.058 117.311 ;
     RECT  5.04 117.311 5.058 117.383 ;
     RECT  3.492 116.501 3.51 117.419 ;
     RECT  105.015 40.781 105.297 158.521 ;
     RECT  106.128 105.133 106.146 158.549 ;
     RECT  105.012 158.521 105.297 158.573 ;
     RECT  108.18 109.759 109.242 186.089 ;
     RECT  107.064 186.241 107.082 210.929 ;
     RECT  108.54 186.089 109.242 211.081 ;
     RECT  108.54 211.081 109.602 211.351 ;
     RECT  108.324 211.351 109.602 211.469 ;
     RECT  108.324 211.469 109.422 211.847 ;
     RECT  108.324 211.847 109.386 211.855 ;
     RECT  108.072 211.855 109.386 212.359 ;
     RECT  107.856 212.359 109.386 212.459 ;
     RECT  107.892 212.459 109.386 212.549 ;
     RECT  107.892 212.549 109.17 213.307 ;
     RECT  107.892 213.307 109.314 213.359 ;
     RECT  2.415 116.501 2.697 213.587 ;
     RECT  7.815 116.699 8.097 213.587 ;
     RECT  13.215 106.349 13.497 213.587 ;
     RECT  18.615 2.413 18.897 213.587 ;
     RECT  24.015 106.349 24.297 213.587 ;
     RECT  29.415 107.117 29.697 213.587 ;
     RECT  34.815 107.117 35.097 213.587 ;
     RECT  40.215 2.413 40.497 213.587 ;
     RECT  45.615 106.589 45.897 213.587 ;
     RECT  51.015 66.269 51.297 213.587 ;
     RECT  56.415 106.448 56.697 213.587 ;
     RECT  61.815 89.837 62.097 213.587 ;
     RECT  67.215 106.448 67.497 213.587 ;
     RECT  72.615 2.413 72.897 213.587 ;
     RECT  78.015 106.448 78.297 213.587 ;
     RECT  83.415 105.917 83.697 213.587 ;
     RECT  88.815 109.751 89.097 213.587 ;
     RECT  94.215 109.985 94.497 213.587 ;
     RECT  99.615 105.161 99.897 213.587 ;
     RECT  105.015 158.573 105.297 213.587 ;
     RECT  110.415 31.487 110.697 213.587 ;
     RECT  115.815 31.559 116.097 213.587 ;
     RECT  121.215 30.413 121.497 213.587 ;
     RECT  126.615 16.979 126.897 213.587 ;
     RECT  132.015 2.413 132.297 213.587 ;
     RECT  137.415 2.413 137.697 213.587 ;
     RECT  142.815 2.413 143.097 213.587 ;
     RECT  148.215 2.413 148.497 213.587 ;
     RECT  153.615 2.413 153.897 213.587 ;
     RECT  159.015 2.413 159.297 213.587 ;
     RECT  164.415 2.413 164.697 213.587 ;
     RECT  169.815 2.413 170.097 213.587 ;
     RECT  175.215 2.413 175.497 213.587 ;
     RECT  180.615 2.413 180.897 213.587 ;
     RECT  186.015 2.413 186.297 213.587 ;
     RECT  191.415 2.413 191.697 213.587 ;
     RECT  196.815 2.413 197.097 213.587 ;
     RECT  202.215 2.413 202.497 213.587 ;
     RECT  207.615 2.413 207.897 213.587 ;
     RECT  213.015 2.413 213.297 213.587 ;
     RECT  107.892 213.359 109.242 213.629 ;
     RECT  107.892 213.629 108.45 213.637 ;
     RECT  107.712 213.637 108.45 213.665 ;
     RECT  107.712 213.665 107.982 213.677 ;
     RECT  109.224 213.629 109.242 213.701 ;
     RECT  107.712 213.677 107.73 213.725 ;
     RECT  2.415 213.587 2.505 213.857 ;
     RECT  7.815 213.587 7.905 213.857 ;
     RECT  13.215 213.587 13.305 213.857 ;
     RECT  18.615 213.587 18.705 213.857 ;
     RECT  24.015 213.587 24.105 213.857 ;
     RECT  29.415 213.587 29.505 213.857 ;
     RECT  34.815 213.587 34.905 213.857 ;
     RECT  40.215 213.587 40.305 213.857 ;
     RECT  45.615 213.587 45.705 213.857 ;
     RECT  51.015 213.587 51.105 213.857 ;
     RECT  56.415 213.587 56.505 213.857 ;
     RECT  61.815 213.587 61.905 213.857 ;
     RECT  67.215 213.587 67.305 213.857 ;
     RECT  72.615 213.587 72.705 213.857 ;
     RECT  78.015 213.587 78.105 213.857 ;
     RECT  83.415 213.587 83.505 213.857 ;
     RECT  88.815 213.587 88.905 213.857 ;
     RECT  94.215 213.587 94.305 213.857 ;
     RECT  99.615 213.587 99.705 213.857 ;
     RECT  105.015 213.587 105.105 213.857 ;
     RECT  110.415 213.587 110.505 213.857 ;
     RECT  115.815 213.587 115.905 213.857 ;
     RECT  121.215 213.587 121.305 213.857 ;
     RECT  126.615 213.587 126.705 213.857 ;
     RECT  132.015 213.587 132.105 213.857 ;
     RECT  137.415 213.587 137.505 213.857 ;
     RECT  142.815 213.587 142.905 213.857 ;
     RECT  148.215 213.587 148.305 213.857 ;
     RECT  153.615 213.587 153.705 213.857 ;
     RECT  159.015 213.587 159.105 213.857 ;
     RECT  164.415 213.587 164.505 213.857 ;
     RECT  169.815 213.587 169.905 213.857 ;
     RECT  175.215 213.587 175.305 213.857 ;
     RECT  180.615 213.587 180.705 213.857 ;
     RECT  186.015 213.587 186.105 213.857 ;
     RECT  191.415 213.587 191.505 213.857 ;
     RECT  196.815 213.587 196.905 213.857 ;
     RECT  202.215 213.587 202.305 213.857 ;
     RECT  207.615 213.587 207.705 213.857 ;
     RECT  213.015 213.587 213.105 213.857 ;
    LAYER M4 ;
     RECT  0.06 103.056 0.097 112.968 ;
     RECT  0.097 102.864 0.133 112.968 ;
     RECT  0.133 101.712 0.181 101.736 ;
     RECT  0.133 102.768 0.181 112.968 ;
     RECT  2.221 114.384 2.293 114.408 ;
     RECT  0.181 101.712 2.408 113.064 ;
     RECT  2.293 114.384 2.408 114.84 ;
     RECT  2.408 2.148 2.512 213.852 ;
     RECT  2.512 2.418 2.704 213.582 ;
     RECT  2.704 100.656 2.765 115.752 ;
     RECT  2.765 110.016 2.867 115.752 ;
     RECT  2.867 110.496 3.125 115.752 ;
     RECT  2.765 100.656 3.841 109.032 ;
     RECT  3.841 100.656 4.357 109.56 ;
     RECT  4.357 100.08 4.403 109.56 ;
     RECT  4.403 102.528 4.417 109.56 ;
     RECT  3.125 110.544 4.417 115.752 ;
     RECT  4.405 98.64 4.547 98.664 ;
     RECT  4.403 100.08 4.547 101.544 ;
     RECT  4.417 102.528 4.561 115.752 ;
     RECT  4.547 100.08 4.853 101.448 ;
     RECT  4.561 102.528 4.957 116.04 ;
     RECT  4.957 102.528 5.033 116.808 ;
     RECT  4.853 100.848 5.069 101.448 ;
     RECT  5.425 78.048 5.509 78.072 ;
     RECT  5.033 102.528 5.753 114.696 ;
     RECT  5.069 101.376 5.821 101.448 ;
     RECT  5.753 102.528 5.821 113.88 ;
     RECT  5.033 115.68 5.933 116.808 ;
     RECT  5.821 101.376 6.041 113.88 ;
     RECT  6.041 108.816 6.113 113.88 ;
     RECT  6.113 113.472 6.257 113.88 ;
     RECT  6.113 108.816 6.293 112.392 ;
     RECT  6.041 101.376 6.329 107.688 ;
     RECT  5.933 115.68 6.361 115.992 ;
     RECT  6.361 115.152 6.401 115.992 ;
     RECT  6.401 115.152 6.437 115.752 ;
     RECT  4.501 81.072 6.517 81.096 ;
     RECT  6.329 101.376 6.545 101.4 ;
     RECT  6.437 115.152 6.617 115.176 ;
     RECT  6.541 77.52 6.625 77.544 ;
     RECT  6.293 108.816 6.659 111.864 ;
     RECT  6.329 102.384 7.261 107.688 ;
     RECT  6.659 109.104 7.261 111.864 ;
     RECT  7.261 109.104 7.297 112.296 ;
     RECT  6.257 113.472 7.297 113.832 ;
     RECT  6.565 33.6 7.808 33.624 ;
     RECT  7.669 34.704 7.808 34.728 ;
     RECT  4.837 71.616 7.808 71.64 ;
     RECT  6.517 80.784 7.808 81.096 ;
     RECT  7.261 102.384 7.808 107.88 ;
     RECT  7.297 109.104 7.808 113.832 ;
     RECT  7.808 2.148 7.912 213.852 ;
     RECT  7.912 2.418 8.104 213.582 ;
     RECT  8.104 103.248 8.381 114.6 ;
     RECT  8.104 101.808 8.489 101.832 ;
     RECT  8.381 113.28 8.531 114.6 ;
     RECT  8.531 113.28 8.597 113.784 ;
     RECT  8.381 103.248 8.957 112.152 ;
     RECT  8.957 109.44 9.317 112.152 ;
     RECT  8.597 113.28 9.461 113.304 ;
     RECT  9.317 110.208 9.677 112.152 ;
     RECT  9.677 110.208 9.713 111.48 ;
     RECT  9.713 110.496 9.821 110.52 ;
     RECT  8.957 103.248 9.893 108.36 ;
     RECT  8.104 80.784 10.577 81.816 ;
     RECT  8.104 33.6 10.885 33.624 ;
     RECT  10.577 80.784 10.937 81.528 ;
     RECT  10.885 33.552 13.208 33.624 ;
     RECT  8.104 34.608 13.208 34.632 ;
     RECT  8.104 71.616 13.208 71.64 ;
     RECT  10.937 80.784 13.208 81.096 ;
     RECT  8.104 89.712 13.208 89.736 ;
     RECT  8.104 95.376 13.208 95.4 ;
     RECT  8.104 100.512 13.208 100.536 ;
     RECT  9.893 103.248 13.208 107.4 ;
     RECT  13.208 2.148 13.312 213.852 ;
     RECT  13.312 2.418 13.504 213.582 ;
     RECT  13.504 95.376 15.617 95.4 ;
     RECT  13.504 33.552 18.608 33.624 ;
     RECT  13.504 34.608 18.608 34.632 ;
     RECT  13.504 71.616 18.608 71.64 ;
     RECT  13.504 80.784 18.608 81.096 ;
     RECT  13.504 89.712 18.608 89.736 ;
     RECT  16.693 95.664 18.608 95.688 ;
     RECT  13.504 100.512 18.608 100.536 ;
     RECT  13.504 103.248 18.608 107.4 ;
     RECT  18.608 2.148 18.712 213.852 ;
     RECT  18.712 2.418 18.904 213.582 ;
     RECT  18.904 33.552 24.008 33.624 ;
     RECT  18.904 34.608 24.008 34.632 ;
     RECT  18.904 71.616 24.008 71.64 ;
     RECT  18.904 80.784 24.008 81.096 ;
     RECT  18.904 89.712 24.008 89.736 ;
     RECT  18.904 95.52 24.008 95.544 ;
     RECT  18.904 100.512 24.008 100.536 ;
     RECT  18.904 103.248 24.008 107.4 ;
     RECT  24.008 2.148 24.112 213.852 ;
     RECT  24.112 2.418 24.304 213.582 ;
     RECT  24.304 100.512 27.425 100.536 ;
     RECT  27.701 100.32 27.785 100.344 ;
     RECT  27.733 32.208 29.408 32.232 ;
     RECT  24.304 33.552 29.408 33.624 ;
     RECT  24.304 34.608 29.408 34.632 ;
     RECT  24.304 71.616 29.408 71.64 ;
     RECT  24.304 80.784 29.408 81.096 ;
     RECT  24.304 89.712 29.408 89.736 ;
     RECT  24.304 95.52 29.408 95.544 ;
     RECT  24.304 103.248 29.408 107.4 ;
     RECT  29.408 2.148 29.512 213.852 ;
     RECT  29.512 2.418 29.704 213.582 ;
     RECT  29.704 32.208 34.808 32.232 ;
     RECT  29.704 33.552 34.808 33.624 ;
     RECT  29.704 34.608 34.808 34.632 ;
     RECT  29.704 71.616 34.808 71.64 ;
     RECT  29.704 80.784 34.808 81.096 ;
     RECT  29.704 89.712 34.808 89.736 ;
     RECT  29.704 95.52 34.808 95.544 ;
     RECT  29.704 103.248 34.808 107.4 ;
     RECT  34.808 2.148 34.912 213.852 ;
     RECT  34.912 2.418 35.104 213.582 ;
     RECT  35.104 80.64 35.219 81.096 ;
     RECT  35.219 80.784 35.453 81.096 ;
     RECT  35.453 81.072 35.525 81.096 ;
     RECT  35.104 32.208 40.208 32.232 ;
     RECT  35.104 33.552 40.208 33.624 ;
     RECT  35.104 34.608 40.208 34.632 ;
     RECT  35.104 66.192 40.208 66.216 ;
     RECT  35.104 71.616 40.208 71.64 ;
     RECT  35.104 89.712 40.208 89.736 ;
     RECT  35.104 95.52 40.208 95.544 ;
     RECT  35.104 103.248 40.208 107.4 ;
     RECT  40.208 2.148 40.312 213.852 ;
     RECT  40.312 2.418 40.504 213.582 ;
     RECT  40.504 103.248 41.753 107.4 ;
     RECT  41.893 103.2 42.179 103.224 ;
     RECT  41.753 104.256 44.161 107.4 ;
     RECT  40.504 32.208 45.608 32.232 ;
     RECT  40.504 33.552 45.608 33.624 ;
     RECT  40.504 34.608 45.608 34.632 ;
     RECT  40.504 66.192 45.608 66.216 ;
     RECT  40.504 71.616 45.608 71.64 ;
     RECT  40.504 89.712 45.608 89.736 ;
     RECT  40.504 95.52 45.608 95.544 ;
     RECT  42.133 101.616 45.608 101.64 ;
     RECT  44.161 104.256 45.608 107.544 ;
     RECT  45.608 2.148 45.712 213.852 ;
     RECT  45.712 2.418 45.904 213.582 ;
     RECT  45.904 66.192 50.173 66.216 ;
     RECT  45.904 32.208 51.008 32.232 ;
     RECT  45.904 33.552 51.008 33.624 ;
     RECT  45.904 34.608 51.008 34.632 ;
     RECT  50.173 66.192 51.008 66.264 ;
     RECT  45.904 71.616 51.008 71.64 ;
     RECT  45.904 89.712 51.008 89.736 ;
     RECT  45.904 95.52 51.008 95.544 ;
     RECT  45.904 101.616 51.008 101.64 ;
     RECT  45.904 104.256 51.008 107.544 ;
     RECT  51.008 2.148 51.112 213.852 ;
     RECT  51.112 2.418 51.304 213.582 ;
     RECT  51.304 66.144 51.401 66.264 ;
     RECT  51.304 32.208 56.408 32.232 ;
     RECT  51.304 33.552 56.408 33.624 ;
     RECT  51.304 34.608 56.408 34.632 ;
     RECT  55.573 57.84 56.408 57.864 ;
     RECT  51.401 66.144 56.408 66.168 ;
     RECT  51.304 71.616 56.408 71.64 ;
     RECT  51.304 89.712 56.408 89.736 ;
     RECT  51.304 95.52 56.408 95.544 ;
     RECT  51.304 101.616 56.408 101.64 ;
     RECT  51.304 104.256 56.408 107.544 ;
     RECT  56.408 2.148 56.512 213.852 ;
     RECT  56.512 2.418 56.704 213.582 ;
     RECT  56.704 71.616 57.697 71.64 ;
     RECT  57.697 71.28 57.781 71.64 ;
     RECT  56.704 66.144 57.875 66.168 ;
     RECT  57.781 71.616 58.025 71.64 ;
     RECT  56.704 32.208 61.808 32.232 ;
     RECT  56.704 33.552 61.808 33.624 ;
     RECT  56.704 34.608 61.808 34.632 ;
     RECT  56.704 57.84 61.808 57.864 ;
     RECT  57.829 59.712 61.808 59.736 ;
     RECT  56.704 89.712 61.808 89.736 ;
     RECT  56.704 95.52 61.808 95.544 ;
     RECT  56.704 101.616 61.808 101.64 ;
     RECT  56.704 104.256 61.808 107.544 ;
     RECT  61.808 2.148 61.912 213.852 ;
     RECT  61.912 2.418 62.104 213.582 ;
     RECT  62.104 89.712 62.741 89.832 ;
     RECT  64.105 109.728 65.653 109.752 ;
     RECT  62.741 89.808 65.833 89.832 ;
     RECT  62.104 57.84 66.049 57.864 ;
     RECT  65.833 89.712 66.197 89.832 ;
     RECT  62.104 34.608 66.697 34.632 ;
     RECT  62.104 32.208 67.208 32.232 ;
     RECT  62.104 33.552 67.208 33.624 ;
     RECT  66.697 34.608 67.208 34.728 ;
     RECT  66.049 57.84 67.208 57.96 ;
     RECT  62.104 59.712 67.208 59.736 ;
     RECT  66.197 89.712 67.208 89.736 ;
     RECT  62.104 95.52 67.208 95.544 ;
     RECT  62.104 101.616 67.208 101.64 ;
     RECT  62.104 104.256 67.208 107.544 ;
     RECT  65.653 109.488 67.208 109.752 ;
     RECT  67.208 2.148 67.312 213.852 ;
     RECT  67.312 2.418 67.504 213.582 ;
     RECT  67.504 34.704 69.469 34.728 ;
     RECT  69.469 34.656 70.157 34.728 ;
     RECT  67.504 32.208 72.608 32.232 ;
     RECT  67.504 33.552 72.608 33.624 ;
     RECT  70.157 34.656 72.608 34.68 ;
     RECT  67.504 57.84 72.608 57.96 ;
     RECT  67.504 59.712 72.608 59.736 ;
     RECT  67.504 89.568 72.608 89.592 ;
     RECT  67.504 95.52 72.608 95.544 ;
     RECT  67.504 101.616 72.608 101.64 ;
     RECT  67.504 104.256 72.608 107.544 ;
     RECT  67.504 109.488 72.608 109.752 ;
     RECT  72.608 2.148 72.712 213.852 ;
     RECT  72.712 2.418 72.904 213.582 ;
     RECT  77.029 91.2 77.173 91.224 ;
     RECT  72.904 32.208 78.008 32.232 ;
     RECT  72.904 33.552 78.008 33.624 ;
     RECT  72.904 34.656 78.008 34.68 ;
     RECT  72.904 57.84 78.008 57.96 ;
     RECT  72.904 59.712 78.008 59.736 ;
     RECT  77.029 87.744 78.008 87.768 ;
     RECT  72.904 89.568 78.008 89.592 ;
     RECT  77.173 91.2 78.008 91.416 ;
     RECT  72.904 95.52 78.008 95.544 ;
     RECT  72.904 101.616 78.008 101.64 ;
     RECT  72.904 104.256 78.008 107.544 ;
     RECT  72.904 109.488 78.008 109.752 ;
     RECT  78.008 2.148 78.112 213.852 ;
     RECT  78.112 2.418 78.304 213.582 ;
     RECT  78.304 57.552 78.659 57.96 ;
     RECT  78.304 87.264 78.659 87.288 ;
     RECT  79.873 59.28 79.957 59.304 ;
     RECT  78.304 91.392 80.885 91.416 ;
     RECT  81.884 39.12 81.971 39.144 ;
     RECT  78.659 57.552 81.971 57.864 ;
     RECT  82.393 91.488 82.609 91.512 ;
     RECT  78.304 89.568 82.645 89.592 ;
     RECT  79.909 26.64 83.408 26.664 ;
     RECT  78.304 32.208 83.408 32.232 ;
     RECT  78.304 33.552 83.408 33.624 ;
     RECT  78.304 34.656 83.408 34.68 ;
     RECT  81.971 57.552 83.408 57.576 ;
     RECT  82.645 89.568 83.408 89.736 ;
     RECT  82.609 91.344 83.408 91.512 ;
     RECT  78.304 95.52 83.408 95.544 ;
     RECT  78.304 101.616 83.408 101.64 ;
     RECT  78.304 104.256 83.408 107.544 ;
     RECT  78.304 109.728 83.408 109.752 ;
     RECT  83.408 2.148 83.512 213.852 ;
     RECT  83.512 2.418 83.704 213.582 ;
     RECT  83.704 26.64 83.801 26.76 ;
     RECT  83.704 102.096 83.987 102.12 ;
     RECT  83.704 100.848 84.197 100.872 ;
     RECT  83.704 78.336 84.277 78.648 ;
     RECT  83.704 104.832 85.388 107.544 ;
     RECT  85.388 104.496 85.475 107.544 ;
     RECT  83.704 95.52 85.561 95.544 ;
     RECT  85.475 104.832 85.637 107.544 ;
     RECT  83.704 89.712 85.763 89.736 ;
     RECT  85.561 95.184 85.763 95.544 ;
     RECT  85.637 105.408 86.033 107.544 ;
     RECT  85.777 9.312 86.037 9.336 ;
     RECT  85.993 7.2 86.053 7.224 ;
     RECT  86.037 8.544 86.053 9.336 ;
     RECT  86.053 7.2 86.099 9.336 ;
     RECT  85.763 95.424 86.101 95.544 ;
     RECT  84.805 103.248 86.101 103.272 ;
     RECT  86.053 10.32 86.177 10.344 ;
     RECT  86.101 95.424 86.185 95.64 ;
     RECT  86.053 6.192 86.209 6.216 ;
     RECT  86.101 102.624 86.389 103.272 ;
     RECT  85.849 99.024 86.492 99.048 ;
     RECT  86.492 99.024 86.533 99.384 ;
     RECT  86.533 98.592 86.579 99.384 ;
     RECT  86.209 6.192 86.641 6.264 ;
     RECT  83.704 38.688 86.641 38.952 ;
     RECT  84.277 78.336 86.641 78.36 ;
     RECT  86.641 6.096 86.681 6.264 ;
     RECT  86.641 78.192 86.681 78.36 ;
     RECT  86.185 95.424 86.681 95.544 ;
     RECT  86.389 102.576 86.681 103.272 ;
     RECT  86.099 7.824 86.897 8.568 ;
     RECT  86.533 100.656 86.917 100.68 ;
     RECT  86.681 102.576 86.917 102.6 ;
     RECT  86.917 100.656 86.963 102.6 ;
     RECT  86.963 101.28 87.005 102.6 ;
     RECT  86.065 5.088 87.149 5.112 ;
     RECT  86.033 105.456 87.149 107.544 ;
     RECT  86.897 7.872 87.185 8.568 ;
     RECT  87.149 105.456 87.293 106.488 ;
     RECT  87.26 13.008 87.347 13.032 ;
     RECT  86.579 98.592 87.473 98.616 ;
     RECT  86.681 95.424 87.649 95.448 ;
     RECT  83.704 57.552 87.653 57.576 ;
     RECT  87.005 102 87.685 102.6 ;
     RECT  87.649 95.136 87.733 95.448 ;
     RECT  86.681 6.096 88.045 6.12 ;
     RECT  87.685 102 88.045 102.648 ;
     RECT  88.021 63.216 88.069 63.24 ;
     RECT  88.297 14.688 88.309 14.712 ;
     RECT  87.901 15.936 88.309 15.96 ;
     RECT  88.045 102 88.357 103.08 ;
     RECT  88.225 104.256 88.357 104.28 ;
     RECT  87.185 7.872 88.477 8.28 ;
     RECT  88.045 5.808 88.513 6.12 ;
     RECT  88.477 7.632 88.513 8.28 ;
     RECT  88.513 5.808 88.655 8.28 ;
     RECT  88.655 5.808 88.693 9 ;
     RECT  88.357 102 88.693 104.856 ;
     RECT  88.693 5.76 88.729 9 ;
     RECT  88.693 4.224 88.808 4.248 ;
     RECT  88.729 5.568 88.808 9 ;
     RECT  88.045 10.128 88.808 10.152 ;
     RECT  87.301 11.952 88.808 11.976 ;
     RECT  88.309 14.688 88.808 15.96 ;
     RECT  88.045 18.768 88.808 18.792 ;
     RECT  83.801 26.736 88.808 26.76 ;
     RECT  88.297 28.416 88.808 28.44 ;
     RECT  88.657 29.76 88.808 29.784 ;
     RECT  83.704 32.208 88.808 32.232 ;
     RECT  83.704 33.552 88.808 33.624 ;
     RECT  83.704 34.656 88.808 34.68 ;
     RECT  86.641 38.688 88.808 39.048 ;
     RECT  88.045 58.128 88.808 58.152 ;
     RECT  88.069 62.976 88.808 63.24 ;
     RECT  86.681 78.192 88.808 78.216 ;
     RECT  83.704 91.2 88.808 91.224 ;
     RECT  87.733 95.424 88.808 95.448 ;
     RECT  87.721 98.016 88.808 98.04 ;
     RECT  88.693 101.088 88.808 104.856 ;
     RECT  87.293 106.416 88.808 106.488 ;
     RECT  87.149 107.52 88.808 107.544 ;
     RECT  83.704 109.728 88.808 109.752 ;
     RECT  88.808 2.148 88.912 213.852 ;
     RECT  88.912 2.418 89.104 213.582 ;
     RECT  89.104 101.088 89.201 101.112 ;
     RECT  89.104 4.128 89.219 12.264 ;
     RECT  89.104 18 89.219 22.344 ;
     RECT  89.219 4.128 89.237 10.824 ;
     RECT  89.104 13.248 89.267 14.328 ;
     RECT  89.104 95.424 89.267 95.448 ;
     RECT  89.104 32.208 89.273 33.624 ;
     RECT  89.219 18 89.315 20.04 ;
     RECT  89.104 78.048 89.315 78.216 ;
     RECT  89.273 32.208 89.507 32.52 ;
     RECT  89.315 19.344 89.597 20.04 ;
     RECT  89.267 14.304 89.692 14.328 ;
     RECT  89.267 13.248 89.891 13.272 ;
     RECT  89.219 21.648 90.029 22.344 ;
     RECT  90.029 21.696 90.035 22.344 ;
     RECT  89.104 23.952 90.035 23.976 ;
     RECT  89.597 19.344 90.101 19.368 ;
     RECT  89.507 32.208 90.173 32.232 ;
     RECT  89.104 104.016 90.173 104.04 ;
     RECT  89.104 25.536 90.277 31.032 ;
     RECT  90.133 16.368 90.353 16.392 ;
     RECT  89.273 33.552 90.353 33.624 ;
     RECT  90.277 25.536 90.389 31.464 ;
     RECT  90.353 33.552 90.425 33.576 ;
     RECT  89.315 18 90.497 18.024 ;
     RECT  89.237 4.128 90.677 5.064 ;
     RECT  90.677 4.464 90.745 5.064 ;
     RECT  89.237 6.096 90.745 10.824 ;
     RECT  90.389 25.536 90.749 31.368 ;
     RECT  89.219 11.808 90.889 12.264 ;
     RECT  89.104 57.552 90.899 57.624 ;
     RECT  90.745 4.464 91.069 10.824 ;
     RECT  90.889 11.808 91.069 12.6 ;
     RECT  90.457 23.76 91.105 23.928 ;
     RECT  90.035 21.696 91.141 22.2 ;
     RECT  89.104 34.656 91.141 34.68 ;
     RECT  90.853 35.856 91.141 35.88 ;
     RECT  91.105 14.832 91.177 14.856 ;
     RECT  91.141 34.656 91.187 35.88 ;
     RECT  91.177 14.832 91.285 14.952 ;
     RECT  91.141 21.504 91.321 22.2 ;
     RECT  91.105 23.76 91.321 24.12 ;
     RECT  90.637 20.016 91.429 20.04 ;
     RECT  91.321 21.504 91.429 24.12 ;
     RECT  91.069 4.464 91.609 12.6 ;
     RECT  91.285 14.832 91.609 15.816 ;
     RECT  91.429 21.504 91.613 24.168 ;
     RECT  91.429 19.344 91.681 20.04 ;
     RECT  91.187 34.656 91.721 35.448 ;
     RECT  91.613 21.504 91.793 24.12 ;
     RECT  91.681 19.344 91.825 20.232 ;
     RECT  91.793 21.504 91.901 23.016 ;
     RECT  90.749 25.536 91.901 31.032 ;
     RECT  91.901 21.504 91.973 22.92 ;
     RECT  89.104 38.688 92.051 38.952 ;
     RECT  91.901 25.536 92.293 30.792 ;
     RECT  91.609 4.464 92.329 15.816 ;
     RECT  91.645 2.736 92.365 2.76 ;
     RECT  92.329 4.464 92.545 16.584 ;
     RECT  92.365 2.256 92.617 2.76 ;
     RECT  92.545 3.84 92.617 16.584 ;
     RECT  91.825 18.768 92.657 20.232 ;
     RECT  91.825 32.208 92.725 32.232 ;
     RECT  91.973 21.504 92.729 22.824 ;
     RECT  92.293 25.44 92.761 30.792 ;
     RECT  92.617 0.096 92.869 0.12 ;
     RECT  92.869 0.048 92.965 0.12 ;
     RECT  92.869 1.104 92.965 1.128 ;
     RECT  92.965 0.048 93.013 1.128 ;
     RECT  91.793 24.096 93.049 24.12 ;
     RECT  92.761 25.248 93.049 30.792 ;
     RECT  92.617 2.256 93.085 16.584 ;
     RECT  92.917 17.616 93.085 17.64 ;
     RECT  93.013 0.048 93.293 1.176 ;
     RECT  93.085 2.256 93.293 17.64 ;
     RECT  92.725 31.968 93.308 32.232 ;
     RECT  93.308 31.968 93.349 33.096 ;
     RECT  93.293 0.048 93.377 17.64 ;
     RECT  92.729 22.416 93.409 22.824 ;
     RECT  92.657 19.968 93.553 20.232 ;
     RECT  93.049 24.096 93.553 30.792 ;
     RECT  93.349 31.92 93.553 33.096 ;
     RECT  90.899 57.552 93.589 57.576 ;
     RECT  93.409 22.416 93.625 22.92 ;
     RECT  93.553 24.096 93.625 33.096 ;
     RECT  93.377 2.148 93.949 17.64 ;
     RECT  92.657 18.768 94.057 18.792 ;
     RECT  93.553 19.968 94.057 21.096 ;
     RECT  93.949 2.148 94.208 17.736 ;
     RECT  94.057 18.768 94.208 21.096 ;
     RECT  93.625 22.416 94.208 33.096 ;
     RECT  91.721 35.424 94.208 35.448 ;
     RECT  92.051 38.928 94.208 38.952 ;
     RECT  93.589 57.552 94.208 57.912 ;
     RECT  89.104 63.072 94.208 63.24 ;
     RECT  90.817 77.952 94.208 77.976 ;
     RECT  89.104 109.728 94.208 109.752 ;
     RECT  94.208 2.148 94.312 213.852 ;
     RECT  93.377 0.048 94.357 1.176 ;
     RECT  94.312 2.148 94.357 213.582 ;
     RECT  94.357 0.048 94.504 213.582 ;
     RECT  94.504 0.048 94.601 22.824 ;
     RECT  94.601 0.048 94.684 22.344 ;
     RECT  94.504 23.808 94.817 30.696 ;
     RECT  94.817 23.808 94.889 30.456 ;
     RECT  94.684 1.728 94.961 22.344 ;
     RECT  94.961 19.92 95.219 22.344 ;
     RECT  94.889 23.808 95.219 30.408 ;
     RECT  95.219 19.92 95.285 21.72 ;
     RECT  94.961 1.728 95.609 18.936 ;
     RECT  95.285 19.92 95.753 20.616 ;
     RECT  94.684 0.048 95.797 0.408 ;
     RECT  95.609 1.728 95.797 17.4 ;
     RECT  95.285 21.696 96.217 21.72 ;
     RECT  95.797 0.048 96.323 17.4 ;
     RECT  96.217 21.696 96.505 22.248 ;
     RECT  94.504 57.552 96.505 58.008 ;
     RECT  94.504 77.952 96.517 77.976 ;
     RECT  96.505 57.552 96.589 58.152 ;
     RECT  96.323 1.728 96.649 17.4 ;
     RECT  95.753 20.016 96.649 20.616 ;
     RECT  96.505 21.696 96.649 22.776 ;
     RECT  96.517 77.808 96.659 77.976 ;
     RECT  96.649 1.728 96.685 17.88 ;
     RECT  95.929 18.96 96.685 18.984 ;
     RECT  96.649 20.016 96.721 22.776 ;
     RECT  96.589 57.552 96.869 58.008 ;
     RECT  95.219 24.48 96.901 30.408 ;
     RECT  96.685 1.728 97.045 18.984 ;
     RECT  96.721 20.016 97.045 22.824 ;
     RECT  96.901 23.952 97.045 30.408 ;
     RECT  97.045 23.952 97.441 30.984 ;
     RECT  96.323 0.048 97.667 0.408 ;
     RECT  96.869 57.552 97.801 57.576 ;
     RECT  97.801 57.024 97.885 57.576 ;
     RECT  97.045 1.728 97.949 22.824 ;
     RECT  97.667 0.048 98.129 0.264 ;
     RECT  98.129 0.144 98.173 0.264 ;
     RECT  97.949 1.728 98.201 21.72 ;
     RECT  98.201 1.728 98.273 4.296 ;
     RECT  98.173 0.192 98.435 0.264 ;
     RECT  97.441 23.856 98.489 30.984 ;
     RECT  98.489 23.856 98.593 28.344 ;
     RECT  96.659 77.808 98.593 77.832 ;
     RECT  98.593 77.808 98.633 77.928 ;
     RECT  98.201 5.472 98.989 21.72 ;
     RECT  98.593 23.04 98.989 28.344 ;
     RECT  98.435 0.192 99.157 0.216 ;
     RECT  98.989 5.472 99.277 28.344 ;
     RECT  99.157 0.144 99.397 0.216 ;
     RECT  94.504 35.424 99.493 35.448 ;
     RECT  99.397 36.432 99.493 36.456 ;
     RECT  98.273 1.728 99.608 4.104 ;
     RECT  99.277 5.136 99.608 28.344 ;
     RECT  98.489 29.376 99.608 30.984 ;
     RECT  99.493 34.656 99.608 36.456 ;
     RECT  97.885 57.552 99.608 57.576 ;
     RECT  94.504 63.216 99.608 63.24 ;
     RECT  98.633 77.904 99.608 77.928 ;
     RECT  94.504 109.728 99.608 109.752 ;
     RECT  99.397 0.144 99.683 0.36 ;
     RECT  99.608 1.728 99.712 213.852 ;
     RECT  99.712 1.728 99.904 213.582 ;
     RECT  99.683 0.144 99.917 0.312 ;
     RECT  99.917 0.096 100.001 0.312 ;
     RECT  100.001 0.144 100.019 0.312 ;
     RECT  99.904 1.728 100.019 30.936 ;
     RECT  99.904 34.224 100.325 36.072 ;
     RECT  100.019 0.144 100.403 0.264 ;
     RECT  100.019 26.736 100.499 30.936 ;
     RECT  100.403 0.24 100.691 0.264 ;
     RECT  99.904 77.904 100.691 77.928 ;
     RECT  99.904 82.8 100.691 82.824 ;
     RECT  99.904 86.64 100.691 86.664 ;
     RECT  100.325 34.224 100.729 35.928 ;
     RECT  100.499 26.736 100.829 28.44 ;
     RECT  100.499 29.856 100.933 30.936 ;
     RECT  100.829 26.736 101.009 28.296 ;
     RECT  100.933 82.656 101.017 82.68 ;
     RECT  100.729 34.224 101.113 35.112 ;
     RECT  100.019 1.728 101.123 25.704 ;
     RECT  101.123 1.728 101.189 23.736 ;
     RECT  101.113 33.792 101.197 35.112 ;
     RECT  100.933 29.856 101.461 31.128 ;
     RECT  101.197 34.032 101.747 35.112 ;
     RECT  101.123 24.72 101.797 25.704 ;
     RECT  101.009 26.736 101.797 28.152 ;
     RECT  101.747 34.368 101.939 35.112 ;
     RECT  101.905 87.168 101.989 87.192 ;
     RECT  101.797 0.144 102.083 0.168 ;
     RECT  101.797 24.72 102.085 28.152 ;
     RECT  101.189 1.728 102.188 22.776 ;
     RECT  102.085 23.952 102.229 28.248 ;
     RECT  102.188 1.104 102.275 22.776 ;
     RECT  102.275 1.728 102.301 22.776 ;
     RECT  102.229 23.808 102.301 28.248 ;
     RECT  99.904 63.216 102.589 63.24 ;
     RECT  102.589 63.072 102.629 63.24 ;
     RECT  102.301 1.728 103.139 28.248 ;
     RECT  103.139 2.256 103.177 28.248 ;
     RECT  103.177 2.256 103.357 22.824 ;
     RECT  101.461 29.376 103.385 31.128 ;
     RECT  103.177 24 103.417 28.248 ;
     RECT  102.997 0.096 103.525 0.12 ;
     RECT  103.285 1.152 103.525 1.176 ;
     RECT  103.525 0.096 103.637 1.176 ;
     RECT  103.417 24 103.709 28.776 ;
     RECT  103.637 0.096 103.817 1.128 ;
     RECT  103.817 0.144 104.243 1.128 ;
     RECT  103.709 24 104.341 27.768 ;
     RECT  103.357 2.88 104.461 22.824 ;
     RECT  104.341 23.808 104.461 27.768 ;
     RECT  104.243 0.288 104.483 1.128 ;
     RECT  104.461 2.88 104.533 27.768 ;
     RECT  104.533 2.304 104.629 27.768 ;
     RECT  104.629 1.728 104.857 27.768 ;
     RECT  103.709 28.752 104.857 28.776 ;
     RECT  104.857 1.728 105.001 28.776 ;
     RECT  105.001 1.728 105.008 28.824 ;
     RECT  103.385 30 105.008 31.128 ;
     RECT  101.939 34.368 105.008 34.392 ;
     RECT  102.629 63.072 105.008 63.096 ;
     RECT  99.904 109.728 105.008 109.752 ;
     RECT  105.001 158.544 105.008 158.568 ;
     RECT  101.941 213.36 105.008 213.384 ;
     RECT  105.008 1.728 105.112 213.852 ;
     RECT  104.483 0.288 105.205 0.312 ;
     RECT  105.112 1.728 105.304 213.582 ;
     RECT  105.205 0.096 105.365 0.312 ;
     RECT  105.365 0.144 105.493 0.312 ;
     RECT  105.304 1.728 105.493 28.92 ;
     RECT  105.493 0.144 105.635 28.92 ;
     RECT  105.304 40.272 105.635 40.776 ;
     RECT  105.304 63.072 105.635 63.096 ;
     RECT  105.635 1.728 105.683 28.92 ;
     RECT  105.683 24.48 105.905 28.92 ;
     RECT  105.635 40.272 105.977 40.488 ;
     RECT  105.905 24.672 106.049 28.92 ;
     RECT  106.049 24.672 106.373 28.776 ;
     RECT  105.304 30.336 106.585 31.032 ;
     RECT  106.585 30.096 106.625 31.032 ;
     RECT  106.625 30.096 106.657 30.84 ;
     RECT  106.373 26.112 107.029 28.776 ;
     RECT  106.657 30.048 107.029 30.84 ;
     RECT  105.683 1.728 107.077 23.4 ;
     RECT  107.077 1.68 107.267 23.4 ;
     RECT  107.267 1.728 107.305 23.4 ;
     RECT  106.373 24.672 107.305 25.032 ;
     RECT  107.305 1.728 107.449 25.032 ;
     RECT  107.029 26.112 107.449 30.84 ;
     RECT  105.635 0.144 107.521 0.168 ;
     RECT  107.449 1.728 107.561 30.84 ;
     RECT  107.521 0.144 107.651 0.552 ;
     RECT  105.304 213.36 107.701 213.384 ;
     RECT  107.561 1.728 107.777 29.208 ;
     RECT  105.304 109.728 107.843 109.752 ;
     RECT  107.701 213.36 107.852 213.72 ;
     RECT  105.304 158.544 107.939 158.568 ;
     RECT  107.852 213.024 108.035 213.72 ;
     RECT  108.044 211.872 108.061 211.896 ;
     RECT  108.035 213.024 108.061 213.384 ;
     RECT  108.061 211.872 108.133 213.384 ;
     RECT  107.651 0.144 108.161 0.264 ;
     RECT  108.133 211.44 108.179 213.384 ;
     RECT  108.179 211.44 108.353 212.04 ;
     RECT  108.353 211.872 108.467 212.04 ;
     RECT  108.467 211.872 108.755 211.896 ;
     RECT  107.777 1.728 108.817 21.72 ;
     RECT  107.777 22.752 108.817 29.208 ;
     RECT  108.817 1.728 108.821 29.208 ;
     RECT  108.179 213.168 108.893 213.384 ;
     RECT  108.821 24.624 108.956 29.208 ;
     RECT  107.561 30.384 108.956 30.84 ;
     RECT  108.956 24.624 109.001 30.84 ;
     RECT  108.893 213.216 109.037 213.384 ;
     RECT  109.001 24.624 109.073 30.696 ;
     RECT  109.037 213.216 109.073 213.336 ;
     RECT  109.073 24.672 109.181 30.696 ;
     RECT  109.073 213.312 109.325 213.336 ;
     RECT  108.161 0.096 109.865 0.264 ;
     RECT  108.821 1.728 110.005 23.592 ;
     RECT  110.005 1.392 110.293 23.592 ;
     RECT  109.181 24.672 110.293 30.6 ;
     RECT  110.293 1.392 110.408 30.6 ;
     RECT  105.304 34.368 110.408 34.392 ;
     RECT  105.977 40.272 110.408 40.296 ;
     RECT  110.408 1.392 110.512 213.852 ;
     RECT  109.865 0.144 110.677 0.264 ;
     RECT  110.512 1.392 110.677 213.582 ;
     RECT  110.677 0.144 110.704 213.582 ;
     RECT  110.704 28.944 110.765 30.408 ;
     RECT  110.704 0.144 110.837 27.912 ;
     RECT  110.837 0.144 111.221 0.264 ;
     RECT  110.837 1.392 111.377 27.912 ;
     RECT  111.221 0.096 111.701 0.264 ;
     RECT  111.377 1.392 112.412 19.272 ;
     RECT  111.377 20.304 112.412 27.912 ;
     RECT  112.412 1.392 112.417 27.912 ;
     RECT  110.765 28.992 112.417 30.408 ;
     RECT  110.704 34.368 112.499 34.392 ;
     RECT  112.417 1.392 112.732 30.408 ;
     RECT  112.732 1.392 112.885 4.008 ;
     RECT  111.701 0.24 112.949 0.264 ;
     RECT  112.885 1.248 112.949 4.008 ;
     RECT  112.949 0.24 113.221 4.008 ;
     RECT  113.221 0.144 113.411 4.008 ;
     RECT  112.732 5.136 113.929 30.408 ;
     RECT  113.929 5.088 113.933 30.408 ;
     RECT  113.411 0.24 114.332 4.008 ;
     RECT  113.933 5.088 114.332 23.928 ;
     RECT  110.704 40.272 114.577 40.296 ;
     RECT  113.933 25.008 114.611 30.408 ;
     RECT  114.577 40.128 114.617 40.296 ;
     RECT  114.611 25.008 114.652 29.4 ;
     RECT  114.332 0.24 114.677 23.928 ;
     RECT  114.677 0.096 114.761 23.928 ;
     RECT  114.761 0.192 115.153 23.928 ;
     RECT  114.652 25.008 115.153 29.16 ;
     RECT  115.153 0.192 115.808 29.16 ;
     RECT  114.611 30.384 115.808 30.408 ;
     RECT  114.617 40.128 115.808 40.152 ;
     RECT  115.808 0.192 115.912 213.852 ;
     RECT  115.912 0.192 116.104 213.582 ;
     RECT  116.104 0.192 116.341 25.32 ;
     RECT  116.104 28.416 116.345 28.44 ;
     RECT  116.341 0.144 116.821 25.32 ;
     RECT  116.104 26.64 117.385 26.76 ;
     RECT  116.821 0.096 117.425 25.32 ;
     RECT  117.385 26.64 117.637 27.384 ;
     RECT  116.104 40.128 117.683 40.152 ;
     RECT  117.425 0.096 117.965 19.416 ;
     RECT  117.425 20.688 118.117 25.32 ;
     RECT  117.637 26.496 118.117 27.384 ;
     RECT  118.117 20.688 118.145 27.384 ;
     RECT  118.145 20.736 118.541 27.384 ;
     RECT  118.541 20.736 118.757 26.52 ;
     RECT  118.757 20.784 118.937 26.52 ;
     RECT  118.937 22.128 119.117 26.52 ;
     RECT  119.041 28.224 119.221 28.248 ;
     RECT  117.965 0.096 119.297 19.368 ;
     RECT  119.117 22.416 119.509 26.52 ;
     RECT  119.221 28.224 119.509 28.296 ;
     RECT  119.509 27.888 119.693 28.296 ;
     RECT  119.693 28.224 119.729 28.296 ;
     RECT  119.509 22.416 119.765 26.616 ;
     RECT  119.765 25.008 119.801 26.616 ;
     RECT  119.297 0.192 119.869 19.368 ;
     RECT  118.937 20.784 119.869 21.144 ;
     RECT  119.801 25.296 119.873 26.616 ;
     RECT  119.765 22.416 120.053 23.784 ;
     RECT  119.873 25.536 120.193 26.616 ;
     RECT  119.869 0.192 120.277 21.144 ;
     RECT  120.053 22.416 120.277 22.488 ;
     RECT  119.729 28.272 120.553 28.296 ;
     RECT  120.277 0.096 120.613 21.144 ;
     RECT  120.277 22.176 120.613 22.488 ;
     RECT  120.053 23.76 120.805 23.784 ;
     RECT  120.193 25.536 121.129 26.808 ;
     RECT  120.613 0.096 121.208 22.488 ;
     RECT  120.805 23.76 121.208 24.12 ;
     RECT  121.129 25.2 121.208 26.808 ;
     RECT  120.553 28.272 121.208 29.256 ;
     RECT  116.104 30.384 121.208 30.408 ;
     RECT  121.208 0.096 121.312 213.852 ;
     RECT  121.312 0.096 121.504 213.582 ;
     RECT  121.504 0.096 121.637 21.48 ;
     RECT  121.504 25.2 121.817 26.616 ;
     RECT  121.637 0.096 121.853 21.192 ;
     RECT  121.504 22.704 121.948 22.824 ;
     RECT  121.853 0.096 122.141 18.792 ;
     RECT  121.817 25.2 122.285 25.704 ;
     RECT  122.285 25.2 122.321 25.608 ;
     RECT  121.504 24 122.533 24.12 ;
     RECT  121.853 19.872 122.573 19.896 ;
     RECT  122.141 0.096 122.675 18.552 ;
     RECT  122.675 0.096 122.689 4.536 ;
     RECT  121.853 21.168 122.753 21.192 ;
     RECT  121.948 22.8 122.753 22.824 ;
     RECT  121.504 29.232 122.861 29.256 ;
     RECT  122.533 23.952 123.109 24.12 ;
     RECT  122.321 25.2 123.109 25.512 ;
     RECT  123.109 23.328 123.155 25.512 ;
     RECT  122.675 5.808 123.221 18.552 ;
     RECT  123.155 23.328 123.221 23.352 ;
     RECT  123.155 24.528 123.293 25.512 ;
     RECT  123.221 16.032 123.505 18.552 ;
     RECT  123.221 5.808 123.649 14.904 ;
     RECT  123.505 16.032 123.653 18.744 ;
     RECT  123.653 18.192 123.685 18.744 ;
     RECT  123.293 25.488 123.689 25.512 ;
     RECT  122.689 0.096 123.761 4.392 ;
     RECT  123.361 21.36 123.797 21.48 ;
     RECT  123.685 18.192 123.829 18.792 ;
     RECT  123.761 0.576 123.865 4.392 ;
     RECT  123.649 5.568 123.941 14.904 ;
     RECT  123.941 5.568 124.013 14.856 ;
     RECT  123.829 18.192 124.019 19.416 ;
     RECT  124.019 18.192 124.06 18.216 ;
     RECT  123.653 16.032 124.121 16.92 ;
     RECT  123.865 0.576 124.225 4.584 ;
     RECT  124.013 5.568 124.225 14.568 ;
     RECT  123.797 21.456 124.301 21.48 ;
     RECT  124.225 0.576 124.307 14.568 ;
     RECT  124.307 4.368 124.337 14.568 ;
     RECT  124.121 16.032 124.337 16.584 ;
     RECT  124.337 14.16 124.373 14.568 ;
     RECT  124.337 16.56 124.547 16.584 ;
     RECT  124.307 0.576 124.595 3.24 ;
     RECT  124.337 4.368 124.913 12.792 ;
     RECT  124.373 14.16 124.913 14.184 ;
     RECT  124.595 0.576 124.931 3.144 ;
     RECT  124.931 0.576 124.979 3.096 ;
     RECT  124.913 4.368 124.985 11.112 ;
     RECT  124.913 12.576 125.021 12.792 ;
     RECT  124.979 0.576 125.027 0.6 ;
     RECT  124.985 5.136 125.027 11.064 ;
     RECT  124.979 1.776 125.093 3.096 ;
     RECT  125.021 12.576 125.129 12.6 ;
     RECT  125.027 5.568 125.165 11.064 ;
     RECT  125.165 8.88 125.219 11.064 ;
     RECT  125.093 1.776 125.237 2.424 ;
     RECT  125.165 5.568 125.237 7.8 ;
     RECT  125.219 8.976 125.26 11.064 ;
     RECT  125.26 8.976 125.309 9.48 ;
     RECT  125.237 6.288 125.453 7.8 ;
     RECT  125.309 9.024 125.453 9.48 ;
     RECT  125.26 10.656 125.489 11.064 ;
     RECT  125.237 2.352 125.525 2.424 ;
     RECT  125.453 6.48 125.525 7.8 ;
     RECT  125.525 6.48 125.561 6.504 ;
     RECT  125.489 10.656 125.561 10.728 ;
     RECT  125.525 2.4 126.608 2.424 ;
     RECT  125.453 9.024 126.608 9.048 ;
     RECT  125.561 10.656 126.608 10.68 ;
     RECT  126.608 2.148 126.712 213.852 ;
     RECT  126.712 2.418 126.904 213.582 ;
     RECT  132.008 2.148 132.112 213.852 ;
     RECT  132.112 2.418 132.304 213.582 ;
     RECT  137.408 2.148 137.512 213.852 ;
     RECT  137.512 2.418 137.704 213.582 ;
     RECT  142.808 2.148 142.912 213.852 ;
     RECT  142.912 2.418 143.104 213.582 ;
     RECT  148.208 2.148 148.312 213.852 ;
     RECT  148.312 2.418 148.504 213.582 ;
     RECT  153.608 2.148 153.712 213.852 ;
     RECT  153.712 2.418 153.904 213.582 ;
     RECT  159.008 2.148 159.112 213.852 ;
     RECT  159.112 2.418 159.304 213.582 ;
     RECT  164.408 2.148 164.512 213.852 ;
     RECT  164.512 2.418 164.704 213.582 ;
     RECT  169.808 2.148 169.912 213.852 ;
     RECT  169.912 2.418 170.104 213.582 ;
     RECT  175.208 2.148 175.312 213.852 ;
     RECT  175.312 2.418 175.504 213.582 ;
     RECT  180.608 2.148 180.712 213.852 ;
     RECT  180.712 2.418 180.904 213.582 ;
     RECT  186.008 2.148 186.112 213.852 ;
     RECT  186.112 2.418 186.304 213.582 ;
     RECT  191.408 2.148 191.512 213.852 ;
     RECT  191.512 2.418 191.704 213.582 ;
     RECT  196.808 2.148 196.912 213.852 ;
     RECT  196.912 2.418 197.104 213.582 ;
     RECT  202.208 2.148 202.312 213.852 ;
     RECT  202.312 2.418 202.504 213.582 ;
     RECT  207.608 2.148 207.712 213.852 ;
     RECT  207.712 2.418 207.904 213.582 ;
     RECT  213.008 2.148 213.112 213.852 ;
     RECT  213.112 2.418 213.304 213.582 ;
    LAYER M5 ;
     RECT  92.64 0.016 123.384 1.141 ;
     RECT  92.64 1.141 123.48 1.429 ;
     RECT  124.992 0.565 125.016 1.477 ;
     RECT  92.64 1.429 123.864 1.909 ;
     RECT  124.944 1.477 125.016 1.909 ;
     RECT  2.4 2.137 2.52 2.151 ;
     RECT  7.8 2.137 7.92 2.151 ;
     RECT  13.2 2.137 13.32 2.151 ;
     RECT  18.6 2.137 18.72 2.151 ;
     RECT  24 2.137 24.12 2.151 ;
     RECT  29.4 2.137 29.52 2.151 ;
     RECT  34.8 2.137 34.92 2.151 ;
     RECT  40.2 2.137 40.32 2.151 ;
     RECT  45.6 2.137 45.72 2.151 ;
     RECT  51 2.137 51.12 2.151 ;
     RECT  56.4 2.137 56.52 2.151 ;
     RECT  61.8 2.137 61.92 2.151 ;
     RECT  67.2 2.137 67.32 2.151 ;
     RECT  72.6 2.137 72.72 2.151 ;
     RECT  78 2.137 78.12 2.151 ;
     RECT  83.4 2.137 83.52 2.151 ;
     RECT  88.8 2.137 88.92 2.151 ;
     RECT  126.6 2.137 126.72 2.151 ;
     RECT  132 2.137 132.12 2.151 ;
     RECT  137.4 2.137 137.52 2.151 ;
     RECT  142.8 2.137 142.92 2.151 ;
     RECT  148.2 2.137 148.32 2.151 ;
     RECT  153.6 2.137 153.72 2.151 ;
     RECT  159 2.137 159.12 2.151 ;
     RECT  164.4 2.137 164.52 2.151 ;
     RECT  169.8 2.137 169.92 2.151 ;
     RECT  175.2 2.137 175.32 2.151 ;
     RECT  180.6 2.137 180.72 2.151 ;
     RECT  186 2.137 186.12 2.151 ;
     RECT  191.4 2.137 191.52 2.151 ;
     RECT  196.8 2.137 196.92 2.151 ;
     RECT  202.2 2.137 202.32 2.151 ;
     RECT  207.6 2.137 207.72 2.151 ;
     RECT  213 2.137 213.12 2.151 ;
     RECT  92.64 1.909 125.016 2.915 ;
     RECT  88.8 2.151 89.112 4.501 ;
     RECT  88.8 4.501 90.072 4.549 ;
     RECT  88.8 4.549 90.648 4.691 ;
     RECT  92.832 2.915 125.016 5.171 ;
     RECT  92.832 5.171 124.968 5.461 ;
     RECT  88.8 4.691 90.072 6.229 ;
     RECT  92.784 5.461 124.968 6.229 ;
     RECT  91.92 6.229 124.968 6.851 ;
     RECT  88.8 6.229 90.552 6.899 ;
     RECT  92.976 6.851 124.968 6.947 ;
     RECT  91.92 6.851 91.944 7.283 ;
     RECT  88.8 6.899 89.688 7.475 ;
     RECT  93.312 6.947 124.968 7.475 ;
     RECT  93.312 7.475 124.92 7.619 ;
     RECT  93.312 7.619 122.136 7.763 ;
     RECT  88.8 7.475 89.208 7.909 ;
     RECT  93.312 7.763 121.752 7.957 ;
     RECT  92.448 7.957 121.752 8.003 ;
     RECT  119.328 8.003 121.752 8.099 ;
     RECT  92.448 8.003 117.624 8.485 ;
     RECT  91.776 8.485 117.624 8.531 ;
     RECT  91.776 8.531 108.12 8.627 ;
     RECT  91.776 8.627 96.648 8.771 ;
     RECT  121.056 8.099 121.752 8.773 ;
     RECT  123.168 7.619 124.92 8.773 ;
     RECT  109.296 8.531 117.624 8.819 ;
     RECT  121.056 8.773 124.92 8.869 ;
     RECT  88.704 7.909 89.208 8.965 ;
     RECT  88.704 8.965 90.072 9.011 ;
     RECT  119.328 8.099 119.976 9.109 ;
     RECT  121.056 8.869 125.208 9.109 ;
     RECT  119.328 9.109 125.208 9.155 ;
     RECT  91.776 8.771 92.472 9.349 ;
     RECT  98.256 8.627 108.12 9.637 ;
     RECT  109.296 8.819 117.576 9.637 ;
     RECT  98.256 9.637 117.576 9.731 ;
     RECT  120.48 9.155 125.208 9.731 ;
     RECT  98.256 9.731 107.16 9.779 ;
     RECT  88.8 9.011 90.072 9.875 ;
     RECT  91.728 9.349 92.472 9.973 ;
     RECT  94.032 8.771 96.648 10.069 ;
     RECT  98.256 9.779 102.6 10.069 ;
     RECT  108.384 9.731 117.576 10.165 ;
     RECT  86.064 6.181 86.088 10.355 ;
     RECT  108.384 10.165 117.816 10.357 ;
     RECT  121.104 9.731 125.208 10.547 ;
     RECT  124.464 10.547 125.208 10.595 ;
     RECT  121.104 10.547 123.24 10.643 ;
     RECT  124.464 10.595 125.16 10.691 ;
     RECT  91.728 9.973 92.904 10.739 ;
     RECT  94.032 10.069 102.6 10.741 ;
     RECT  103.632 9.779 107.16 10.741 ;
     RECT  124.464 10.691 124.68 10.787 ;
     RECT  94.032 10.741 107.256 10.789 ;
     RECT  94.032 10.789 107.4 10.837 ;
     RECT  124.464 10.787 124.536 10.883 ;
     RECT  91.728 10.739 92.472 10.981 ;
     RECT  93.456 10.837 107.4 11.269 ;
     RECT  108.384 10.357 118.728 11.269 ;
     RECT  93.456 11.269 118.728 11.365 ;
     RECT  93.456 11.365 119.688 11.605 ;
     RECT  93.456 11.605 120.024 11.701 ;
     RECT  121.104 10.643 122.568 11.701 ;
     RECT  88.8 9.875 89.208 11.797 ;
     RECT  124.512 10.883 124.536 11.941 ;
     RECT  93.456 11.701 122.568 12.371 ;
     RECT  91.68 10.981 92.472 12.611 ;
     RECT  124.512 11.941 124.872 12.755 ;
     RECT  87.312 11.941 87.336 13.043 ;
     RECT  88.8 11.797 89.88 13.283 ;
     RECT  94.2 12.371 122.568 14.243 ;
     RECT  88.8 13.283 89.64 14.339 ;
     RECT  88.8 14.339 89.256 14.677 ;
     RECT  88.32 14.677 89.256 15.443 ;
     RECT  94.2 14.243 121.512 15.925 ;
     RECT  122.544 14.243 122.568 15.925 ;
     RECT  124.512 12.755 124.536 16.595 ;
     RECT  94.2 15.925 122.568 16.933 ;
     RECT  92.448 12.611 92.472 17.605 ;
     RECT  94.2 16.933 122.856 17.891 ;
     RECT  94.2 17.891 122.568 18.515 ;
     RECT  88.8 15.443 89.256 18.709 ;
     RECT  92.448 17.605 92.952 18.803 ;
     RECT  92.448 18.803 92.472 19.093 ;
     RECT  92.352 19.093 92.472 19.333 ;
     RECT  91.44 19.333 92.472 19.427 ;
     RECT  123.984 18.181 124.008 19.427 ;
     RECT  88.8 18.709 89.304 19.811 ;
     RECT  91.44 19.427 92.376 20.003 ;
     RECT  88.8 19.811 89.256 20.051 ;
     RECT  94.2 18.515 98.616 20.627 ;
     RECT  94.2 20.627 96.84 20.917 ;
     RECT  91.44 20.003 92.328 21.637 ;
     RECT  99.6 18.515 122.568 21.683 ;
     RECT  93.6 20.917 96.84 21.971 ;
     RECT  112.464 21.683 122.568 22.211 ;
     RECT  88.8 20.051 89.208 22.309 ;
     RECT  117.504 22.211 122.568 22.739 ;
     RECT  99.6 21.683 111.24 22.835 ;
     RECT  112.464 22.211 116.112 22.835 ;
     RECT  112.464 22.835 114.696 22.883 ;
     RECT  91.392 21.637 92.328 23.077 ;
     RECT  122.544 22.739 122.568 23.317 ;
     RECT  117.504 22.739 121.512 23.363 ;
     RECT  99.6 22.835 103.128 23.411 ;
     RECT  110.304 22.835 111.24 23.411 ;
     RECT  110.304 23.411 110.808 23.603 ;
     RECT  117.648 23.363 121.512 23.795 ;
     RECT  104.352 22.835 109.08 23.843 ;
     RECT  110.304 23.603 110.712 23.987 ;
     RECT  122.544 23.317 123.144 23.987 ;
     RECT  117.648 23.795 119.352 24.083 ;
     RECT  93.6 21.971 96.024 24.419 ;
     RECT  115.8 22.835 116.112 24.469 ;
     RECT  117.648 24.083 118.92 24.469 ;
     RECT  123.12 23.987 123.144 24.563 ;
     RECT  115.8 24.469 118.92 24.659 ;
     RECT  112.464 22.883 113.208 24.707 ;
     RECT  112.464 24.707 113.016 25.091 ;
     RECT  104.736 23.843 109.08 25.139 ;
     RECT  115.8 24.659 117.672 25.139 ;
     RECT  118.848 24.659 118.92 25.139 ;
     RECT  95.856 24.419 96.024 25.333 ;
     RECT  91.344 23.077 92.328 25.525 ;
     RECT  93.6 24.419 94.512 25.525 ;
     RECT  120.816 23.795 121.512 25.571 ;
     RECT  99.6 23.411 103.032 25.573 ;
     RECT  91.344 25.525 94.512 25.667 ;
     RECT  117.648 25.139 117.672 26.149 ;
     RECT  118.896 25.139 118.92 26.149 ;
     RECT  99.6 25.573 103.224 26.243 ;
     RECT  117.648 26.149 118.92 26.243 ;
     RECT  88.8 22.309 90.024 26.291 ;
     RECT  105 25.139 109.08 26.339 ;
     RECT  103.2 26.243 103.224 26.389 ;
     RECT  105 26.339 107.688 26.389 ;
     RECT  91.344 25.667 92.04 26.771 ;
     RECT  93.168 25.667 94.512 26.819 ;
     RECT  99.6 26.243 102.168 26.819 ;
     RECT  103.2 26.389 107.688 26.819 ;
     RECT  109.056 26.339 109.08 27.059 ;
     RECT  114.384 22.883 114.696 27.205 ;
     RECT  115.8 25.139 116.112 27.205 ;
     RECT  117.648 26.243 118.152 27.395 ;
     RECT  110.4 23.987 110.712 27.685 ;
     RECT  112.464 25.091 112.968 27.685 ;
     RECT  99.6 26.819 101.928 27.877 ;
     RECT  105 26.819 107.688 27.971 ;
     RECT  110.4 27.685 112.968 27.971 ;
     RECT  114.384 27.205 116.112 27.971 ;
     RECT  103.2 26.819 103.224 28.163 ;
     RECT  107.04 27.971 107.688 28.451 ;
     RECT  93.6 26.819 94.512 28.453 ;
     RECT  95.856 25.333 96.504 28.547 ;
     RECT  114.576 27.971 116.112 28.643 ;
     RECT  96 28.547 96.504 28.979 ;
     RECT  110.4 27.971 112.488 29.029 ;
     RECT  91.008 28.933 91.032 29.077 ;
     RECT  92.016 26.771 92.04 29.077 ;
     RECT  91.008 29.077 92.04 29.123 ;
     RECT  110.4 29.029 112.968 29.219 ;
     RECT  88.8 26.291 89.112 29.221 ;
     RECT  96.192 28.979 96.504 29.267 ;
     RECT  88.8 29.221 89.304 29.363 ;
     RECT  107.04 28.451 107.064 29.507 ;
     RECT  109.008 27.301 109.032 29.747 ;
     RECT  93.6 28.453 94.728 29.843 ;
     RECT  96.48 29.267 96.504 30.035 ;
     RECT  112.464 29.219 112.968 30.083 ;
     RECT  114.576 28.643 114.6 30.083 ;
     RECT  105 27.971 105.96 30.469 ;
     RECT  99.312 27.877 101.928 30.563 ;
     RECT  88.8 29.363 89.112 30.997 ;
     RECT  105 30.469 106.296 31.043 ;
     RECT  93.6 29.843 94.512 31.909 ;
     RECT  88.8 30.997 89.496 32.531 ;
     RECT  93.36 31.909 94.512 33.107 ;
     RECT  112.464 30.083 112.488 34.403 ;
     RECT  99.6 30.563 101.928 34.645 ;
     RECT  7.8 2.151 8.112 34.693 ;
     RECT  99.504 34.645 101.928 35.123 ;
     RECT  91.152 29.123 92.04 35.845 ;
     RECT  90.864 35.845 92.04 35.891 ;
     RECT  99.504 35.123 100.968 35.939 ;
     RECT  99.504 35.939 99.912 36.421 ;
     RECT  92.016 35.891 92.04 38.723 ;
     RECT  117.648 27.395 117.672 40.163 ;
     RECT  105 31.043 105.96 40.499 ;
     RECT  97.824 22.117 97.848 57.059 ;
     RECT  78 2.151 78.312 57.541 ;
     RECT  99.408 36.421 99.912 57.587 ;
     RECT  90.864 35.891 90.888 57.635 ;
     RECT  56.4 2.151 56.712 57.829 ;
     RECT  81.936 39.109 81.96 57.875 ;
     RECT  93.6 33.107 94.512 57.923 ;
     RECT  88.8 32.531 89.256 58.117 ;
     RECT  79.92 26.629 79.944 59.315 ;
     RECT  105 40.499 105.624 63.107 ;
     RECT  88.08 58.117 89.256 63.205 ;
     RECT  57.84 59.701 57.864 66.133 ;
     RECT  55.584 57.829 56.712 66.179 ;
     RECT  57.744 66.133 57.864 66.179 ;
     RECT  34.8 2.151 35.112 66.181 ;
     RECT  57.744 66.179 57.768 71.315 ;
     RECT  6.576 33.589 6.6 77.555 ;
     RECT  96.528 58.117 96.552 77.797 ;
     RECT  96.528 77.797 96.648 77.843 ;
     RECT  99.6 57.587 99.912 77.893 ;
     RECT  100.944 35.939 100.968 77.893 ;
     RECT  96.624 77.843 96.648 77.987 ;
     RECT  4.848 71.605 4.872 78.037 ;
     RECT  88.032 63.205 89.304 78.227 ;
     RECT  83.4 2.151 83.712 78.613 ;
     RECT  34.8 66.181 35.208 80.675 ;
     RECT  4.848 78.037 5.496 81.061 ;
     RECT  10.896 33.541 10.92 81.539 ;
     RECT  7.68 34.693 8.112 81.781 ;
     RECT  99.6 77.893 100.968 82.691 ;
     RECT  99.6 82.691 100.68 86.675 ;
     RECT  78 57.541 78.648 87.299 ;
     RECT  78 87.299 78.312 87.733 ;
     RECT  83.4 78.613 84.264 89.747 ;
     RECT  77.04 87.733 78.312 91.235 ;
     RECT  88.032 78.227 89.256 91.235 ;
     RECT  85.728 89.701 85.752 95.219 ;
     RECT  88.8 91.235 89.256 95.459 ;
     RECT  88.8 95.459 89.112 98.005 ;
     RECT  86.112 95.605 86.136 98.581 ;
     RECT  4.512 81.061 5.496 98.629 ;
     RECT  86.112 98.581 86.568 99.395 ;
     RECT  4.416 98.629 5.496 100.069 ;
     RECT  27.744 32.197 27.768 100.355 ;
     RECT  4.368 100.069 5.496 100.645 ;
     RECT  86.112 99.395 86.136 100.645 ;
     RECT  87.696 95.125 87.72 100.645 ;
     RECT  3.936 100.645 5.496 100.837 ;
     RECT  83.4 89.747 83.712 100.837 ;
     RECT  2.4 2.151 2.712 101.365 ;
     RECT  3.888 100.837 5.496 101.365 ;
     RECT  0.144 101.701 0.168 101.845 ;
     RECT  83.4 100.837 83.976 102.131 ;
     RECT  88.704 98.005 89.112 102.131 ;
     RECT  0.144 101.845 0.216 102.229 ;
     RECT  6.528 80.773 6.552 102.373 ;
     RECT  7.68 81.781 8.28 102.373 ;
     RECT  2.4 101.365 5.496 102.517 ;
     RECT  6.528 102.373 8.28 102.517 ;
     RECT  86.112 100.645 87.72 102.611 ;
     RECT  2.4 102.517 8.28 102.659 ;
     RECT  86.112 102.611 86.136 102.659 ;
     RECT  87.696 102.611 87.72 102.659 ;
     RECT  0.144 102.229 0.264 103.045 ;
     RECT  42.144 101.605 42.168 103.235 ;
     RECT  0.144 103.045 0.456 103.237 ;
     RECT  0.144 103.237 0.504 103.379 ;
     RECT  88.8 102.131 89.112 103.573 ;
     RECT  0.192 103.379 0.504 104.053 ;
     RECT  6.528 102.659 8.28 104.339 ;
     RECT  0.192 104.053 0.552 104.389 ;
     RECT  85.44 103.237 85.464 104.531 ;
     RECT  0.144 104.389 0.552 104.627 ;
     RECT  0.144 104.627 0.504 104.819 ;
     RECT  2.4 102.659 5.496 104.821 ;
     RECT  6.528 104.339 6.552 104.821 ;
     RECT  88.368 103.573 89.112 104.867 ;
     RECT  2.4 104.821 6.552 104.915 ;
     RECT  7.68 104.339 8.28 104.915 ;
     RECT  43.296 104.821 43.32 105.491 ;
     RECT  3.84 104.915 6.552 105.635 ;
     RECT  0.144 104.819 0.408 105.877 ;
     RECT  5.952 105.635 6.552 105.923 ;
     RECT  0.144 105.877 0.456 105.973 ;
     RECT  2.4 104.915 2.856 106.453 ;
     RECT  3.84 105.635 4.728 106.453 ;
     RECT  38.784 106.165 38.808 106.499 ;
     RECT  7.68 104.915 8.232 106.741 ;
     RECT  6.528 105.923 6.552 106.933 ;
     RECT  7.68 106.741 8.52 106.933 ;
     RECT  6.528 106.933 8.52 107.123 ;
     RECT  30.864 106.981 30.888 107.123 ;
     RECT  2.4 106.453 4.728 107.125 ;
     RECT  7.68 107.123 8.52 107.219 ;
     RECT  2.4 107.125 5.112 107.267 ;
     RECT  7.8 107.219 8.52 108.179 ;
     RECT  4.464 107.267 5.112 108.277 ;
     RECT  6.528 107.123 6.648 108.277 ;
     RECT  2.4 107.267 3.192 108.323 ;
     RECT  4.464 108.277 6.648 108.371 ;
     RECT  0.144 105.973 0.84 108.947 ;
     RECT  4.512 108.371 6.648 109.187 ;
     RECT  0.192 108.947 0.84 109.523 ;
     RECT  77.184 91.235 78.312 109.523 ;
     RECT  6.528 109.187 6.648 109.715 ;
     RECT  0.192 109.523 0.312 109.811 ;
     RECT  7.8 108.179 8.28 109.811 ;
     RECT  2.4 108.323 2.856 110.051 ;
     RECT  0.288 109.811 0.312 110.291 ;
     RECT  2.4 110.051 2.712 111.109 ;
     RECT  6.528 109.715 6.552 111.203 ;
     RECT  2.304 111.109 2.712 111.445 ;
     RECT  0.144 112.309 0.168 112.787 ;
     RECT  0.192 112.933 0.216 113.075 ;
     RECT  7.8 109.811 8.112 113.269 ;
     RECT  4.512 109.187 4.92 114.035 ;
     RECT  2.304 111.445 2.808 114.611 ;
     RECT  7.8 113.269 8.52 114.611 ;
     RECT  2.304 114.611 2.712 114.851 ;
     RECT  4.848 114.035 4.872 115.763 ;
     RECT  107.808 109.717 107.832 158.533 ;
     RECT  107.808 158.533 107.928 211.429 ;
     RECT  107.808 211.429 108.168 211.861 ;
     RECT  107.808 211.861 108.744 213.203 ;
     RECT  107.808 213.203 108.456 213.251 ;
     RECT  101.952 87.157 101.976 213.395 ;
     RECT  2.4 114.851 2.712 213.849 ;
     RECT  7.8 114.611 8.112 213.849 ;
     RECT  13.2 2.151 13.512 213.849 ;
     RECT  18.6 2.151 18.912 213.849 ;
     RECT  24 2.151 24.312 213.849 ;
     RECT  29.4 2.151 29.712 213.849 ;
     RECT  34.8 80.675 35.112 213.849 ;
     RECT  40.2 2.151 40.512 213.849 ;
     RECT  45.6 2.151 45.912 213.849 ;
     RECT  51 2.151 51.312 213.849 ;
     RECT  56.4 66.179 56.712 213.849 ;
     RECT  61.8 2.151 62.112 213.849 ;
     RECT  67.2 2.151 67.512 213.849 ;
     RECT  72.6 2.151 72.912 213.849 ;
     RECT  78 109.523 78.312 213.849 ;
     RECT  83.4 102.131 83.712 213.849 ;
     RECT  88.8 104.867 89.112 213.849 ;
     RECT  94.2 57.923 94.512 213.849 ;
     RECT  99.6 86.675 99.912 213.849 ;
     RECT  105 63.107 105.312 213.849 ;
     RECT  110.4 29.219 110.712 213.849 ;
     RECT  115.8 28.643 116.112 213.849 ;
     RECT  121.2 25.571 121.512 213.849 ;
     RECT  126.6 2.151 126.912 213.849 ;
     RECT  132 2.151 132.312 213.849 ;
     RECT  137.4 2.151 137.712 213.849 ;
     RECT  142.8 2.151 143.112 213.849 ;
     RECT  148.2 2.151 148.512 213.849 ;
     RECT  153.6 2.151 153.912 213.849 ;
     RECT  159 2.151 159.312 213.849 ;
     RECT  164.4 2.151 164.712 213.849 ;
     RECT  169.8 2.151 170.112 213.849 ;
     RECT  175.2 2.151 175.512 213.849 ;
     RECT  180.6 2.151 180.912 213.849 ;
     RECT  186 2.151 186.312 213.849 ;
     RECT  191.4 2.151 191.712 213.849 ;
     RECT  196.8 2.151 197.112 213.849 ;
     RECT  202.2 2.151 202.512 213.849 ;
     RECT  207.6 2.151 207.912 213.849 ;
     RECT  213 2.151 213.312 213.849 ;
     RECT  2.4 213.849 2.52 213.863 ;
     RECT  7.8 213.849 7.92 213.863 ;
     RECT  13.2 213.849 13.32 213.863 ;
     RECT  18.6 213.849 18.72 213.863 ;
     RECT  24 213.849 24.12 213.863 ;
     RECT  29.4 213.849 29.52 213.863 ;
     RECT  34.8 213.849 34.92 213.863 ;
     RECT  40.2 213.849 40.32 213.863 ;
     RECT  45.6 213.849 45.72 213.863 ;
     RECT  51 213.849 51.12 213.863 ;
     RECT  56.4 213.849 56.52 213.863 ;
     RECT  61.8 213.849 61.92 213.863 ;
     RECT  67.2 213.849 67.32 213.863 ;
     RECT  72.6 213.849 72.72 213.863 ;
     RECT  78 213.849 78.12 213.863 ;
     RECT  83.4 213.849 83.52 213.863 ;
     RECT  88.8 213.849 88.92 213.863 ;
     RECT  94.2 213.849 94.32 213.863 ;
     RECT  99.6 213.849 99.72 213.863 ;
     RECT  105 213.849 105.12 213.863 ;
     RECT  110.4 213.849 110.52 213.863 ;
     RECT  115.8 213.849 115.92 213.863 ;
     RECT  121.2 213.849 121.32 213.863 ;
     RECT  126.6 213.849 126.72 213.863 ;
     RECT  132 213.849 132.12 213.863 ;
     RECT  137.4 213.849 137.52 213.863 ;
     RECT  142.8 213.849 142.92 213.863 ;
     RECT  148.2 213.849 148.32 213.863 ;
     RECT  153.6 213.849 153.72 213.863 ;
     RECT  159 213.849 159.12 213.863 ;
     RECT  164.4 213.849 164.52 213.863 ;
     RECT  169.8 213.849 169.92 213.863 ;
     RECT  175.2 213.849 175.32 213.863 ;
     RECT  180.6 213.849 180.72 213.863 ;
     RECT  186 213.849 186.12 213.863 ;
     RECT  191.4 213.849 191.52 213.863 ;
     RECT  196.8 213.849 196.92 213.863 ;
     RECT  202.2 213.849 202.32 213.863 ;
     RECT  207.6 213.849 207.72 213.863 ;
     RECT  213 213.849 213.12 213.863 ;
     RECT  107.808 213.251 108.216 215.952 ;
     RECT  123.48 1.141 124.992 1.429 ;
     RECT  123.864 1.429 124.992 1.477 ;
     RECT  123.864 1.477 124.944 1.909 ;
     RECT  90.552 6.229 91.92 6.899 ;
     RECT  91.944 6.851 92.976 6.947 ;
     RECT  91.944 6.947 93.312 7.283 ;
     RECT  91.92 7.283 93.312 7.957 ;
     RECT  89.208 7.475 89.688 8.965 ;
     RECT  124.92 7.475 124.968 8.869 ;
     RECT  122.136 7.619 123.168 7.763 ;
     RECT  121.752 7.763 123.168 8.773 ;
     RECT  91.92 7.957 92.448 8.485 ;
     RECT  119.976 8.099 121.056 9.109 ;
     RECT  108.12 8.531 109.296 9.637 ;
     RECT  96.648 8.627 98.256 10.069 ;
     RECT  92.472 8.771 94.032 9.973 ;
     RECT  117.576 8.819 117.624 10.165 ;
     RECT  125.208 8.869 126.6 10.595 ;
     RECT  107.16 9.731 108.384 10.741 ;
     RECT  102.6 9.779 103.632 10.741 ;
     RECT  92.904 9.973 94.032 10.739 ;
     RECT  123.24 10.547 124.464 10.643 ;
     RECT  125.16 10.595 126.6 10.691 ;
     RECT  124.68 10.691 124.872 10.787 ;
     RECT  92.472 10.739 94.032 10.837 ;
     RECT  107.256 10.741 108.384 10.789 ;
     RECT  124.536 10.787 124.872 11.941 ;
     RECT  107.4 10.789 108.384 11.269 ;
     RECT  92.472 10.837 93.456 12.371 ;
     RECT  119.688 11.365 121.104 11.605 ;
     RECT  120.024 11.605 121.104 11.701 ;
     RECT  87.336 11.941 88.8 13.043 ;
     RECT  121.512 14.243 122.544 15.925 ;
     RECT  92.952 17.605 94.2 18.803 ;
     RECT  122.568 17.891 122.856 18.181 ;
     RECT  122.568 18.181 123.984 19.427 ;
     RECT  98.616 18.515 99.6 20.627 ;
     RECT  92.376 19.427 92.472 20.003 ;
     RECT  92.328 20.003 92.472 20.917 ;
     RECT  96.84 20.627 97.848 21.971 ;
     RECT  92.328 20.917 93.6 25.525 ;
     RECT  111.24 21.683 112.464 23.411 ;
     RECT  97.824 21.971 97.848 22.117 ;
     RECT  116.112 22.211 117.504 23.363 ;
     RECT  90.024 22.309 91.392 23.077 ;
     RECT  121.512 22.739 122.544 23.987 ;
     RECT  103.128 22.835 104.352 23.411 ;
     RECT  109.08 22.835 110.304 23.987 ;
     RECT  114.696 22.835 115.8 27.205 ;
     RECT  113.208 22.883 114.384 24.707 ;
     RECT  90.024 23.077 91.344 26.291 ;
     RECT  116.112 23.363 117.648 24.469 ;
     RECT  103.032 23.411 104.352 23.843 ;
     RECT  119.352 23.795 120.816 24.083 ;
     RECT  109.08 23.987 110.4 27.059 ;
     RECT  94.512 24.419 95.856 28.453 ;
     RECT  117.672 24.659 118.848 25.139 ;
     RECT  113.016 24.707 114.384 25.091 ;
     RECT  112.968 25.091 114.384 27.971 ;
     RECT  104.736 25.139 105 25.573 ;
     RECT  117.672 25.139 118.896 26.149 ;
     RECT  96.504 25.333 97.824 30.035 ;
     RECT  103.224 25.573 105 26.389 ;
     RECT  92.04 25.667 93.168 26.819 ;
     RECT  102.168 26.243 103.2 26.819 ;
     RECT  107.688 26.339 109.056 27.059 ;
     RECT  101.928 26.819 103.2 28.163 ;
     RECT  107.688 27.059 110.4 27.301 ;
     RECT  107.688 27.301 109.008 28.451 ;
     RECT  109.032 27.301 110.4 29.747 ;
     RECT  97.848 27.877 99.312 30.563 ;
     RECT  105.96 27.971 107.04 29.507 ;
     RECT  112.488 27.971 112.968 29.029 ;
     RECT  94.728 28.453 95.856 28.547 ;
     RECT  94.728 28.547 96 28.979 ;
     RECT  114.6 28.643 115.8 30.083 ;
     RECT  91.032 28.933 92.016 29.077 ;
     RECT  94.728 28.979 96.192 29.267 ;
     RECT  105.96 29.507 106.296 30.469 ;
     RECT  92.04 31.909 93.36 33.107 ;
     RECT  6.6 33.589 7.8 34.693 ;
     RECT  6.6 34.693 7.68 77.555 ;
     RECT  90.888 35.891 92.016 38.723 ;
     RECT  99.912 35.939 100.944 77.893 ;
     RECT  81.96 39.109 83.4 57.875 ;
     RECT  78.648 57.541 79.92 59.315 ;
     RECT  56.712 59.701 57.84 66.133 ;
     RECT  56.712 66.133 57.744 71.315 ;
     RECT  5.496 80.773 6.528 102.517 ;
     RECT  6.552 80.773 7.68 102.373 ;
     RECT  84.264 89.701 85.728 89.747 ;
     RECT  87.72 95.125 88.8 98.005 ;
     RECT  87.72 98.005 88.704 102.131 ;
     RECT  86.568 98.581 87.696 99.395 ;
     RECT  86.136 99.395 87.696 100.645 ;
     RECT  2.712 100.645 3.936 100.837 ;
     RECT  2.712 100.837 3.888 101.365 ;
     RECT  87.72 102.131 88.8 102.659 ;
     RECT  5.496 102.659 6.528 104.821 ;
     RECT  88.368 102.659 88.8 103.573 ;
     RECT  0.144 103.379 0.192 104.389 ;
     RECT  6.552 104.339 7.68 106.933 ;
     RECT  0.504 104.627 0.552 104.819 ;
     RECT  0.408 104.819 0.552 105.877 ;
     RECT  2.856 104.915 3.84 106.453 ;
     RECT  4.728 105.635 5.952 105.923 ;
     RECT  0.456 105.877 0.552 105.973 ;
     RECT  4.728 105.923 6.528 107.125 ;
     RECT  38.808 106.165 40.2 106.499 ;
     RECT  29.712 106.981 30.864 107.123 ;
     RECT  6.648 107.123 7.68 107.219 ;
     RECT  5.112 107.125 6.528 108.277 ;
     RECT  6.648 107.219 7.8 109.715 ;
     RECT  3.192 107.267 4.464 108.323 ;
     RECT  6.552 109.715 7.8 111.203 ;
     RECT  2.712 110.051 2.808 111.445 ;
  END
END ot_hbm_host_static_ingress
END LIBRARY
